VERSION 5.8 ;
BUSBITCHARS "[]" ;
DIVIDERCHAR "/" ;
UNITS
    DATABASE MICRONS 1000 ;
END UNITS

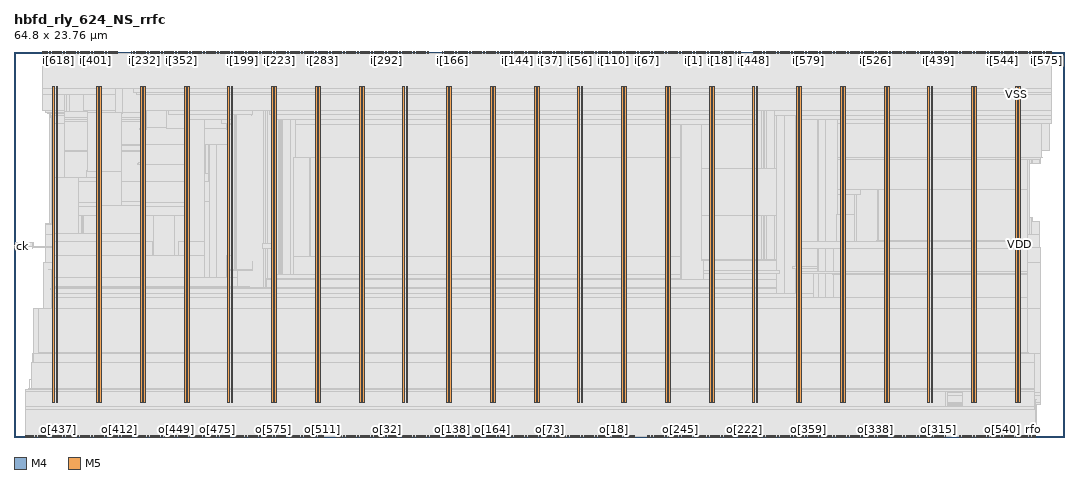
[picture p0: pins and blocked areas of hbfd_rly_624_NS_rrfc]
MACRO hbfd_rly_624_NS_rrfc
  FOREIGN hbfd_rly_624_NS_rrfc 0 0 ;
  CLASS BLOCK ;
  SIZE 64.8 BY 23.76 ;
  PIN ck
    DIRECTION INPUT ;
    USE SIGNAL ;
    PORT
      LAYER M4 ;
        RECT  0 11.76 0.084 11.784 ;
    END
  END ck
  PIN i[0]
    DIRECTION INPUT ;
    USE SIGNAL ;
    PORT
      LAYER M5 ;
        RECT  41.808 23.676 41.832 23.76 ;
    END
  END i[0]
  PIN i[100]
    DIRECTION INPUT ;
    USE SIGNAL ;
    PORT
      LAYER M5 ;
        RECT  36.048 23.676 36.072 23.76 ;
    END
  END i[100]
  PIN i[101]
    DIRECTION INPUT ;
    USE SIGNAL ;
    PORT
      LAYER M5 ;
        RECT  36.144 23.676 36.168 23.76 ;
    END
  END i[101]
  PIN i[102]
    DIRECTION INPUT ;
    USE SIGNAL ;
    PORT
      LAYER M5 ;
        RECT  36.24 23.676 36.264 23.76 ;
    END
  END i[102]
  PIN i[103]
    DIRECTION INPUT ;
    USE SIGNAL ;
    PORT
      LAYER M5 ;
        RECT  36.336 23.676 36.36 23.76 ;
    END
  END i[103]
  PIN i[104]
    DIRECTION INPUT ;
    USE SIGNAL ;
    PORT
      LAYER M5 ;
        RECT  36.432 23.676 36.456 23.76 ;
    END
  END i[104]
  PIN i[105]
    DIRECTION INPUT ;
    USE SIGNAL ;
    PORT
      LAYER M5 ;
        RECT  36.528 23.676 36.552 23.76 ;
    END
  END i[105]
  PIN i[106]
    DIRECTION INPUT ;
    USE SIGNAL ;
    PORT
      LAYER M5 ;
        RECT  36.624 23.676 36.648 23.76 ;
    END
  END i[106]
  PIN i[107]
    DIRECTION INPUT ;
    USE SIGNAL ;
    PORT
      LAYER M5 ;
        RECT  36.72 23.676 36.744 23.76 ;
    END
  END i[107]
  PIN i[108]
    DIRECTION INPUT ;
    USE SIGNAL ;
    PORT
      LAYER M5 ;
        RECT  36.816 23.676 36.84 23.76 ;
    END
  END i[108]
  PIN i[109]
    DIRECTION INPUT ;
    USE SIGNAL ;
    PORT
      LAYER M5 ;
        RECT  36.912 23.676 36.936 23.76 ;
    END
  END i[109]
  PIN i[10]
    DIRECTION INPUT ;
    USE SIGNAL ;
    PORT
      LAYER M5 ;
        RECT  42.768 23.676 42.792 23.76 ;
    END
  END i[10]
  PIN i[110]
    DIRECTION INPUT ;
    USE SIGNAL ;
    PORT
      LAYER M5 ;
        RECT  37.008 23.676 37.032 23.76 ;
    END
  END i[110]
  PIN i[111]
    DIRECTION INPUT ;
    USE SIGNAL ;
    PORT
      LAYER M5 ;
        RECT  37.104 23.676 37.128 23.76 ;
    END
  END i[111]
  PIN i[112]
    DIRECTION INPUT ;
    USE SIGNAL ;
    PORT
      LAYER M5 ;
        RECT  37.2 23.676 37.224 23.76 ;
    END
  END i[112]
  PIN i[113]
    DIRECTION INPUT ;
    USE SIGNAL ;
    PORT
      LAYER M5 ;
        RECT  37.296 23.676 37.32 23.76 ;
    END
  END i[113]
  PIN i[114]
    DIRECTION INPUT ;
    USE SIGNAL ;
    PORT
      LAYER M5 ;
        RECT  37.392 23.676 37.416 23.76 ;
    END
  END i[114]
  PIN i[115]
    DIRECTION INPUT ;
    USE SIGNAL ;
    PORT
      LAYER M5 ;
        RECT  37.488 23.676 37.512 23.76 ;
    END
  END i[115]
  PIN i[116]
    DIRECTION INPUT ;
    USE SIGNAL ;
    PORT
      LAYER M5 ;
        RECT  37.584 23.676 37.608 23.76 ;
    END
  END i[116]
  PIN i[117]
    DIRECTION INPUT ;
    USE SIGNAL ;
    PORT
      LAYER M5 ;
        RECT  37.68 23.676 37.704 23.76 ;
    END
  END i[117]
  PIN i[118]
    DIRECTION INPUT ;
    USE SIGNAL ;
    PORT
      LAYER M5 ;
        RECT  37.776 23.676 37.8 23.76 ;
    END
  END i[118]
  PIN i[119]
    DIRECTION INPUT ;
    USE SIGNAL ;
    PORT
      LAYER M5 ;
        RECT  37.872 23.676 37.896 23.76 ;
    END
  END i[119]
  PIN i[11]
    DIRECTION INPUT ;
    USE SIGNAL ;
    PORT
      LAYER M5 ;
        RECT  42.864 23.676 42.888 23.76 ;
    END
  END i[11]
  PIN i[120]
    DIRECTION INPUT ;
    USE SIGNAL ;
    PORT
      LAYER M5 ;
        RECT  37.968 23.676 37.992 23.76 ;
    END
  END i[120]
  PIN i[121]
    DIRECTION INPUT ;
    USE SIGNAL ;
    PORT
      LAYER M5 ;
        RECT  38.064 23.676 38.088 23.76 ;
    END
  END i[121]
  PIN i[122]
    DIRECTION INPUT ;
    USE SIGNAL ;
    PORT
      LAYER M5 ;
        RECT  38.16 23.676 38.184 23.76 ;
    END
  END i[122]
  PIN i[123]
    DIRECTION INPUT ;
    USE SIGNAL ;
    PORT
      LAYER M5 ;
        RECT  38.256 23.676 38.28 23.76 ;
    END
  END i[123]
  PIN i[124]
    DIRECTION INPUT ;
    USE SIGNAL ;
    PORT
      LAYER M5 ;
        RECT  38.352 23.676 38.376 23.76 ;
    END
  END i[124]
  PIN i[125]
    DIRECTION INPUT ;
    USE SIGNAL ;
    PORT
      LAYER M5 ;
        RECT  38.448 23.676 38.472 23.76 ;
    END
  END i[125]
  PIN i[126]
    DIRECTION INPUT ;
    USE SIGNAL ;
    PORT
      LAYER M5 ;
        RECT  38.544 23.676 38.568 23.76 ;
    END
  END i[126]
  PIN i[127]
    DIRECTION INPUT ;
    USE SIGNAL ;
    PORT
      LAYER M5 ;
        RECT  38.64 23.676 38.664 23.76 ;
    END
  END i[127]
  PIN i[128]
    DIRECTION INPUT ;
    USE SIGNAL ;
    PORT
      LAYER M5 ;
        RECT  29.52 23.676 29.544 23.76 ;
    END
  END i[128]
  PIN i[129]
    DIRECTION INPUT ;
    USE SIGNAL ;
    PORT
      LAYER M5 ;
        RECT  29.616 23.676 29.64 23.76 ;
    END
  END i[129]
  PIN i[12]
    DIRECTION INPUT ;
    USE SIGNAL ;
    PORT
      LAYER M5 ;
        RECT  42.96 23.676 42.984 23.76 ;
    END
  END i[12]
  PIN i[130]
    DIRECTION INPUT ;
    USE SIGNAL ;
    PORT
      LAYER M5 ;
        RECT  29.712 23.676 29.736 23.76 ;
    END
  END i[130]
  PIN i[131]
    DIRECTION INPUT ;
    USE SIGNAL ;
    PORT
      LAYER M5 ;
        RECT  29.808 23.676 29.832 23.76 ;
    END
  END i[131]
  PIN i[132]
    DIRECTION INPUT ;
    USE SIGNAL ;
    PORT
      LAYER M5 ;
        RECT  29.904 23.676 29.928 23.76 ;
    END
  END i[132]
  PIN i[133]
    DIRECTION INPUT ;
    USE SIGNAL ;
    PORT
      LAYER M5 ;
        RECT  30 23.676 30.024 23.76 ;
    END
  END i[133]
  PIN i[134]
    DIRECTION INPUT ;
    USE SIGNAL ;
    PORT
      LAYER M5 ;
        RECT  30.096 23.676 30.12 23.76 ;
    END
  END i[134]
  PIN i[135]
    DIRECTION INPUT ;
    USE SIGNAL ;
    PORT
      LAYER M5 ;
        RECT  30.192 23.676 30.216 23.76 ;
    END
  END i[135]
  PIN i[136]
    DIRECTION INPUT ;
    USE SIGNAL ;
    PORT
      LAYER M5 ;
        RECT  30.288 23.676 30.312 23.76 ;
    END
  END i[136]
  PIN i[137]
    DIRECTION INPUT ;
    USE SIGNAL ;
    PORT
      LAYER M5 ;
        RECT  30.384 23.676 30.408 23.76 ;
    END
  END i[137]
  PIN i[138]
    DIRECTION INPUT ;
    USE SIGNAL ;
    PORT
      LAYER M5 ;
        RECT  30.48 23.676 30.504 23.76 ;
    END
  END i[138]
  PIN i[139]
    DIRECTION INPUT ;
    USE SIGNAL ;
    PORT
      LAYER M5 ;
        RECT  30.576 23.676 30.6 23.76 ;
    END
  END i[139]
  PIN i[13]
    DIRECTION INPUT ;
    USE SIGNAL ;
    PORT
      LAYER M5 ;
        RECT  43.056 23.676 43.08 23.76 ;
    END
  END i[13]
  PIN i[140]
    DIRECTION INPUT ;
    USE SIGNAL ;
    PORT
      LAYER M5 ;
        RECT  30.672 23.676 30.696 23.76 ;
    END
  END i[140]
  PIN i[141]
    DIRECTION INPUT ;
    USE SIGNAL ;
    PORT
      LAYER M5 ;
        RECT  30.768 23.676 30.792 23.76 ;
    END
  END i[141]
  PIN i[142]
    DIRECTION INPUT ;
    USE SIGNAL ;
    PORT
      LAYER M5 ;
        RECT  30.864 23.676 30.888 23.76 ;
    END
  END i[142]
  PIN i[143]
    DIRECTION INPUT ;
    USE SIGNAL ;
    PORT
      LAYER M5 ;
        RECT  30.96 23.676 30.984 23.76 ;
    END
  END i[143]
  PIN i[144]
    DIRECTION INPUT ;
    USE SIGNAL ;
    PORT
      LAYER M5 ;
        RECT  31.056 23.676 31.08 23.76 ;
    END
  END i[144]
  PIN i[145]
    DIRECTION INPUT ;
    USE SIGNAL ;
    PORT
      LAYER M5 ;
        RECT  31.152 23.676 31.176 23.76 ;
    END
  END i[145]
  PIN i[146]
    DIRECTION INPUT ;
    USE SIGNAL ;
    PORT
      LAYER M5 ;
        RECT  31.248 23.676 31.272 23.76 ;
    END
  END i[146]
  PIN i[147]
    DIRECTION INPUT ;
    USE SIGNAL ;
    PORT
      LAYER M5 ;
        RECT  31.344 23.676 31.368 23.76 ;
    END
  END i[147]
  PIN i[148]
    DIRECTION INPUT ;
    USE SIGNAL ;
    PORT
      LAYER M5 ;
        RECT  31.44 23.676 31.464 23.76 ;
    END
  END i[148]
  PIN i[149]
    DIRECTION INPUT ;
    USE SIGNAL ;
    PORT
      LAYER M5 ;
        RECT  31.536 23.676 31.56 23.76 ;
    END
  END i[149]
  PIN i[14]
    DIRECTION INPUT ;
    USE SIGNAL ;
    PORT
      LAYER M5 ;
        RECT  43.152 23.676 43.176 23.76 ;
    END
  END i[14]
  PIN i[150]
    DIRECTION INPUT ;
    USE SIGNAL ;
    PORT
      LAYER M5 ;
        RECT  31.632 23.676 31.656 23.76 ;
    END
  END i[150]
  PIN i[151]
    DIRECTION INPUT ;
    USE SIGNAL ;
    PORT
      LAYER M5 ;
        RECT  31.728 23.676 31.752 23.76 ;
    END
  END i[151]
  PIN i[152]
    DIRECTION INPUT ;
    USE SIGNAL ;
    PORT
      LAYER M5 ;
        RECT  31.824 23.676 31.848 23.76 ;
    END
  END i[152]
  PIN i[153]
    DIRECTION INPUT ;
    USE SIGNAL ;
    PORT
      LAYER M5 ;
        RECT  31.92 23.676 31.944 23.76 ;
    END
  END i[153]
  PIN i[154]
    DIRECTION INPUT ;
    USE SIGNAL ;
    PORT
      LAYER M5 ;
        RECT  32.016 23.676 32.04 23.76 ;
    END
  END i[154]
  PIN i[155]
    DIRECTION INPUT ;
    USE SIGNAL ;
    PORT
      LAYER M5 ;
        RECT  32.112 23.676 32.136 23.76 ;
    END
  END i[155]
  PIN i[156]
    DIRECTION INPUT ;
    USE SIGNAL ;
    PORT
      LAYER M5 ;
        RECT  32.208 23.676 32.232 23.76 ;
    END
  END i[156]
  PIN i[157]
    DIRECTION INPUT ;
    USE SIGNAL ;
    PORT
      LAYER M5 ;
        RECT  32.304 23.676 32.328 23.76 ;
    END
  END i[157]
  PIN i[158]
    DIRECTION INPUT ;
    USE SIGNAL ;
    PORT
      LAYER M5 ;
        RECT  32.4 23.676 32.424 23.76 ;
    END
  END i[158]
  PIN i[159]
    DIRECTION INPUT ;
    USE SIGNAL ;
    PORT
      LAYER M5 ;
        RECT  32.496 23.676 32.52 23.76 ;
    END
  END i[159]
  PIN i[15]
    DIRECTION INPUT ;
    USE SIGNAL ;
    PORT
      LAYER M5 ;
        RECT  43.248 23.676 43.272 23.76 ;
    END
  END i[15]
  PIN i[160]
    DIRECTION INPUT ;
    USE SIGNAL ;
    PORT
      LAYER M5 ;
        RECT  26.448 23.676 26.472 23.76 ;
    END
  END i[160]
  PIN i[161]
    DIRECTION INPUT ;
    USE SIGNAL ;
    PORT
      LAYER M5 ;
        RECT  26.544 23.676 26.568 23.76 ;
    END
  END i[161]
  PIN i[162]
    DIRECTION INPUT ;
    USE SIGNAL ;
    PORT
      LAYER M5 ;
        RECT  26.64 23.676 26.664 23.76 ;
    END
  END i[162]
  PIN i[163]
    DIRECTION INPUT ;
    USE SIGNAL ;
    PORT
      LAYER M5 ;
        RECT  26.736 23.676 26.76 23.76 ;
    END
  END i[163]
  PIN i[164]
    DIRECTION INPUT ;
    USE SIGNAL ;
    PORT
      LAYER M5 ;
        RECT  26.832 23.676 26.856 23.76 ;
    END
  END i[164]
  PIN i[165]
    DIRECTION INPUT ;
    USE SIGNAL ;
    PORT
      LAYER M5 ;
        RECT  26.928 23.676 26.952 23.76 ;
    END
  END i[165]
  PIN i[166]
    DIRECTION INPUT ;
    USE SIGNAL ;
    PORT
      LAYER M5 ;
        RECT  27.024 23.676 27.048 23.76 ;
    END
  END i[166]
  PIN i[167]
    DIRECTION INPUT ;
    USE SIGNAL ;
    PORT
      LAYER M5 ;
        RECT  27.12 23.676 27.144 23.76 ;
    END
  END i[167]
  PIN i[168]
    DIRECTION INPUT ;
    USE SIGNAL ;
    PORT
      LAYER M5 ;
        RECT  27.216 23.676 27.24 23.76 ;
    END
  END i[168]
  PIN i[169]
    DIRECTION INPUT ;
    USE SIGNAL ;
    PORT
      LAYER M5 ;
        RECT  27.312 23.676 27.336 23.76 ;
    END
  END i[169]
  PIN i[16]
    DIRECTION INPUT ;
    USE SIGNAL ;
    PORT
      LAYER M5 ;
        RECT  43.344 23.676 43.368 23.76 ;
    END
  END i[16]
  PIN i[170]
    DIRECTION INPUT ;
    USE SIGNAL ;
    PORT
      LAYER M5 ;
        RECT  27.408 23.676 27.432 23.76 ;
    END
  END i[170]
  PIN i[171]
    DIRECTION INPUT ;
    USE SIGNAL ;
    PORT
      LAYER M5 ;
        RECT  27.504 23.676 27.528 23.76 ;
    END
  END i[171]
  PIN i[172]
    DIRECTION INPUT ;
    USE SIGNAL ;
    PORT
      LAYER M5 ;
        RECT  27.6 23.676 27.624 23.76 ;
    END
  END i[172]
  PIN i[173]
    DIRECTION INPUT ;
    USE SIGNAL ;
    PORT
      LAYER M5 ;
        RECT  27.696 23.676 27.72 23.76 ;
    END
  END i[173]
  PIN i[174]
    DIRECTION INPUT ;
    USE SIGNAL ;
    PORT
      LAYER M5 ;
        RECT  27.792 23.676 27.816 23.76 ;
    END
  END i[174]
  PIN i[175]
    DIRECTION INPUT ;
    USE SIGNAL ;
    PORT
      LAYER M5 ;
        RECT  27.888 23.676 27.912 23.76 ;
    END
  END i[175]
  PIN i[176]
    DIRECTION INPUT ;
    USE SIGNAL ;
    PORT
      LAYER M5 ;
        RECT  27.984 23.676 28.008 23.76 ;
    END
  END i[176]
  PIN i[177]
    DIRECTION INPUT ;
    USE SIGNAL ;
    PORT
      LAYER M5 ;
        RECT  28.08 23.676 28.104 23.76 ;
    END
  END i[177]
  PIN i[178]
    DIRECTION INPUT ;
    USE SIGNAL ;
    PORT
      LAYER M5 ;
        RECT  28.176 23.676 28.2 23.76 ;
    END
  END i[178]
  PIN i[179]
    DIRECTION INPUT ;
    USE SIGNAL ;
    PORT
      LAYER M5 ;
        RECT  28.272 23.676 28.296 23.76 ;
    END
  END i[179]
  PIN i[17]
    DIRECTION INPUT ;
    USE SIGNAL ;
    PORT
      LAYER M5 ;
        RECT  43.44 23.676 43.464 23.76 ;
    END
  END i[17]
  PIN i[180]
    DIRECTION INPUT ;
    USE SIGNAL ;
    PORT
      LAYER M5 ;
        RECT  28.368 23.676 28.392 23.76 ;
    END
  END i[180]
  PIN i[181]
    DIRECTION INPUT ;
    USE SIGNAL ;
    PORT
      LAYER M5 ;
        RECT  28.464 23.676 28.488 23.76 ;
    END
  END i[181]
  PIN i[182]
    DIRECTION INPUT ;
    USE SIGNAL ;
    PORT
      LAYER M5 ;
        RECT  28.56 23.676 28.584 23.76 ;
    END
  END i[182]
  PIN i[183]
    DIRECTION INPUT ;
    USE SIGNAL ;
    PORT
      LAYER M5 ;
        RECT  28.656 23.676 28.68 23.76 ;
    END
  END i[183]
  PIN i[184]
    DIRECTION INPUT ;
    USE SIGNAL ;
    PORT
      LAYER M5 ;
        RECT  28.752 23.676 28.776 23.76 ;
    END
  END i[184]
  PIN i[185]
    DIRECTION INPUT ;
    USE SIGNAL ;
    PORT
      LAYER M5 ;
        RECT  28.848 23.676 28.872 23.76 ;
    END
  END i[185]
  PIN i[186]
    DIRECTION INPUT ;
    USE SIGNAL ;
    PORT
      LAYER M5 ;
        RECT  28.944 23.676 28.968 23.76 ;
    END
  END i[186]
  PIN i[187]
    DIRECTION INPUT ;
    USE SIGNAL ;
    PORT
      LAYER M5 ;
        RECT  29.04 23.676 29.064 23.76 ;
    END
  END i[187]
  PIN i[188]
    DIRECTION INPUT ;
    USE SIGNAL ;
    PORT
      LAYER M5 ;
        RECT  29.136 23.676 29.16 23.76 ;
    END
  END i[188]
  PIN i[189]
    DIRECTION INPUT ;
    USE SIGNAL ;
    PORT
      LAYER M5 ;
        RECT  29.232 23.676 29.256 23.76 ;
    END
  END i[189]
  PIN i[18]
    DIRECTION INPUT ;
    USE SIGNAL ;
    PORT
      LAYER M5 ;
        RECT  43.536 23.676 43.56 23.76 ;
    END
  END i[18]
  PIN i[190]
    DIRECTION INPUT ;
    USE SIGNAL ;
    PORT
      LAYER M5 ;
        RECT  29.328 23.676 29.352 23.76 ;
    END
  END i[190]
  PIN i[191]
    DIRECTION INPUT ;
    USE SIGNAL ;
    PORT
      LAYER M5 ;
        RECT  29.424 23.676 29.448 23.76 ;
    END
  END i[191]
  PIN i[192]
    DIRECTION INPUT ;
    USE SIGNAL ;
    PORT
      LAYER M5 ;
        RECT  13.392 23.676 13.416 23.76 ;
    END
  END i[192]
  PIN i[193]
    DIRECTION INPUT ;
    USE SIGNAL ;
    PORT
      LAYER M5 ;
        RECT  13.488 23.676 13.512 23.76 ;
    END
  END i[193]
  PIN i[194]
    DIRECTION INPUT ;
    USE SIGNAL ;
    PORT
      LAYER M5 ;
        RECT  13.584 23.676 13.608 23.76 ;
    END
  END i[194]
  PIN i[195]
    DIRECTION INPUT ;
    USE SIGNAL ;
    PORT
      LAYER M5 ;
        RECT  13.68 23.676 13.704 23.76 ;
    END
  END i[195]
  PIN i[196]
    DIRECTION INPUT ;
    USE SIGNAL ;
    PORT
      LAYER M5 ;
        RECT  13.776 23.676 13.8 23.76 ;
    END
  END i[196]
  PIN i[197]
    DIRECTION INPUT ;
    USE SIGNAL ;
    PORT
      LAYER M5 ;
        RECT  13.872 23.676 13.896 23.76 ;
    END
  END i[197]
  PIN i[198]
    DIRECTION INPUT ;
    USE SIGNAL ;
    PORT
      LAYER M5 ;
        RECT  13.968 23.676 13.992 23.76 ;
    END
  END i[198]
  PIN i[199]
    DIRECTION INPUT ;
    USE SIGNAL ;
    PORT
      LAYER M5 ;
        RECT  14.064 23.676 14.088 23.76 ;
    END
  END i[199]
  PIN i[19]
    DIRECTION INPUT ;
    USE SIGNAL ;
    PORT
      LAYER M5 ;
        RECT  43.632 23.676 43.656 23.76 ;
    END
  END i[19]
  PIN i[1]
    DIRECTION INPUT ;
    USE SIGNAL ;
    PORT
      LAYER M5 ;
        RECT  41.904 23.676 41.928 23.76 ;
    END
  END i[1]
  PIN i[200]
    DIRECTION INPUT ;
    USE SIGNAL ;
    PORT
      LAYER M5 ;
        RECT  14.16 23.676 14.184 23.76 ;
    END
  END i[200]
  PIN i[201]
    DIRECTION INPUT ;
    USE SIGNAL ;
    PORT
      LAYER M5 ;
        RECT  14.256 23.676 14.28 23.76 ;
    END
  END i[201]
  PIN i[202]
    DIRECTION INPUT ;
    USE SIGNAL ;
    PORT
      LAYER M5 ;
        RECT  14.352 23.676 14.376 23.76 ;
    END
  END i[202]
  PIN i[203]
    DIRECTION INPUT ;
    USE SIGNAL ;
    PORT
      LAYER M5 ;
        RECT  14.448 23.676 14.472 23.76 ;
    END
  END i[203]
  PIN i[204]
    DIRECTION INPUT ;
    USE SIGNAL ;
    PORT
      LAYER M5 ;
        RECT  14.544 23.676 14.568 23.76 ;
    END
  END i[204]
  PIN i[205]
    DIRECTION INPUT ;
    USE SIGNAL ;
    PORT
      LAYER M5 ;
        RECT  14.64 23.676 14.664 23.76 ;
    END
  END i[205]
  PIN i[206]
    DIRECTION INPUT ;
    USE SIGNAL ;
    PORT
      LAYER M5 ;
        RECT  14.736 23.676 14.76 23.76 ;
    END
  END i[206]
  PIN i[207]
    DIRECTION INPUT ;
    USE SIGNAL ;
    PORT
      LAYER M5 ;
        RECT  14.832 23.676 14.856 23.76 ;
    END
  END i[207]
  PIN i[208]
    DIRECTION INPUT ;
    USE SIGNAL ;
    PORT
      LAYER M5 ;
        RECT  14.928 23.676 14.952 23.76 ;
    END
  END i[208]
  PIN i[209]
    DIRECTION INPUT ;
    USE SIGNAL ;
    PORT
      LAYER M5 ;
        RECT  15.024 23.676 15.048 23.76 ;
    END
  END i[209]
  PIN i[20]
    DIRECTION INPUT ;
    USE SIGNAL ;
    PORT
      LAYER M5 ;
        RECT  43.728 23.676 43.752 23.76 ;
    END
  END i[20]
  PIN i[210]
    DIRECTION INPUT ;
    USE SIGNAL ;
    PORT
      LAYER M5 ;
        RECT  15.12 23.676 15.144 23.76 ;
    END
  END i[210]
  PIN i[211]
    DIRECTION INPUT ;
    USE SIGNAL ;
    PORT
      LAYER M5 ;
        RECT  15.216 23.676 15.24 23.76 ;
    END
  END i[211]
  PIN i[212]
    DIRECTION INPUT ;
    USE SIGNAL ;
    PORT
      LAYER M5 ;
        RECT  15.312 23.676 15.336 23.76 ;
    END
  END i[212]
  PIN i[213]
    DIRECTION INPUT ;
    USE SIGNAL ;
    PORT
      LAYER M5 ;
        RECT  15.408 23.676 15.432 23.76 ;
    END
  END i[213]
  PIN i[214]
    DIRECTION INPUT ;
    USE SIGNAL ;
    PORT
      LAYER M5 ;
        RECT  15.504 23.676 15.528 23.76 ;
    END
  END i[214]
  PIN i[215]
    DIRECTION INPUT ;
    USE SIGNAL ;
    PORT
      LAYER M5 ;
        RECT  15.6 23.676 15.624 23.76 ;
    END
  END i[215]
  PIN i[216]
    DIRECTION INPUT ;
    USE SIGNAL ;
    PORT
      LAYER M5 ;
        RECT  15.696 23.676 15.72 23.76 ;
    END
  END i[216]
  PIN i[217]
    DIRECTION INPUT ;
    USE SIGNAL ;
    PORT
      LAYER M5 ;
        RECT  15.792 23.676 15.816 23.76 ;
    END
  END i[217]
  PIN i[218]
    DIRECTION INPUT ;
    USE SIGNAL ;
    PORT
      LAYER M5 ;
        RECT  15.888 23.676 15.912 23.76 ;
    END
  END i[218]
  PIN i[219]
    DIRECTION INPUT ;
    USE SIGNAL ;
    PORT
      LAYER M5 ;
        RECT  15.984 23.676 16.008 23.76 ;
    END
  END i[219]
  PIN i[21]
    DIRECTION INPUT ;
    USE SIGNAL ;
    PORT
      LAYER M5 ;
        RECT  43.824 23.676 43.848 23.76 ;
    END
  END i[21]
  PIN i[220]
    DIRECTION INPUT ;
    USE SIGNAL ;
    PORT
      LAYER M5 ;
        RECT  16.08 23.676 16.104 23.76 ;
    END
  END i[220]
  PIN i[221]
    DIRECTION INPUT ;
    USE SIGNAL ;
    PORT
      LAYER M5 ;
        RECT  16.176 23.676 16.2 23.76 ;
    END
  END i[221]
  PIN i[222]
    DIRECTION INPUT ;
    USE SIGNAL ;
    PORT
      LAYER M5 ;
        RECT  16.272 23.676 16.296 23.76 ;
    END
  END i[222]
  PIN i[223]
    DIRECTION INPUT ;
    USE SIGNAL ;
    PORT
      LAYER M5 ;
        RECT  16.368 23.676 16.392 23.76 ;
    END
  END i[223]
  PIN i[224]
    DIRECTION INPUT ;
    USE SIGNAL ;
    PORT
      LAYER M5 ;
        RECT  7.248 23.676 7.272 23.76 ;
    END
  END i[224]
  PIN i[225]
    DIRECTION INPUT ;
    USE SIGNAL ;
    PORT
      LAYER M5 ;
        RECT  7.344 23.676 7.368 23.76 ;
    END
  END i[225]
  PIN i[226]
    DIRECTION INPUT ;
    USE SIGNAL ;
    PORT
      LAYER M5 ;
        RECT  7.44 23.676 7.464 23.76 ;
    END
  END i[226]
  PIN i[227]
    DIRECTION INPUT ;
    USE SIGNAL ;
    PORT
      LAYER M5 ;
        RECT  7.536 23.676 7.56 23.76 ;
    END
  END i[227]
  PIN i[228]
    DIRECTION INPUT ;
    USE SIGNAL ;
    PORT
      LAYER M5 ;
        RECT  7.632 23.676 7.656 23.76 ;
    END
  END i[228]
  PIN i[229]
    DIRECTION INPUT ;
    USE SIGNAL ;
    PORT
      LAYER M5 ;
        RECT  7.728 23.676 7.752 23.76 ;
    END
  END i[229]
  PIN i[22]
    DIRECTION INPUT ;
    USE SIGNAL ;
    PORT
      LAYER M5 ;
        RECT  43.92 23.676 43.944 23.76 ;
    END
  END i[22]
  PIN i[230]
    DIRECTION INPUT ;
    USE SIGNAL ;
    PORT
      LAYER M5 ;
        RECT  7.824 23.676 7.848 23.76 ;
    END
  END i[230]
  PIN i[231]
    DIRECTION INPUT ;
    USE SIGNAL ;
    PORT
      LAYER M5 ;
        RECT  7.92 23.676 7.944 23.76 ;
    END
  END i[231]
  PIN i[232]
    DIRECTION INPUT ;
    USE SIGNAL ;
    PORT
      LAYER M5 ;
        RECT  8.016 23.676 8.04 23.76 ;
    END
  END i[232]
  PIN i[233]
    DIRECTION INPUT ;
    USE SIGNAL ;
    PORT
      LAYER M5 ;
        RECT  8.112 23.676 8.136 23.76 ;
    END
  END i[233]
  PIN i[234]
    DIRECTION INPUT ;
    USE SIGNAL ;
    PORT
      LAYER M5 ;
        RECT  8.208 23.676 8.232 23.76 ;
    END
  END i[234]
  PIN i[235]
    DIRECTION INPUT ;
    USE SIGNAL ;
    PORT
      LAYER M5 ;
        RECT  8.304 23.676 8.328 23.76 ;
    END
  END i[235]
  PIN i[236]
    DIRECTION INPUT ;
    USE SIGNAL ;
    PORT
      LAYER M5 ;
        RECT  8.4 23.676 8.424 23.76 ;
    END
  END i[236]
  PIN i[237]
    DIRECTION INPUT ;
    USE SIGNAL ;
    PORT
      LAYER M5 ;
        RECT  8.496 23.676 8.52 23.76 ;
    END
  END i[237]
  PIN i[238]
    DIRECTION INPUT ;
    USE SIGNAL ;
    PORT
      LAYER M5 ;
        RECT  8.592 23.676 8.616 23.76 ;
    END
  END i[238]
  PIN i[239]
    DIRECTION INPUT ;
    USE SIGNAL ;
    PORT
      LAYER M5 ;
        RECT  8.688 23.676 8.712 23.76 ;
    END
  END i[239]
  PIN i[23]
    DIRECTION INPUT ;
    USE SIGNAL ;
    PORT
      LAYER M5 ;
        RECT  44.016 23.676 44.04 23.76 ;
    END
  END i[23]
  PIN i[240]
    DIRECTION INPUT ;
    USE SIGNAL ;
    PORT
      LAYER M5 ;
        RECT  8.784 23.676 8.808 23.76 ;
    END
  END i[240]
  PIN i[241]
    DIRECTION INPUT ;
    USE SIGNAL ;
    PORT
      LAYER M5 ;
        RECT  8.88 23.676 8.904 23.76 ;
    END
  END i[241]
  PIN i[242]
    DIRECTION INPUT ;
    USE SIGNAL ;
    PORT
      LAYER M5 ;
        RECT  8.976 23.676 9 23.76 ;
    END
  END i[242]
  PIN i[243]
    DIRECTION INPUT ;
    USE SIGNAL ;
    PORT
      LAYER M5 ;
        RECT  9.072 23.676 9.096 23.76 ;
    END
  END i[243]
  PIN i[244]
    DIRECTION INPUT ;
    USE SIGNAL ;
    PORT
      LAYER M5 ;
        RECT  9.168 23.676 9.192 23.76 ;
    END
  END i[244]
  PIN i[245]
    DIRECTION INPUT ;
    USE SIGNAL ;
    PORT
      LAYER M5 ;
        RECT  9.264 23.676 9.288 23.76 ;
    END
  END i[245]
  PIN i[246]
    DIRECTION INPUT ;
    USE SIGNAL ;
    PORT
      LAYER M5 ;
        RECT  9.36 23.676 9.384 23.76 ;
    END
  END i[246]
  PIN i[247]
    DIRECTION INPUT ;
    USE SIGNAL ;
    PORT
      LAYER M5 ;
        RECT  9.456 23.676 9.48 23.76 ;
    END
  END i[247]
  PIN i[248]
    DIRECTION INPUT ;
    USE SIGNAL ;
    PORT
      LAYER M5 ;
        RECT  9.552 23.676 9.576 23.76 ;
    END
  END i[248]
  PIN i[249]
    DIRECTION INPUT ;
    USE SIGNAL ;
    PORT
      LAYER M5 ;
        RECT  9.648 23.676 9.672 23.76 ;
    END
  END i[249]
  PIN i[24]
    DIRECTION INPUT ;
    USE SIGNAL ;
    PORT
      LAYER M5 ;
        RECT  44.112 23.676 44.136 23.76 ;
    END
  END i[24]
  PIN i[250]
    DIRECTION INPUT ;
    USE SIGNAL ;
    PORT
      LAYER M5 ;
        RECT  9.744 23.676 9.768 23.76 ;
    END
  END i[250]
  PIN i[251]
    DIRECTION INPUT ;
    USE SIGNAL ;
    PORT
      LAYER M5 ;
        RECT  9.84 23.676 9.864 23.76 ;
    END
  END i[251]
  PIN i[252]
    DIRECTION INPUT ;
    USE SIGNAL ;
    PORT
      LAYER M5 ;
        RECT  9.936 23.676 9.96 23.76 ;
    END
  END i[252]
  PIN i[253]
    DIRECTION INPUT ;
    USE SIGNAL ;
    PORT
      LAYER M5 ;
        RECT  10.032 23.676 10.056 23.76 ;
    END
  END i[253]
  PIN i[254]
    DIRECTION INPUT ;
    USE SIGNAL ;
    PORT
      LAYER M5 ;
        RECT  10.128 23.676 10.152 23.76 ;
    END
  END i[254]
  PIN i[255]
    DIRECTION INPUT ;
    USE SIGNAL ;
    PORT
      LAYER M5 ;
        RECT  10.224 23.676 10.248 23.76 ;
    END
  END i[255]
  PIN i[256]
    DIRECTION INPUT ;
    USE SIGNAL ;
    PORT
      LAYER M5 ;
        RECT  16.464 23.676 16.488 23.76 ;
    END
  END i[256]
  PIN i[257]
    DIRECTION INPUT ;
    USE SIGNAL ;
    PORT
      LAYER M5 ;
        RECT  16.56 23.676 16.584 23.76 ;
    END
  END i[257]
  PIN i[258]
    DIRECTION INPUT ;
    USE SIGNAL ;
    PORT
      LAYER M5 ;
        RECT  16.656 23.676 16.68 23.76 ;
    END
  END i[258]
  PIN i[259]
    DIRECTION INPUT ;
    USE SIGNAL ;
    PORT
      LAYER M5 ;
        RECT  16.752 23.676 16.776 23.76 ;
    END
  END i[259]
  PIN i[25]
    DIRECTION INPUT ;
    USE SIGNAL ;
    PORT
      LAYER M5 ;
        RECT  44.208 23.676 44.232 23.76 ;
    END
  END i[25]
  PIN i[260]
    DIRECTION INPUT ;
    USE SIGNAL ;
    PORT
      LAYER M5 ;
        RECT  16.848 23.676 16.872 23.76 ;
    END
  END i[260]
  PIN i[261]
    DIRECTION INPUT ;
    USE SIGNAL ;
    PORT
      LAYER M5 ;
        RECT  16.944 23.676 16.968 23.76 ;
    END
  END i[261]
  PIN i[262]
    DIRECTION INPUT ;
    USE SIGNAL ;
    PORT
      LAYER M5 ;
        RECT  17.04 23.676 17.064 23.76 ;
    END
  END i[262]
  PIN i[263]
    DIRECTION INPUT ;
    USE SIGNAL ;
    PORT
      LAYER M5 ;
        RECT  17.136 23.676 17.16 23.76 ;
    END
  END i[263]
  PIN i[264]
    DIRECTION INPUT ;
    USE SIGNAL ;
    PORT
      LAYER M5 ;
        RECT  17.232 23.676 17.256 23.76 ;
    END
  END i[264]
  PIN i[265]
    DIRECTION INPUT ;
    USE SIGNAL ;
    PORT
      LAYER M5 ;
        RECT  17.328 23.676 17.352 23.76 ;
    END
  END i[265]
  PIN i[266]
    DIRECTION INPUT ;
    USE SIGNAL ;
    PORT
      LAYER M5 ;
        RECT  17.424 23.676 17.448 23.76 ;
    END
  END i[266]
  PIN i[267]
    DIRECTION INPUT ;
    USE SIGNAL ;
    PORT
      LAYER M5 ;
        RECT  17.52 23.676 17.544 23.76 ;
    END
  END i[267]
  PIN i[268]
    DIRECTION INPUT ;
    USE SIGNAL ;
    PORT
      LAYER M5 ;
        RECT  17.616 23.676 17.64 23.76 ;
    END
  END i[268]
  PIN i[269]
    DIRECTION INPUT ;
    USE SIGNAL ;
    PORT
      LAYER M5 ;
        RECT  17.712 23.676 17.736 23.76 ;
    END
  END i[269]
  PIN i[26]
    DIRECTION INPUT ;
    USE SIGNAL ;
    PORT
      LAYER M5 ;
        RECT  44.304 23.676 44.328 23.76 ;
    END
  END i[26]
  PIN i[270]
    DIRECTION INPUT ;
    USE SIGNAL ;
    PORT
      LAYER M5 ;
        RECT  17.808 23.676 17.832 23.76 ;
    END
  END i[270]
  PIN i[271]
    DIRECTION INPUT ;
    USE SIGNAL ;
    PORT
      LAYER M5 ;
        RECT  17.904 23.676 17.928 23.76 ;
    END
  END i[271]
  PIN i[272]
    DIRECTION INPUT ;
    USE SIGNAL ;
    PORT
      LAYER M5 ;
        RECT  18 23.676 18.024 23.76 ;
    END
  END i[272]
  PIN i[273]
    DIRECTION INPUT ;
    USE SIGNAL ;
    PORT
      LAYER M5 ;
        RECT  18.096 23.676 18.12 23.76 ;
    END
  END i[273]
  PIN i[274]
    DIRECTION INPUT ;
    USE SIGNAL ;
    PORT
      LAYER M5 ;
        RECT  18.192 23.676 18.216 23.76 ;
    END
  END i[274]
  PIN i[275]
    DIRECTION INPUT ;
    USE SIGNAL ;
    PORT
      LAYER M5 ;
        RECT  18.288 23.676 18.312 23.76 ;
    END
  END i[275]
  PIN i[276]
    DIRECTION INPUT ;
    USE SIGNAL ;
    PORT
      LAYER M5 ;
        RECT  18.384 23.676 18.408 23.76 ;
    END
  END i[276]
  PIN i[277]
    DIRECTION INPUT ;
    USE SIGNAL ;
    PORT
      LAYER M5 ;
        RECT  18.48 23.676 18.504 23.76 ;
    END
  END i[277]
  PIN i[278]
    DIRECTION INPUT ;
    USE SIGNAL ;
    PORT
      LAYER M5 ;
        RECT  18.576 23.676 18.6 23.76 ;
    END
  END i[278]
  PIN i[279]
    DIRECTION INPUT ;
    USE SIGNAL ;
    PORT
      LAYER M5 ;
        RECT  18.672 23.676 18.696 23.76 ;
    END
  END i[279]
  PIN i[27]
    DIRECTION INPUT ;
    USE SIGNAL ;
    PORT
      LAYER M5 ;
        RECT  44.4 23.676 44.424 23.76 ;
    END
  END i[27]
  PIN i[280]
    DIRECTION INPUT ;
    USE SIGNAL ;
    PORT
      LAYER M5 ;
        RECT  18.768 23.676 18.792 23.76 ;
    END
  END i[280]
  PIN i[281]
    DIRECTION INPUT ;
    USE SIGNAL ;
    PORT
      LAYER M5 ;
        RECT  18.864 23.676 18.888 23.76 ;
    END
  END i[281]
  PIN i[282]
    DIRECTION INPUT ;
    USE SIGNAL ;
    PORT
      LAYER M5 ;
        RECT  18.96 23.676 18.984 23.76 ;
    END
  END i[282]
  PIN i[283]
    DIRECTION INPUT ;
    USE SIGNAL ;
    PORT
      LAYER M5 ;
        RECT  19.056 23.676 19.08 23.76 ;
    END
  END i[283]
  PIN i[284]
    DIRECTION INPUT ;
    USE SIGNAL ;
    PORT
      LAYER M5 ;
        RECT  19.152 23.676 19.176 23.76 ;
    END
  END i[284]
  PIN i[285]
    DIRECTION INPUT ;
    USE SIGNAL ;
    PORT
      LAYER M5 ;
        RECT  19.248 23.676 19.272 23.76 ;
    END
  END i[285]
  PIN i[286]
    DIRECTION INPUT ;
    USE SIGNAL ;
    PORT
      LAYER M5 ;
        RECT  19.344 23.676 19.368 23.76 ;
    END
  END i[286]
  PIN i[287]
    DIRECTION INPUT ;
    USE SIGNAL ;
    PORT
      LAYER M5 ;
        RECT  19.44 23.676 19.464 23.76 ;
    END
  END i[287]
  PIN i[288]
    DIRECTION INPUT ;
    USE SIGNAL ;
    PORT
      LAYER M5 ;
        RECT  22.608 23.676 22.632 23.76 ;
    END
  END i[288]
  PIN i[289]
    DIRECTION INPUT ;
    USE SIGNAL ;
    PORT
      LAYER M5 ;
        RECT  22.704 23.676 22.728 23.76 ;
    END
  END i[289]
  PIN i[28]
    DIRECTION INPUT ;
    USE SIGNAL ;
    PORT
      LAYER M5 ;
        RECT  44.496 23.676 44.52 23.76 ;
    END
  END i[28]
  PIN i[290]
    DIRECTION INPUT ;
    USE SIGNAL ;
    PORT
      LAYER M5 ;
        RECT  22.8 23.676 22.824 23.76 ;
    END
  END i[290]
  PIN i[291]
    DIRECTION INPUT ;
    USE SIGNAL ;
    PORT
      LAYER M5 ;
        RECT  22.896 23.676 22.92 23.76 ;
    END
  END i[291]
  PIN i[292]
    DIRECTION INPUT ;
    USE SIGNAL ;
    PORT
      LAYER M5 ;
        RECT  22.992 23.676 23.016 23.76 ;
    END
  END i[292]
  PIN i[293]
    DIRECTION INPUT ;
    USE SIGNAL ;
    PORT
      LAYER M5 ;
        RECT  23.088 23.676 23.112 23.76 ;
    END
  END i[293]
  PIN i[294]
    DIRECTION INPUT ;
    USE SIGNAL ;
    PORT
      LAYER M5 ;
        RECT  23.184 23.676 23.208 23.76 ;
    END
  END i[294]
  PIN i[295]
    DIRECTION INPUT ;
    USE SIGNAL ;
    PORT
      LAYER M5 ;
        RECT  23.28 23.676 23.304 23.76 ;
    END
  END i[295]
  PIN i[296]
    DIRECTION INPUT ;
    USE SIGNAL ;
    PORT
      LAYER M5 ;
        RECT  23.376 23.676 23.4 23.76 ;
    END
  END i[296]
  PIN i[297]
    DIRECTION INPUT ;
    USE SIGNAL ;
    PORT
      LAYER M5 ;
        RECT  23.472 23.676 23.496 23.76 ;
    END
  END i[297]
  PIN i[298]
    DIRECTION INPUT ;
    USE SIGNAL ;
    PORT
      LAYER M5 ;
        RECT  23.568 23.676 23.592 23.76 ;
    END
  END i[298]
  PIN i[299]
    DIRECTION INPUT ;
    USE SIGNAL ;
    PORT
      LAYER M5 ;
        RECT  23.664 23.676 23.688 23.76 ;
    END
  END i[299]
  PIN i[29]
    DIRECTION INPUT ;
    USE SIGNAL ;
    PORT
      LAYER M5 ;
        RECT  44.592 23.676 44.616 23.76 ;
    END
  END i[29]
  PIN i[2]
    DIRECTION INPUT ;
    USE SIGNAL ;
    PORT
      LAYER M5 ;
        RECT  42 23.676 42.024 23.76 ;
    END
  END i[2]
  PIN i[300]
    DIRECTION INPUT ;
    USE SIGNAL ;
    PORT
      LAYER M5 ;
        RECT  23.76 23.676 23.784 23.76 ;
    END
  END i[300]
  PIN i[301]
    DIRECTION INPUT ;
    USE SIGNAL ;
    PORT
      LAYER M5 ;
        RECT  23.856 23.676 23.88 23.76 ;
    END
  END i[301]
  PIN i[302]
    DIRECTION INPUT ;
    USE SIGNAL ;
    PORT
      LAYER M5 ;
        RECT  23.952 23.676 23.976 23.76 ;
    END
  END i[302]
  PIN i[303]
    DIRECTION INPUT ;
    USE SIGNAL ;
    PORT
      LAYER M5 ;
        RECT  24.048 23.676 24.072 23.76 ;
    END
  END i[303]
  PIN i[304]
    DIRECTION INPUT ;
    USE SIGNAL ;
    PORT
      LAYER M5 ;
        RECT  24.144 23.676 24.168 23.76 ;
    END
  END i[304]
  PIN i[305]
    DIRECTION INPUT ;
    USE SIGNAL ;
    PORT
      LAYER M5 ;
        RECT  24.24 23.676 24.264 23.76 ;
    END
  END i[305]
  PIN i[306]
    DIRECTION INPUT ;
    USE SIGNAL ;
    PORT
      LAYER M5 ;
        RECT  24.336 23.676 24.36 23.76 ;
    END
  END i[306]
  PIN i[307]
    DIRECTION INPUT ;
    USE SIGNAL ;
    PORT
      LAYER M5 ;
        RECT  24.432 23.676 24.456 23.76 ;
    END
  END i[307]
  PIN i[308]
    DIRECTION INPUT ;
    USE SIGNAL ;
    PORT
      LAYER M5 ;
        RECT  24.528 23.676 24.552 23.76 ;
    END
  END i[308]
  PIN i[309]
    DIRECTION INPUT ;
    USE SIGNAL ;
    PORT
      LAYER M5 ;
        RECT  24.624 23.676 24.648 23.76 ;
    END
  END i[309]
  PIN i[30]
    DIRECTION INPUT ;
    USE SIGNAL ;
    PORT
      LAYER M5 ;
        RECT  44.688 23.676 44.712 23.76 ;
    END
  END i[30]
  PIN i[310]
    DIRECTION INPUT ;
    USE SIGNAL ;
    PORT
      LAYER M5 ;
        RECT  24.72 23.676 24.744 23.76 ;
    END
  END i[310]
  PIN i[311]
    DIRECTION INPUT ;
    USE SIGNAL ;
    PORT
      LAYER M5 ;
        RECT  24.816 23.676 24.84 23.76 ;
    END
  END i[311]
  PIN i[312]
    DIRECTION INPUT ;
    USE SIGNAL ;
    PORT
      LAYER M5 ;
        RECT  24.912 23.676 24.936 23.76 ;
    END
  END i[312]
  PIN i[313]
    DIRECTION INPUT ;
    USE SIGNAL ;
    PORT
      LAYER M5 ;
        RECT  25.008 23.676 25.032 23.76 ;
    END
  END i[313]
  PIN i[314]
    DIRECTION INPUT ;
    USE SIGNAL ;
    PORT
      LAYER M5 ;
        RECT  25.104 23.676 25.128 23.76 ;
    END
  END i[314]
  PIN i[315]
    DIRECTION INPUT ;
    USE SIGNAL ;
    PORT
      LAYER M5 ;
        RECT  25.2 23.676 25.224 23.76 ;
    END
  END i[315]
  PIN i[316]
    DIRECTION INPUT ;
    USE SIGNAL ;
    PORT
      LAYER M5 ;
        RECT  25.296 23.676 25.32 23.76 ;
    END
  END i[316]
  PIN i[317]
    DIRECTION INPUT ;
    USE SIGNAL ;
    PORT
      LAYER M5 ;
        RECT  25.392 23.676 25.416 23.76 ;
    END
  END i[317]
  PIN i[318]
    DIRECTION INPUT ;
    USE SIGNAL ;
    PORT
      LAYER M5 ;
        RECT  25.488 23.676 25.512 23.76 ;
    END
  END i[318]
  PIN i[319]
    DIRECTION INPUT ;
    USE SIGNAL ;
    PORT
      LAYER M5 ;
        RECT  25.584 23.676 25.608 23.76 ;
    END
  END i[319]
  PIN i[31]
    DIRECTION INPUT ;
    USE SIGNAL ;
    PORT
      LAYER M5 ;
        RECT  44.784 23.676 44.808 23.76 ;
    END
  END i[31]
  PIN i[320]
    DIRECTION INPUT ;
    USE SIGNAL ;
    PORT
      LAYER M5 ;
        RECT  19.536 23.676 19.56 23.76 ;
    END
  END i[320]
  PIN i[321]
    DIRECTION INPUT ;
    USE SIGNAL ;
    PORT
      LAYER M5 ;
        RECT  19.632 23.676 19.656 23.76 ;
    END
  END i[321]
  PIN i[322]
    DIRECTION INPUT ;
    USE SIGNAL ;
    PORT
      LAYER M5 ;
        RECT  19.728 23.676 19.752 23.76 ;
    END
  END i[322]
  PIN i[323]
    DIRECTION INPUT ;
    USE SIGNAL ;
    PORT
      LAYER M5 ;
        RECT  19.824 23.676 19.848 23.76 ;
    END
  END i[323]
  PIN i[324]
    DIRECTION INPUT ;
    USE SIGNAL ;
    PORT
      LAYER M5 ;
        RECT  19.92 23.676 19.944 23.76 ;
    END
  END i[324]
  PIN i[325]
    DIRECTION INPUT ;
    USE SIGNAL ;
    PORT
      LAYER M5 ;
        RECT  20.016 23.676 20.04 23.76 ;
    END
  END i[325]
  PIN i[326]
    DIRECTION INPUT ;
    USE SIGNAL ;
    PORT
      LAYER M5 ;
        RECT  20.112 23.676 20.136 23.76 ;
    END
  END i[326]
  PIN i[327]
    DIRECTION INPUT ;
    USE SIGNAL ;
    PORT
      LAYER M5 ;
        RECT  20.208 23.676 20.232 23.76 ;
    END
  END i[327]
  PIN i[328]
    DIRECTION INPUT ;
    USE SIGNAL ;
    PORT
      LAYER M5 ;
        RECT  20.304 23.676 20.328 23.76 ;
    END
  END i[328]
  PIN i[329]
    DIRECTION INPUT ;
    USE SIGNAL ;
    PORT
      LAYER M5 ;
        RECT  20.4 23.676 20.424 23.76 ;
    END
  END i[329]
  PIN i[32]
    DIRECTION INPUT ;
    USE SIGNAL ;
    PORT
      LAYER M5 ;
        RECT  32.592 23.676 32.616 23.76 ;
    END
  END i[32]
  PIN i[330]
    DIRECTION INPUT ;
    USE SIGNAL ;
    PORT
      LAYER M5 ;
        RECT  20.496 23.676 20.52 23.76 ;
    END
  END i[330]
  PIN i[331]
    DIRECTION INPUT ;
    USE SIGNAL ;
    PORT
      LAYER M5 ;
        RECT  20.592 23.676 20.616 23.76 ;
    END
  END i[331]
  PIN i[332]
    DIRECTION INPUT ;
    USE SIGNAL ;
    PORT
      LAYER M5 ;
        RECT  20.688 23.676 20.712 23.76 ;
    END
  END i[332]
  PIN i[333]
    DIRECTION INPUT ;
    USE SIGNAL ;
    PORT
      LAYER M5 ;
        RECT  20.784 23.676 20.808 23.76 ;
    END
  END i[333]
  PIN i[334]
    DIRECTION INPUT ;
    USE SIGNAL ;
    PORT
      LAYER M5 ;
        RECT  20.88 23.676 20.904 23.76 ;
    END
  END i[334]
  PIN i[335]
    DIRECTION INPUT ;
    USE SIGNAL ;
    PORT
      LAYER M5 ;
        RECT  20.976 23.676 21 23.76 ;
    END
  END i[335]
  PIN i[336]
    DIRECTION INPUT ;
    USE SIGNAL ;
    PORT
      LAYER M5 ;
        RECT  21.072 23.676 21.096 23.76 ;
    END
  END i[336]
  PIN i[337]
    DIRECTION INPUT ;
    USE SIGNAL ;
    PORT
      LAYER M5 ;
        RECT  21.168 23.676 21.192 23.76 ;
    END
  END i[337]
  PIN i[338]
    DIRECTION INPUT ;
    USE SIGNAL ;
    PORT
      LAYER M5 ;
        RECT  21.264 23.676 21.288 23.76 ;
    END
  END i[338]
  PIN i[339]
    DIRECTION INPUT ;
    USE SIGNAL ;
    PORT
      LAYER M5 ;
        RECT  21.36 23.676 21.384 23.76 ;
    END
  END i[339]
  PIN i[33]
    DIRECTION INPUT ;
    USE SIGNAL ;
    PORT
      LAYER M5 ;
        RECT  32.688 23.676 32.712 23.76 ;
    END
  END i[33]
  PIN i[340]
    DIRECTION INPUT ;
    USE SIGNAL ;
    PORT
      LAYER M5 ;
        RECT  21.456 23.676 21.48 23.76 ;
    END
  END i[340]
  PIN i[341]
    DIRECTION INPUT ;
    USE SIGNAL ;
    PORT
      LAYER M5 ;
        RECT  21.552 23.676 21.576 23.76 ;
    END
  END i[341]
  PIN i[342]
    DIRECTION INPUT ;
    USE SIGNAL ;
    PORT
      LAYER M5 ;
        RECT  21.648 23.676 21.672 23.76 ;
    END
  END i[342]
  PIN i[343]
    DIRECTION INPUT ;
    USE SIGNAL ;
    PORT
      LAYER M5 ;
        RECT  21.744 23.676 21.768 23.76 ;
    END
  END i[343]
  PIN i[344]
    DIRECTION INPUT ;
    USE SIGNAL ;
    PORT
      LAYER M5 ;
        RECT  21.84 23.676 21.864 23.76 ;
    END
  END i[344]
  PIN i[345]
    DIRECTION INPUT ;
    USE SIGNAL ;
    PORT
      LAYER M5 ;
        RECT  21.936 23.676 21.96 23.76 ;
    END
  END i[345]
  PIN i[346]
    DIRECTION INPUT ;
    USE SIGNAL ;
    PORT
      LAYER M5 ;
        RECT  22.032 23.676 22.056 23.76 ;
    END
  END i[346]
  PIN i[347]
    DIRECTION INPUT ;
    USE SIGNAL ;
    PORT
      LAYER M5 ;
        RECT  22.128 23.676 22.152 23.76 ;
    END
  END i[347]
  PIN i[348]
    DIRECTION INPUT ;
    USE SIGNAL ;
    PORT
      LAYER M5 ;
        RECT  22.224 23.676 22.248 23.76 ;
    END
  END i[348]
  PIN i[349]
    DIRECTION INPUT ;
    USE SIGNAL ;
    PORT
      LAYER M5 ;
        RECT  22.32 23.676 22.344 23.76 ;
    END
  END i[349]
  PIN i[34]
    DIRECTION INPUT ;
    USE SIGNAL ;
    PORT
      LAYER M5 ;
        RECT  32.784 23.676 32.808 23.76 ;
    END
  END i[34]
  PIN i[350]
    DIRECTION INPUT ;
    USE SIGNAL ;
    PORT
      LAYER M5 ;
        RECT  22.416 23.676 22.44 23.76 ;
    END
  END i[350]
  PIN i[351]
    DIRECTION INPUT ;
    USE SIGNAL ;
    PORT
      LAYER M5 ;
        RECT  22.512 23.676 22.536 23.76 ;
    END
  END i[351]
  PIN i[352]
    DIRECTION INPUT ;
    USE SIGNAL ;
    PORT
      LAYER M5 ;
        RECT  10.32 23.676 10.344 23.76 ;
    END
  END i[352]
  PIN i[353]
    DIRECTION INPUT ;
    USE SIGNAL ;
    PORT
      LAYER M5 ;
        RECT  10.416 23.676 10.44 23.76 ;
    END
  END i[353]
  PIN i[354]
    DIRECTION INPUT ;
    USE SIGNAL ;
    PORT
      LAYER M5 ;
        RECT  10.512 23.676 10.536 23.76 ;
    END
  END i[354]
  PIN i[355]
    DIRECTION INPUT ;
    USE SIGNAL ;
    PORT
      LAYER M5 ;
        RECT  10.608 23.676 10.632 23.76 ;
    END
  END i[355]
  PIN i[356]
    DIRECTION INPUT ;
    USE SIGNAL ;
    PORT
      LAYER M5 ;
        RECT  10.704 23.676 10.728 23.76 ;
    END
  END i[356]
  PIN i[357]
    DIRECTION INPUT ;
    USE SIGNAL ;
    PORT
      LAYER M5 ;
        RECT  10.8 23.676 10.824 23.76 ;
    END
  END i[357]
  PIN i[358]
    DIRECTION INPUT ;
    USE SIGNAL ;
    PORT
      LAYER M5 ;
        RECT  10.896 23.676 10.92 23.76 ;
    END
  END i[358]
  PIN i[359]
    DIRECTION INPUT ;
    USE SIGNAL ;
    PORT
      LAYER M5 ;
        RECT  10.992 23.676 11.016 23.76 ;
    END
  END i[359]
  PIN i[35]
    DIRECTION INPUT ;
    USE SIGNAL ;
    PORT
      LAYER M5 ;
        RECT  32.88 23.676 32.904 23.76 ;
    END
  END i[35]
  PIN i[360]
    DIRECTION INPUT ;
    USE SIGNAL ;
    PORT
      LAYER M5 ;
        RECT  11.088 23.676 11.112 23.76 ;
    END
  END i[360]
  PIN i[361]
    DIRECTION INPUT ;
    USE SIGNAL ;
    PORT
      LAYER M5 ;
        RECT  11.184 23.676 11.208 23.76 ;
    END
  END i[361]
  PIN i[362]
    DIRECTION INPUT ;
    USE SIGNAL ;
    PORT
      LAYER M5 ;
        RECT  11.28 23.676 11.304 23.76 ;
    END
  END i[362]
  PIN i[363]
    DIRECTION INPUT ;
    USE SIGNAL ;
    PORT
      LAYER M5 ;
        RECT  11.376 23.676 11.4 23.76 ;
    END
  END i[363]
  PIN i[364]
    DIRECTION INPUT ;
    USE SIGNAL ;
    PORT
      LAYER M5 ;
        RECT  11.472 23.676 11.496 23.76 ;
    END
  END i[364]
  PIN i[365]
    DIRECTION INPUT ;
    USE SIGNAL ;
    PORT
      LAYER M5 ;
        RECT  11.568 23.676 11.592 23.76 ;
    END
  END i[365]
  PIN i[366]
    DIRECTION INPUT ;
    USE SIGNAL ;
    PORT
      LAYER M5 ;
        RECT  11.664 23.676 11.688 23.76 ;
    END
  END i[366]
  PIN i[367]
    DIRECTION INPUT ;
    USE SIGNAL ;
    PORT
      LAYER M5 ;
        RECT  11.76 23.676 11.784 23.76 ;
    END
  END i[367]
  PIN i[368]
    DIRECTION INPUT ;
    USE SIGNAL ;
    PORT
      LAYER M5 ;
        RECT  11.856 23.676 11.88 23.76 ;
    END
  END i[368]
  PIN i[369]
    DIRECTION INPUT ;
    USE SIGNAL ;
    PORT
      LAYER M5 ;
        RECT  11.952 23.676 11.976 23.76 ;
    END
  END i[369]
  PIN i[36]
    DIRECTION INPUT ;
    USE SIGNAL ;
    PORT
      LAYER M5 ;
        RECT  32.976 23.676 33 23.76 ;
    END
  END i[36]
  PIN i[370]
    DIRECTION INPUT ;
    USE SIGNAL ;
    PORT
      LAYER M5 ;
        RECT  12.048 23.676 12.072 23.76 ;
    END
  END i[370]
  PIN i[371]
    DIRECTION INPUT ;
    USE SIGNAL ;
    PORT
      LAYER M5 ;
        RECT  12.144 23.676 12.168 23.76 ;
    END
  END i[371]
  PIN i[372]
    DIRECTION INPUT ;
    USE SIGNAL ;
    PORT
      LAYER M5 ;
        RECT  12.24 23.676 12.264 23.76 ;
    END
  END i[372]
  PIN i[373]
    DIRECTION INPUT ;
    USE SIGNAL ;
    PORT
      LAYER M5 ;
        RECT  12.336 23.676 12.36 23.76 ;
    END
  END i[373]
  PIN i[374]
    DIRECTION INPUT ;
    USE SIGNAL ;
    PORT
      LAYER M5 ;
        RECT  12.432 23.676 12.456 23.76 ;
    END
  END i[374]
  PIN i[375]
    DIRECTION INPUT ;
    USE SIGNAL ;
    PORT
      LAYER M5 ;
        RECT  12.528 23.676 12.552 23.76 ;
    END
  END i[375]
  PIN i[376]
    DIRECTION INPUT ;
    USE SIGNAL ;
    PORT
      LAYER M5 ;
        RECT  12.624 23.676 12.648 23.76 ;
    END
  END i[376]
  PIN i[377]
    DIRECTION INPUT ;
    USE SIGNAL ;
    PORT
      LAYER M5 ;
        RECT  12.72 23.676 12.744 23.76 ;
    END
  END i[377]
  PIN i[378]
    DIRECTION INPUT ;
    USE SIGNAL ;
    PORT
      LAYER M5 ;
        RECT  12.816 23.676 12.84 23.76 ;
    END
  END i[378]
  PIN i[379]
    DIRECTION INPUT ;
    USE SIGNAL ;
    PORT
      LAYER M5 ;
        RECT  12.912 23.676 12.936 23.76 ;
    END
  END i[379]
  PIN i[37]
    DIRECTION INPUT ;
    USE SIGNAL ;
    PORT
      LAYER M5 ;
        RECT  33.072 23.676 33.096 23.76 ;
    END
  END i[37]
  PIN i[380]
    DIRECTION INPUT ;
    USE SIGNAL ;
    PORT
      LAYER M5 ;
        RECT  13.008 23.676 13.032 23.76 ;
    END
  END i[380]
  PIN i[381]
    DIRECTION INPUT ;
    USE SIGNAL ;
    PORT
      LAYER M5 ;
        RECT  13.104 23.676 13.128 23.76 ;
    END
  END i[381]
  PIN i[382]
    DIRECTION INPUT ;
    USE SIGNAL ;
    PORT
      LAYER M5 ;
        RECT  13.2 23.676 13.224 23.76 ;
    END
  END i[382]
  PIN i[383]
    DIRECTION INPUT ;
    USE SIGNAL ;
    PORT
      LAYER M5 ;
        RECT  13.296 23.676 13.32 23.76 ;
    END
  END i[383]
  PIN i[384]
    DIRECTION INPUT ;
    USE SIGNAL ;
    PORT
      LAYER M5 ;
        RECT  3.408 23.676 3.432 23.76 ;
    END
  END i[384]
  PIN i[385]
    DIRECTION INPUT ;
    USE SIGNAL ;
    PORT
      LAYER M5 ;
        RECT  3.504 23.676 3.528 23.76 ;
    END
  END i[385]
  PIN i[386]
    DIRECTION INPUT ;
    USE SIGNAL ;
    PORT
      LAYER M5 ;
        RECT  3.6 23.676 3.624 23.76 ;
    END
  END i[386]
  PIN i[387]
    DIRECTION INPUT ;
    USE SIGNAL ;
    PORT
      LAYER M5 ;
        RECT  3.696 23.676 3.72 23.76 ;
    END
  END i[387]
  PIN i[388]
    DIRECTION INPUT ;
    USE SIGNAL ;
    PORT
      LAYER M5 ;
        RECT  3.792 23.676 3.816 23.76 ;
    END
  END i[388]
  PIN i[389]
    DIRECTION INPUT ;
    USE SIGNAL ;
    PORT
      LAYER M5 ;
        RECT  3.888 23.676 3.912 23.76 ;
    END
  END i[389]
  PIN i[38]
    DIRECTION INPUT ;
    USE SIGNAL ;
    PORT
      LAYER M5 ;
        RECT  33.168 23.676 33.192 23.76 ;
    END
  END i[38]
  PIN i[390]
    DIRECTION INPUT ;
    USE SIGNAL ;
    PORT
      LAYER M5 ;
        RECT  3.984 23.676 4.008 23.76 ;
    END
  END i[390]
  PIN i[391]
    DIRECTION INPUT ;
    USE SIGNAL ;
    PORT
      LAYER M5 ;
        RECT  4.08 23.676 4.104 23.76 ;
    END
  END i[391]
  PIN i[392]
    DIRECTION INPUT ;
    USE SIGNAL ;
    PORT
      LAYER M5 ;
        RECT  4.176 23.676 4.2 23.76 ;
    END
  END i[392]
  PIN i[393]
    DIRECTION INPUT ;
    USE SIGNAL ;
    PORT
      LAYER M5 ;
        RECT  4.272 23.676 4.296 23.76 ;
    END
  END i[393]
  PIN i[394]
    DIRECTION INPUT ;
    USE SIGNAL ;
    PORT
      LAYER M5 ;
        RECT  4.368 23.676 4.392 23.76 ;
    END
  END i[394]
  PIN i[395]
    DIRECTION INPUT ;
    USE SIGNAL ;
    PORT
      LAYER M5 ;
        RECT  4.464 23.676 4.488 23.76 ;
    END
  END i[395]
  PIN i[396]
    DIRECTION INPUT ;
    USE SIGNAL ;
    PORT
      LAYER M5 ;
        RECT  4.56 23.676 4.584 23.76 ;
    END
  END i[396]
  PIN i[397]
    DIRECTION INPUT ;
    USE SIGNAL ;
    PORT
      LAYER M5 ;
        RECT  4.656 23.676 4.68 23.76 ;
    END
  END i[397]
  PIN i[398]
    DIRECTION INPUT ;
    USE SIGNAL ;
    PORT
      LAYER M5 ;
        RECT  4.752 23.676 4.776 23.76 ;
    END
  END i[398]
  PIN i[399]
    DIRECTION INPUT ;
    USE SIGNAL ;
    PORT
      LAYER M5 ;
        RECT  4.848 23.676 4.872 23.76 ;
    END
  END i[399]
  PIN i[39]
    DIRECTION INPUT ;
    USE SIGNAL ;
    PORT
      LAYER M5 ;
        RECT  33.264 23.676 33.288 23.76 ;
    END
  END i[39]
  PIN i[3]
    DIRECTION INPUT ;
    USE SIGNAL ;
    PORT
      LAYER M5 ;
        RECT  42.096 23.676 42.12 23.76 ;
    END
  END i[3]
  PIN i[400]
    DIRECTION INPUT ;
    USE SIGNAL ;
    PORT
      LAYER M5 ;
        RECT  4.944 23.676 4.968 23.76 ;
    END
  END i[400]
  PIN i[401]
    DIRECTION INPUT ;
    USE SIGNAL ;
    PORT
      LAYER M5 ;
        RECT  5.04 23.676 5.064 23.76 ;
    END
  END i[401]
  PIN i[402]
    DIRECTION INPUT ;
    USE SIGNAL ;
    PORT
      LAYER M5 ;
        RECT  5.136 23.676 5.16 23.76 ;
    END
  END i[402]
  PIN i[403]
    DIRECTION INPUT ;
    USE SIGNAL ;
    PORT
      LAYER M5 ;
        RECT  5.232 23.676 5.256 23.76 ;
    END
  END i[403]
  PIN i[404]
    DIRECTION INPUT ;
    USE SIGNAL ;
    PORT
      LAYER M5 ;
        RECT  5.328 23.676 5.352 23.76 ;
    END
  END i[404]
  PIN i[405]
    DIRECTION INPUT ;
    USE SIGNAL ;
    PORT
      LAYER M5 ;
        RECT  5.424 23.676 5.448 23.76 ;
    END
  END i[405]
  PIN i[406]
    DIRECTION INPUT ;
    USE SIGNAL ;
    PORT
      LAYER M5 ;
        RECT  5.52 23.676 5.544 23.76 ;
    END
  END i[406]
  PIN i[407]
    DIRECTION INPUT ;
    USE SIGNAL ;
    PORT
      LAYER M5 ;
        RECT  5.616 23.676 5.64 23.76 ;
    END
  END i[407]
  PIN i[408]
    DIRECTION INPUT ;
    USE SIGNAL ;
    PORT
      LAYER M5 ;
        RECT  5.712 23.676 5.736 23.76 ;
    END
  END i[408]
  PIN i[409]
    DIRECTION INPUT ;
    USE SIGNAL ;
    PORT
      LAYER M5 ;
        RECT  5.808 23.676 5.832 23.76 ;
    END
  END i[409]
  PIN i[40]
    DIRECTION INPUT ;
    USE SIGNAL ;
    PORT
      LAYER M5 ;
        RECT  33.36 23.676 33.384 23.76 ;
    END
  END i[40]
  PIN i[410]
    DIRECTION INPUT ;
    USE SIGNAL ;
    PORT
      LAYER M5 ;
        RECT  5.904 23.676 5.928 23.76 ;
    END
  END i[410]
  PIN i[411]
    DIRECTION INPUT ;
    USE SIGNAL ;
    PORT
      LAYER M5 ;
        RECT  6 23.676 6.024 23.76 ;
    END
  END i[411]
  PIN i[412]
    DIRECTION INPUT ;
    USE SIGNAL ;
    PORT
      LAYER M5 ;
        RECT  6.096 23.676 6.12 23.76 ;
    END
  END i[412]
  PIN i[413]
    DIRECTION INPUT ;
    USE SIGNAL ;
    PORT
      LAYER M5 ;
        RECT  6.192 23.676 6.216 23.76 ;
    END
  END i[413]
  PIN i[414]
    DIRECTION INPUT ;
    USE SIGNAL ;
    PORT
      LAYER M5 ;
        RECT  6.288 23.676 6.312 23.76 ;
    END
  END i[414]
  PIN i[415]
    DIRECTION INPUT ;
    USE SIGNAL ;
    PORT
      LAYER M5 ;
        RECT  6.384 23.676 6.408 23.76 ;
    END
  END i[415]
  PIN i[416]
    DIRECTION INPUT ;
    USE SIGNAL ;
    PORT
      LAYER M5 ;
        RECT  54.864 23.676 54.888 23.76 ;
    END
  END i[416]
  PIN i[417]
    DIRECTION INPUT ;
    USE SIGNAL ;
    PORT
      LAYER M5 ;
        RECT  54.96 23.676 54.984 23.76 ;
    END
  END i[417]
  PIN i[418]
    DIRECTION INPUT ;
    USE SIGNAL ;
    PORT
      LAYER M5 ;
        RECT  55.056 23.676 55.08 23.76 ;
    END
  END i[418]
  PIN i[419]
    DIRECTION INPUT ;
    USE SIGNAL ;
    PORT
      LAYER M5 ;
        RECT  55.152 23.676 55.176 23.76 ;
    END
  END i[419]
  PIN i[41]
    DIRECTION INPUT ;
    USE SIGNAL ;
    PORT
      LAYER M5 ;
        RECT  33.456 23.676 33.48 23.76 ;
    END
  END i[41]
  PIN i[420]
    DIRECTION INPUT ;
    USE SIGNAL ;
    PORT
      LAYER M5 ;
        RECT  55.248 23.676 55.272 23.76 ;
    END
  END i[420]
  PIN i[421]
    DIRECTION INPUT ;
    USE SIGNAL ;
    PORT
      LAYER M5 ;
        RECT  55.344 23.676 55.368 23.76 ;
    END
  END i[421]
  PIN i[422]
    DIRECTION INPUT ;
    USE SIGNAL ;
    PORT
      LAYER M5 ;
        RECT  55.44 23.676 55.464 23.76 ;
    END
  END i[422]
  PIN i[423]
    DIRECTION INPUT ;
    USE SIGNAL ;
    PORT
      LAYER M5 ;
        RECT  55.536 23.676 55.56 23.76 ;
    END
  END i[423]
  PIN i[424]
    DIRECTION INPUT ;
    USE SIGNAL ;
    PORT
      LAYER M5 ;
        RECT  55.632 23.676 55.656 23.76 ;
    END
  END i[424]
  PIN i[425]
    DIRECTION INPUT ;
    USE SIGNAL ;
    PORT
      LAYER M5 ;
        RECT  55.728 23.676 55.752 23.76 ;
    END
  END i[425]
  PIN i[426]
    DIRECTION INPUT ;
    USE SIGNAL ;
    PORT
      LAYER M5 ;
        RECT  55.824 23.676 55.848 23.76 ;
    END
  END i[426]
  PIN i[427]
    DIRECTION INPUT ;
    USE SIGNAL ;
    PORT
      LAYER M5 ;
        RECT  55.92 23.676 55.944 23.76 ;
    END
  END i[427]
  PIN i[428]
    DIRECTION INPUT ;
    USE SIGNAL ;
    PORT
      LAYER M5 ;
        RECT  56.016 23.676 56.04 23.76 ;
    END
  END i[428]
  PIN i[429]
    DIRECTION INPUT ;
    USE SIGNAL ;
    PORT
      LAYER M5 ;
        RECT  56.112 23.676 56.136 23.76 ;
    END
  END i[429]
  PIN i[42]
    DIRECTION INPUT ;
    USE SIGNAL ;
    PORT
      LAYER M5 ;
        RECT  33.552 23.676 33.576 23.76 ;
    END
  END i[42]
  PIN i[430]
    DIRECTION INPUT ;
    USE SIGNAL ;
    PORT
      LAYER M5 ;
        RECT  56.208 23.676 56.232 23.76 ;
    END
  END i[430]
  PIN i[431]
    DIRECTION INPUT ;
    USE SIGNAL ;
    PORT
      LAYER M5 ;
        RECT  56.304 23.676 56.328 23.76 ;
    END
  END i[431]
  PIN i[432]
    DIRECTION INPUT ;
    USE SIGNAL ;
    PORT
      LAYER M5 ;
        RECT  56.4 23.676 56.424 23.76 ;
    END
  END i[432]
  PIN i[433]
    DIRECTION INPUT ;
    USE SIGNAL ;
    PORT
      LAYER M5 ;
        RECT  56.496 23.676 56.52 23.76 ;
    END
  END i[433]
  PIN i[434]
    DIRECTION INPUT ;
    USE SIGNAL ;
    PORT
      LAYER M5 ;
        RECT  56.592 23.676 56.616 23.76 ;
    END
  END i[434]
  PIN i[435]
    DIRECTION INPUT ;
    USE SIGNAL ;
    PORT
      LAYER M5 ;
        RECT  56.688 23.676 56.712 23.76 ;
    END
  END i[435]
  PIN i[436]
    DIRECTION INPUT ;
    USE SIGNAL ;
    PORT
      LAYER M5 ;
        RECT  56.784 23.676 56.808 23.76 ;
    END
  END i[436]
  PIN i[437]
    DIRECTION INPUT ;
    USE SIGNAL ;
    PORT
      LAYER M5 ;
        RECT  56.88 23.676 56.904 23.76 ;
    END
  END i[437]
  PIN i[438]
    DIRECTION INPUT ;
    USE SIGNAL ;
    PORT
      LAYER M5 ;
        RECT  56.976 23.676 57 23.76 ;
    END
  END i[438]
  PIN i[439]
    DIRECTION INPUT ;
    USE SIGNAL ;
    PORT
      LAYER M5 ;
        RECT  57.072 23.676 57.096 23.76 ;
    END
  END i[439]
  PIN i[43]
    DIRECTION INPUT ;
    USE SIGNAL ;
    PORT
      LAYER M5 ;
        RECT  33.648 23.676 33.672 23.76 ;
    END
  END i[43]
  PIN i[440]
    DIRECTION INPUT ;
    USE SIGNAL ;
    PORT
      LAYER M5 ;
        RECT  57.168 23.676 57.192 23.76 ;
    END
  END i[440]
  PIN i[441]
    DIRECTION INPUT ;
    USE SIGNAL ;
    PORT
      LAYER M5 ;
        RECT  57.264 23.676 57.288 23.76 ;
    END
  END i[441]
  PIN i[442]
    DIRECTION INPUT ;
    USE SIGNAL ;
    PORT
      LAYER M5 ;
        RECT  57.36 23.676 57.384 23.76 ;
    END
  END i[442]
  PIN i[443]
    DIRECTION INPUT ;
    USE SIGNAL ;
    PORT
      LAYER M5 ;
        RECT  57.456 23.676 57.48 23.76 ;
    END
  END i[443]
  PIN i[444]
    DIRECTION INPUT ;
    USE SIGNAL ;
    PORT
      LAYER M5 ;
        RECT  57.552 23.676 57.576 23.76 ;
    END
  END i[444]
  PIN i[445]
    DIRECTION INPUT ;
    USE SIGNAL ;
    PORT
      LAYER M5 ;
        RECT  57.648 23.676 57.672 23.76 ;
    END
  END i[445]
  PIN i[446]
    DIRECTION INPUT ;
    USE SIGNAL ;
    PORT
      LAYER M5 ;
        RECT  57.744 23.676 57.768 23.76 ;
    END
  END i[446]
  PIN i[447]
    DIRECTION INPUT ;
    USE SIGNAL ;
    PORT
      LAYER M5 ;
        RECT  57.84 23.676 57.864 23.76 ;
    END
  END i[447]
  PIN i[448]
    DIRECTION INPUT ;
    USE SIGNAL ;
    PORT
      LAYER M5 ;
        RECT  45.648 23.676 45.672 23.76 ;
    END
  END i[448]
  PIN i[449]
    DIRECTION INPUT ;
    USE SIGNAL ;
    PORT
      LAYER M5 ;
        RECT  45.744 23.676 45.768 23.76 ;
    END
  END i[449]
  PIN i[44]
    DIRECTION INPUT ;
    USE SIGNAL ;
    PORT
      LAYER M5 ;
        RECT  33.744 23.676 33.768 23.76 ;
    END
  END i[44]
  PIN i[450]
    DIRECTION INPUT ;
    USE SIGNAL ;
    PORT
      LAYER M5 ;
        RECT  45.84 23.676 45.864 23.76 ;
    END
  END i[450]
  PIN i[451]
    DIRECTION INPUT ;
    USE SIGNAL ;
    PORT
      LAYER M5 ;
        RECT  45.936 23.676 45.96 23.76 ;
    END
  END i[451]
  PIN i[452]
    DIRECTION INPUT ;
    USE SIGNAL ;
    PORT
      LAYER M5 ;
        RECT  46.032 23.676 46.056 23.76 ;
    END
  END i[452]
  PIN i[453]
    DIRECTION INPUT ;
    USE SIGNAL ;
    PORT
      LAYER M5 ;
        RECT  46.128 23.676 46.152 23.76 ;
    END
  END i[453]
  PIN i[454]
    DIRECTION INPUT ;
    USE SIGNAL ;
    PORT
      LAYER M5 ;
        RECT  46.224 23.676 46.248 23.76 ;
    END
  END i[454]
  PIN i[455]
    DIRECTION INPUT ;
    USE SIGNAL ;
    PORT
      LAYER M5 ;
        RECT  46.32 23.676 46.344 23.76 ;
    END
  END i[455]
  PIN i[456]
    DIRECTION INPUT ;
    USE SIGNAL ;
    PORT
      LAYER M5 ;
        RECT  46.416 23.676 46.44 23.76 ;
    END
  END i[456]
  PIN i[457]
    DIRECTION INPUT ;
    USE SIGNAL ;
    PORT
      LAYER M5 ;
        RECT  46.512 23.676 46.536 23.76 ;
    END
  END i[457]
  PIN i[458]
    DIRECTION INPUT ;
    USE SIGNAL ;
    PORT
      LAYER M5 ;
        RECT  46.608 23.676 46.632 23.76 ;
    END
  END i[458]
  PIN i[459]
    DIRECTION INPUT ;
    USE SIGNAL ;
    PORT
      LAYER M5 ;
        RECT  46.704 23.676 46.728 23.76 ;
    END
  END i[459]
  PIN i[45]
    DIRECTION INPUT ;
    USE SIGNAL ;
    PORT
      LAYER M5 ;
        RECT  33.84 23.676 33.864 23.76 ;
    END
  END i[45]
  PIN i[460]
    DIRECTION INPUT ;
    USE SIGNAL ;
    PORT
      LAYER M5 ;
        RECT  46.8 23.676 46.824 23.76 ;
    END
  END i[460]
  PIN i[461]
    DIRECTION INPUT ;
    USE SIGNAL ;
    PORT
      LAYER M5 ;
        RECT  46.896 23.676 46.92 23.76 ;
    END
  END i[461]
  PIN i[462]
    DIRECTION INPUT ;
    USE SIGNAL ;
    PORT
      LAYER M5 ;
        RECT  46.992 23.676 47.016 23.76 ;
    END
  END i[462]
  PIN i[463]
    DIRECTION INPUT ;
    USE SIGNAL ;
    PORT
      LAYER M5 ;
        RECT  47.088 23.676 47.112 23.76 ;
    END
  END i[463]
  PIN i[464]
    DIRECTION INPUT ;
    USE SIGNAL ;
    PORT
      LAYER M5 ;
        RECT  47.184 23.676 47.208 23.76 ;
    END
  END i[464]
  PIN i[465]
    DIRECTION INPUT ;
    USE SIGNAL ;
    PORT
      LAYER M5 ;
        RECT  47.28 23.676 47.304 23.76 ;
    END
  END i[465]
  PIN i[466]
    DIRECTION INPUT ;
    USE SIGNAL ;
    PORT
      LAYER M5 ;
        RECT  47.376 23.676 47.4 23.76 ;
    END
  END i[466]
  PIN i[467]
    DIRECTION INPUT ;
    USE SIGNAL ;
    PORT
      LAYER M5 ;
        RECT  47.472 23.676 47.496 23.76 ;
    END
  END i[467]
  PIN i[468]
    DIRECTION INPUT ;
    USE SIGNAL ;
    PORT
      LAYER M5 ;
        RECT  47.568 23.676 47.592 23.76 ;
    END
  END i[468]
  PIN i[469]
    DIRECTION INPUT ;
    USE SIGNAL ;
    PORT
      LAYER M5 ;
        RECT  47.664 23.676 47.688 23.76 ;
    END
  END i[469]
  PIN i[46]
    DIRECTION INPUT ;
    USE SIGNAL ;
    PORT
      LAYER M5 ;
        RECT  33.936 23.676 33.96 23.76 ;
    END
  END i[46]
  PIN i[470]
    DIRECTION INPUT ;
    USE SIGNAL ;
    PORT
      LAYER M5 ;
        RECT  47.76 23.676 47.784 23.76 ;
    END
  END i[470]
  PIN i[471]
    DIRECTION INPUT ;
    USE SIGNAL ;
    PORT
      LAYER M5 ;
        RECT  47.856 23.676 47.88 23.76 ;
    END
  END i[471]
  PIN i[472]
    DIRECTION INPUT ;
    USE SIGNAL ;
    PORT
      LAYER M5 ;
        RECT  47.952 23.676 47.976 23.76 ;
    END
  END i[472]
  PIN i[473]
    DIRECTION INPUT ;
    USE SIGNAL ;
    PORT
      LAYER M5 ;
        RECT  48.048 23.676 48.072 23.76 ;
    END
  END i[473]
  PIN i[474]
    DIRECTION INPUT ;
    USE SIGNAL ;
    PORT
      LAYER M5 ;
        RECT  48.144 23.676 48.168 23.76 ;
    END
  END i[474]
  PIN i[475]
    DIRECTION INPUT ;
    USE SIGNAL ;
    PORT
      LAYER M5 ;
        RECT  48.24 23.676 48.264 23.76 ;
    END
  END i[475]
  PIN i[476]
    DIRECTION INPUT ;
    USE SIGNAL ;
    PORT
      LAYER M5 ;
        RECT  48.336 23.676 48.36 23.76 ;
    END
  END i[476]
  PIN i[477]
    DIRECTION INPUT ;
    USE SIGNAL ;
    PORT
      LAYER M5 ;
        RECT  48.432 23.676 48.456 23.76 ;
    END
  END i[477]
  PIN i[478]
    DIRECTION INPUT ;
    USE SIGNAL ;
    PORT
      LAYER M5 ;
        RECT  48.528 23.676 48.552 23.76 ;
    END
  END i[478]
  PIN i[479]
    DIRECTION INPUT ;
    USE SIGNAL ;
    PORT
      LAYER M5 ;
        RECT  48.624 23.676 48.648 23.76 ;
    END
  END i[479]
  PIN i[47]
    DIRECTION INPUT ;
    USE SIGNAL ;
    PORT
      LAYER M5 ;
        RECT  34.032 23.676 34.056 23.76 ;
    END
  END i[47]
  PIN i[480]
    DIRECTION INPUT ;
    USE SIGNAL ;
    PORT
      LAYER M5 ;
        RECT  57.936 23.676 57.96 23.76 ;
    END
  END i[480]
  PIN i[481]
    DIRECTION INPUT ;
    USE SIGNAL ;
    PORT
      LAYER M5 ;
        RECT  58.032 23.676 58.056 23.76 ;
    END
  END i[481]
  PIN i[482]
    DIRECTION INPUT ;
    USE SIGNAL ;
    PORT
      LAYER M5 ;
        RECT  58.128 23.676 58.152 23.76 ;
    END
  END i[482]
  PIN i[483]
    DIRECTION INPUT ;
    USE SIGNAL ;
    PORT
      LAYER M5 ;
        RECT  58.224 23.676 58.248 23.76 ;
    END
  END i[483]
  PIN i[484]
    DIRECTION INPUT ;
    USE SIGNAL ;
    PORT
      LAYER M5 ;
        RECT  58.32 23.676 58.344 23.76 ;
    END
  END i[484]
  PIN i[485]
    DIRECTION INPUT ;
    USE SIGNAL ;
    PORT
      LAYER M5 ;
        RECT  58.416 23.676 58.44 23.76 ;
    END
  END i[485]
  PIN i[486]
    DIRECTION INPUT ;
    USE SIGNAL ;
    PORT
      LAYER M5 ;
        RECT  58.512 23.676 58.536 23.76 ;
    END
  END i[486]
  PIN i[487]
    DIRECTION INPUT ;
    USE SIGNAL ;
    PORT
      LAYER M5 ;
        RECT  58.608 23.676 58.632 23.76 ;
    END
  END i[487]
  PIN i[488]
    DIRECTION INPUT ;
    USE SIGNAL ;
    PORT
      LAYER M5 ;
        RECT  58.704 23.676 58.728 23.76 ;
    END
  END i[488]
  PIN i[489]
    DIRECTION INPUT ;
    USE SIGNAL ;
    PORT
      LAYER M5 ;
        RECT  58.8 23.676 58.824 23.76 ;
    END
  END i[489]
  PIN i[48]
    DIRECTION INPUT ;
    USE SIGNAL ;
    PORT
      LAYER M5 ;
        RECT  34.128 23.676 34.152 23.76 ;
    END
  END i[48]
  PIN i[490]
    DIRECTION INPUT ;
    USE SIGNAL ;
    PORT
      LAYER M5 ;
        RECT  58.896 23.676 58.92 23.76 ;
    END
  END i[490]
  PIN i[491]
    DIRECTION INPUT ;
    USE SIGNAL ;
    PORT
      LAYER M5 ;
        RECT  58.992 23.676 59.016 23.76 ;
    END
  END i[491]
  PIN i[492]
    DIRECTION INPUT ;
    USE SIGNAL ;
    PORT
      LAYER M5 ;
        RECT  59.088 23.676 59.112 23.76 ;
    END
  END i[492]
  PIN i[493]
    DIRECTION INPUT ;
    USE SIGNAL ;
    PORT
      LAYER M5 ;
        RECT  59.184 23.676 59.208 23.76 ;
    END
  END i[493]
  PIN i[494]
    DIRECTION INPUT ;
    USE SIGNAL ;
    PORT
      LAYER M5 ;
        RECT  59.28 23.676 59.304 23.76 ;
    END
  END i[494]
  PIN i[495]
    DIRECTION INPUT ;
    USE SIGNAL ;
    PORT
      LAYER M5 ;
        RECT  59.376 23.676 59.4 23.76 ;
    END
  END i[495]
  PIN i[496]
    DIRECTION INPUT ;
    USE SIGNAL ;
    PORT
      LAYER M5 ;
        RECT  59.472 23.676 59.496 23.76 ;
    END
  END i[496]
  PIN i[497]
    DIRECTION INPUT ;
    USE SIGNAL ;
    PORT
      LAYER M5 ;
        RECT  59.568 23.676 59.592 23.76 ;
    END
  END i[497]
  PIN i[498]
    DIRECTION INPUT ;
    USE SIGNAL ;
    PORT
      LAYER M5 ;
        RECT  59.664 23.676 59.688 23.76 ;
    END
  END i[498]
  PIN i[499]
    DIRECTION INPUT ;
    USE SIGNAL ;
    PORT
      LAYER M5 ;
        RECT  59.76 23.676 59.784 23.76 ;
    END
  END i[499]
  PIN i[49]
    DIRECTION INPUT ;
    USE SIGNAL ;
    PORT
      LAYER M5 ;
        RECT  34.224 23.676 34.248 23.76 ;
    END
  END i[49]
  PIN i[4]
    DIRECTION INPUT ;
    USE SIGNAL ;
    PORT
      LAYER M5 ;
        RECT  42.192 23.676 42.216 23.76 ;
    END
  END i[4]
  PIN i[500]
    DIRECTION INPUT ;
    USE SIGNAL ;
    PORT
      LAYER M5 ;
        RECT  59.856 23.676 59.88 23.76 ;
    END
  END i[500]
  PIN i[501]
    DIRECTION INPUT ;
    USE SIGNAL ;
    PORT
      LAYER M5 ;
        RECT  59.952 23.676 59.976 23.76 ;
    END
  END i[501]
  PIN i[502]
    DIRECTION INPUT ;
    USE SIGNAL ;
    PORT
      LAYER M5 ;
        RECT  60.048 23.676 60.072 23.76 ;
    END
  END i[502]
  PIN i[503]
    DIRECTION INPUT ;
    USE SIGNAL ;
    PORT
      LAYER M5 ;
        RECT  60.144 23.676 60.168 23.76 ;
    END
  END i[503]
  PIN i[504]
    DIRECTION INPUT ;
    USE SIGNAL ;
    PORT
      LAYER M5 ;
        RECT  60.24 23.676 60.264 23.76 ;
    END
  END i[504]
  PIN i[505]
    DIRECTION INPUT ;
    USE SIGNAL ;
    PORT
      LAYER M5 ;
        RECT  60.336 23.676 60.36 23.76 ;
    END
  END i[505]
  PIN i[506]
    DIRECTION INPUT ;
    USE SIGNAL ;
    PORT
      LAYER M5 ;
        RECT  60.432 23.676 60.456 23.76 ;
    END
  END i[506]
  PIN i[507]
    DIRECTION INPUT ;
    USE SIGNAL ;
    PORT
      LAYER M5 ;
        RECT  60.528 23.676 60.552 23.76 ;
    END
  END i[507]
  PIN i[508]
    DIRECTION INPUT ;
    USE SIGNAL ;
    PORT
      LAYER M5 ;
        RECT  60.624 23.676 60.648 23.76 ;
    END
  END i[508]
  PIN i[509]
    DIRECTION INPUT ;
    USE SIGNAL ;
    PORT
      LAYER M5 ;
        RECT  60.72 23.676 60.744 23.76 ;
    END
  END i[509]
  PIN i[50]
    DIRECTION INPUT ;
    USE SIGNAL ;
    PORT
      LAYER M5 ;
        RECT  34.32 23.676 34.344 23.76 ;
    END
  END i[50]
  PIN i[510]
    DIRECTION INPUT ;
    USE SIGNAL ;
    PORT
      LAYER M5 ;
        RECT  60.816 23.676 60.84 23.76 ;
    END
  END i[510]
  PIN i[511]
    DIRECTION INPUT ;
    USE SIGNAL ;
    PORT
      LAYER M5 ;
        RECT  60.912 23.676 60.936 23.76 ;
    END
  END i[511]
  PIN i[512]
    DIRECTION INPUT ;
    USE SIGNAL ;
    PORT
      LAYER M5 ;
        RECT  51.792 23.676 51.816 23.76 ;
    END
  END i[512]
  PIN i[513]
    DIRECTION INPUT ;
    USE SIGNAL ;
    PORT
      LAYER M5 ;
        RECT  51.888 23.676 51.912 23.76 ;
    END
  END i[513]
  PIN i[514]
    DIRECTION INPUT ;
    USE SIGNAL ;
    PORT
      LAYER M5 ;
        RECT  51.984 23.676 52.008 23.76 ;
    END
  END i[514]
  PIN i[515]
    DIRECTION INPUT ;
    USE SIGNAL ;
    PORT
      LAYER M5 ;
        RECT  52.08 23.676 52.104 23.76 ;
    END
  END i[515]
  PIN i[516]
    DIRECTION INPUT ;
    USE SIGNAL ;
    PORT
      LAYER M5 ;
        RECT  52.176 23.676 52.2 23.76 ;
    END
  END i[516]
  PIN i[517]
    DIRECTION INPUT ;
    USE SIGNAL ;
    PORT
      LAYER M5 ;
        RECT  52.272 23.676 52.296 23.76 ;
    END
  END i[517]
  PIN i[518]
    DIRECTION INPUT ;
    USE SIGNAL ;
    PORT
      LAYER M5 ;
        RECT  52.368 23.676 52.392 23.76 ;
    END
  END i[518]
  PIN i[519]
    DIRECTION INPUT ;
    USE SIGNAL ;
    PORT
      LAYER M5 ;
        RECT  52.464 23.676 52.488 23.76 ;
    END
  END i[519]
  PIN i[51]
    DIRECTION INPUT ;
    USE SIGNAL ;
    PORT
      LAYER M5 ;
        RECT  34.416 23.676 34.44 23.76 ;
    END
  END i[51]
  PIN i[520]
    DIRECTION INPUT ;
    USE SIGNAL ;
    PORT
      LAYER M5 ;
        RECT  52.56 23.676 52.584 23.76 ;
    END
  END i[520]
  PIN i[521]
    DIRECTION INPUT ;
    USE SIGNAL ;
    PORT
      LAYER M5 ;
        RECT  52.656 23.676 52.68 23.76 ;
    END
  END i[521]
  PIN i[522]
    DIRECTION INPUT ;
    USE SIGNAL ;
    PORT
      LAYER M5 ;
        RECT  52.752 23.676 52.776 23.76 ;
    END
  END i[522]
  PIN i[523]
    DIRECTION INPUT ;
    USE SIGNAL ;
    PORT
      LAYER M5 ;
        RECT  52.848 23.676 52.872 23.76 ;
    END
  END i[523]
  PIN i[524]
    DIRECTION INPUT ;
    USE SIGNAL ;
    PORT
      LAYER M5 ;
        RECT  52.944 23.676 52.968 23.76 ;
    END
  END i[524]
  PIN i[525]
    DIRECTION INPUT ;
    USE SIGNAL ;
    PORT
      LAYER M5 ;
        RECT  53.04 23.676 53.064 23.76 ;
    END
  END i[525]
  PIN i[526]
    DIRECTION INPUT ;
    USE SIGNAL ;
    PORT
      LAYER M5 ;
        RECT  53.136 23.676 53.16 23.76 ;
    END
  END i[526]
  PIN i[527]
    DIRECTION INPUT ;
    USE SIGNAL ;
    PORT
      LAYER M5 ;
        RECT  53.232 23.676 53.256 23.76 ;
    END
  END i[527]
  PIN i[528]
    DIRECTION INPUT ;
    USE SIGNAL ;
    PORT
      LAYER M5 ;
        RECT  53.328 23.676 53.352 23.76 ;
    END
  END i[528]
  PIN i[529]
    DIRECTION INPUT ;
    USE SIGNAL ;
    PORT
      LAYER M5 ;
        RECT  53.424 23.676 53.448 23.76 ;
    END
  END i[529]
  PIN i[52]
    DIRECTION INPUT ;
    USE SIGNAL ;
    PORT
      LAYER M5 ;
        RECT  34.512 23.676 34.536 23.76 ;
    END
  END i[52]
  PIN i[530]
    DIRECTION INPUT ;
    USE SIGNAL ;
    PORT
      LAYER M5 ;
        RECT  53.52 23.676 53.544 23.76 ;
    END
  END i[530]
  PIN i[531]
    DIRECTION INPUT ;
    USE SIGNAL ;
    PORT
      LAYER M5 ;
        RECT  53.616 23.676 53.64 23.76 ;
    END
  END i[531]
  PIN i[532]
    DIRECTION INPUT ;
    USE SIGNAL ;
    PORT
      LAYER M5 ;
        RECT  53.712 23.676 53.736 23.76 ;
    END
  END i[532]
  PIN i[533]
    DIRECTION INPUT ;
    USE SIGNAL ;
    PORT
      LAYER M5 ;
        RECT  53.808 23.676 53.832 23.76 ;
    END
  END i[533]
  PIN i[534]
    DIRECTION INPUT ;
    USE SIGNAL ;
    PORT
      LAYER M5 ;
        RECT  53.904 23.676 53.928 23.76 ;
    END
  END i[534]
  PIN i[535]
    DIRECTION INPUT ;
    USE SIGNAL ;
    PORT
      LAYER M5 ;
        RECT  54 23.676 54.024 23.76 ;
    END
  END i[535]
  PIN i[536]
    DIRECTION INPUT ;
    USE SIGNAL ;
    PORT
      LAYER M5 ;
        RECT  54.096 23.676 54.12 23.76 ;
    END
  END i[536]
  PIN i[537]
    DIRECTION INPUT ;
    USE SIGNAL ;
    PORT
      LAYER M5 ;
        RECT  54.192 23.676 54.216 23.76 ;
    END
  END i[537]
  PIN i[538]
    DIRECTION INPUT ;
    USE SIGNAL ;
    PORT
      LAYER M5 ;
        RECT  54.288 23.676 54.312 23.76 ;
    END
  END i[538]
  PIN i[539]
    DIRECTION INPUT ;
    USE SIGNAL ;
    PORT
      LAYER M5 ;
        RECT  54.384 23.676 54.408 23.76 ;
    END
  END i[539]
  PIN i[53]
    DIRECTION INPUT ;
    USE SIGNAL ;
    PORT
      LAYER M5 ;
        RECT  34.608 23.676 34.632 23.76 ;
    END
  END i[53]
  PIN i[540]
    DIRECTION INPUT ;
    USE SIGNAL ;
    PORT
      LAYER M5 ;
        RECT  54.48 23.676 54.504 23.76 ;
    END
  END i[540]
  PIN i[541]
    DIRECTION INPUT ;
    USE SIGNAL ;
    PORT
      LAYER M5 ;
        RECT  54.576 23.676 54.6 23.76 ;
    END
  END i[541]
  PIN i[542]
    DIRECTION INPUT ;
    USE SIGNAL ;
    PORT
      LAYER M5 ;
        RECT  54.672 23.676 54.696 23.76 ;
    END
  END i[542]
  PIN i[543]
    DIRECTION INPUT ;
    USE SIGNAL ;
    PORT
      LAYER M5 ;
        RECT  54.768 23.676 54.792 23.76 ;
    END
  END i[543]
  PIN i[544]
    DIRECTION INPUT ;
    USE SIGNAL ;
    PORT
      LAYER M5 ;
        RECT  61.008 23.676 61.032 23.76 ;
    END
  END i[544]
  PIN i[545]
    DIRECTION INPUT ;
    USE SIGNAL ;
    PORT
      LAYER M5 ;
        RECT  61.104 23.676 61.128 23.76 ;
    END
  END i[545]
  PIN i[546]
    DIRECTION INPUT ;
    USE SIGNAL ;
    PORT
      LAYER M5 ;
        RECT  61.2 23.676 61.224 23.76 ;
    END
  END i[546]
  PIN i[547]
    DIRECTION INPUT ;
    USE SIGNAL ;
    PORT
      LAYER M5 ;
        RECT  61.296 23.676 61.32 23.76 ;
    END
  END i[547]
  PIN i[548]
    DIRECTION INPUT ;
    USE SIGNAL ;
    PORT
      LAYER M5 ;
        RECT  61.392 23.676 61.416 23.76 ;
    END
  END i[548]
  PIN i[549]
    DIRECTION INPUT ;
    USE SIGNAL ;
    PORT
      LAYER M5 ;
        RECT  61.488 23.676 61.512 23.76 ;
    END
  END i[549]
  PIN i[54]
    DIRECTION INPUT ;
    USE SIGNAL ;
    PORT
      LAYER M5 ;
        RECT  34.704 23.676 34.728 23.76 ;
    END
  END i[54]
  PIN i[550]
    DIRECTION INPUT ;
    USE SIGNAL ;
    PORT
      LAYER M5 ;
        RECT  61.584 23.676 61.608 23.76 ;
    END
  END i[550]
  PIN i[551]
    DIRECTION INPUT ;
    USE SIGNAL ;
    PORT
      LAYER M5 ;
        RECT  61.68 23.676 61.704 23.76 ;
    END
  END i[551]
  PIN i[552]
    DIRECTION INPUT ;
    USE SIGNAL ;
    PORT
      LAYER M5 ;
        RECT  61.776 23.676 61.8 23.76 ;
    END
  END i[552]
  PIN i[553]
    DIRECTION INPUT ;
    USE SIGNAL ;
    PORT
      LAYER M5 ;
        RECT  61.872 23.676 61.896 23.76 ;
    END
  END i[553]
  PIN i[554]
    DIRECTION INPUT ;
    USE SIGNAL ;
    PORT
      LAYER M5 ;
        RECT  61.968 23.676 61.992 23.76 ;
    END
  END i[554]
  PIN i[555]
    DIRECTION INPUT ;
    USE SIGNAL ;
    PORT
      LAYER M5 ;
        RECT  62.064 23.676 62.088 23.76 ;
    END
  END i[555]
  PIN i[556]
    DIRECTION INPUT ;
    USE SIGNAL ;
    PORT
      LAYER M5 ;
        RECT  62.16 23.676 62.184 23.76 ;
    END
  END i[556]
  PIN i[557]
    DIRECTION INPUT ;
    USE SIGNAL ;
    PORT
      LAYER M5 ;
        RECT  62.256 23.676 62.28 23.76 ;
    END
  END i[557]
  PIN i[558]
    DIRECTION INPUT ;
    USE SIGNAL ;
    PORT
      LAYER M5 ;
        RECT  62.352 23.676 62.376 23.76 ;
    END
  END i[558]
  PIN i[559]
    DIRECTION INPUT ;
    USE SIGNAL ;
    PORT
      LAYER M5 ;
        RECT  62.448 23.676 62.472 23.76 ;
    END
  END i[559]
  PIN i[55]
    DIRECTION INPUT ;
    USE SIGNAL ;
    PORT
      LAYER M5 ;
        RECT  34.8 23.676 34.824 23.76 ;
    END
  END i[55]
  PIN i[560]
    DIRECTION INPUT ;
    USE SIGNAL ;
    PORT
      LAYER M5 ;
        RECT  62.544 23.676 62.568 23.76 ;
    END
  END i[560]
  PIN i[561]
    DIRECTION INPUT ;
    USE SIGNAL ;
    PORT
      LAYER M5 ;
        RECT  62.64 23.676 62.664 23.76 ;
    END
  END i[561]
  PIN i[562]
    DIRECTION INPUT ;
    USE SIGNAL ;
    PORT
      LAYER M5 ;
        RECT  62.736 23.676 62.76 23.76 ;
    END
  END i[562]
  PIN i[563]
    DIRECTION INPUT ;
    USE SIGNAL ;
    PORT
      LAYER M5 ;
        RECT  62.832 23.676 62.856 23.76 ;
    END
  END i[563]
  PIN i[564]
    DIRECTION INPUT ;
    USE SIGNAL ;
    PORT
      LAYER M5 ;
        RECT  62.928 23.676 62.952 23.76 ;
    END
  END i[564]
  PIN i[565]
    DIRECTION INPUT ;
    USE SIGNAL ;
    PORT
      LAYER M5 ;
        RECT  63.024 23.676 63.048 23.76 ;
    END
  END i[565]
  PIN i[566]
    DIRECTION INPUT ;
    USE SIGNAL ;
    PORT
      LAYER M5 ;
        RECT  63.12 23.676 63.144 23.76 ;
    END
  END i[566]
  PIN i[567]
    DIRECTION INPUT ;
    USE SIGNAL ;
    PORT
      LAYER M5 ;
        RECT  63.216 23.676 63.24 23.76 ;
    END
  END i[567]
  PIN i[568]
    DIRECTION INPUT ;
    USE SIGNAL ;
    PORT
      LAYER M5 ;
        RECT  63.312 23.676 63.336 23.76 ;
    END
  END i[568]
  PIN i[569]
    DIRECTION INPUT ;
    USE SIGNAL ;
    PORT
      LAYER M5 ;
        RECT  63.408 23.676 63.432 23.76 ;
    END
  END i[569]
  PIN i[56]
    DIRECTION INPUT ;
    USE SIGNAL ;
    PORT
      LAYER M5 ;
        RECT  34.896 23.676 34.92 23.76 ;
    END
  END i[56]
  PIN i[570]
    DIRECTION INPUT ;
    USE SIGNAL ;
    PORT
      LAYER M5 ;
        RECT  63.504 23.676 63.528 23.76 ;
    END
  END i[570]
  PIN i[571]
    DIRECTION INPUT ;
    USE SIGNAL ;
    PORT
      LAYER M5 ;
        RECT  63.6 23.676 63.624 23.76 ;
    END
  END i[571]
  PIN i[572]
    DIRECTION INPUT ;
    USE SIGNAL ;
    PORT
      LAYER M5 ;
        RECT  63.696 23.676 63.72 23.76 ;
    END
  END i[572]
  PIN i[573]
    DIRECTION INPUT ;
    USE SIGNAL ;
    PORT
      LAYER M5 ;
        RECT  63.792 23.676 63.816 23.76 ;
    END
  END i[573]
  PIN i[574]
    DIRECTION INPUT ;
    USE SIGNAL ;
    PORT
      LAYER M5 ;
        RECT  63.888 23.676 63.912 23.76 ;
    END
  END i[574]
  PIN i[575]
    DIRECTION INPUT ;
    USE SIGNAL ;
    PORT
      LAYER M5 ;
        RECT  63.984 23.676 64.008 23.76 ;
    END
  END i[575]
  PIN i[576]
    DIRECTION INPUT ;
    USE SIGNAL ;
    PORT
      LAYER M5 ;
        RECT  48.72 23.676 48.744 23.76 ;
    END
  END i[576]
  PIN i[577]
    DIRECTION INPUT ;
    USE SIGNAL ;
    PORT
      LAYER M5 ;
        RECT  48.816 23.676 48.84 23.76 ;
    END
  END i[577]
  PIN i[578]
    DIRECTION INPUT ;
    USE SIGNAL ;
    PORT
      LAYER M5 ;
        RECT  48.912 23.676 48.936 23.76 ;
    END
  END i[578]
  PIN i[579]
    DIRECTION INPUT ;
    USE SIGNAL ;
    PORT
      LAYER M5 ;
        RECT  49.008 23.676 49.032 23.76 ;
    END
  END i[579]
  PIN i[57]
    DIRECTION INPUT ;
    USE SIGNAL ;
    PORT
      LAYER M5 ;
        RECT  34.992 23.676 35.016 23.76 ;
    END
  END i[57]
  PIN i[580]
    DIRECTION INPUT ;
    USE SIGNAL ;
    PORT
      LAYER M5 ;
        RECT  49.104 23.676 49.128 23.76 ;
    END
  END i[580]
  PIN i[581]
    DIRECTION INPUT ;
    USE SIGNAL ;
    PORT
      LAYER M5 ;
        RECT  49.2 23.676 49.224 23.76 ;
    END
  END i[581]
  PIN i[582]
    DIRECTION INPUT ;
    USE SIGNAL ;
    PORT
      LAYER M5 ;
        RECT  49.296 23.676 49.32 23.76 ;
    END
  END i[582]
  PIN i[583]
    DIRECTION INPUT ;
    USE SIGNAL ;
    PORT
      LAYER M5 ;
        RECT  49.392 23.676 49.416 23.76 ;
    END
  END i[583]
  PIN i[584]
    DIRECTION INPUT ;
    USE SIGNAL ;
    PORT
      LAYER M5 ;
        RECT  49.488 23.676 49.512 23.76 ;
    END
  END i[584]
  PIN i[585]
    DIRECTION INPUT ;
    USE SIGNAL ;
    PORT
      LAYER M5 ;
        RECT  49.584 23.676 49.608 23.76 ;
    END
  END i[585]
  PIN i[586]
    DIRECTION INPUT ;
    USE SIGNAL ;
    PORT
      LAYER M5 ;
        RECT  49.68 23.676 49.704 23.76 ;
    END
  END i[586]
  PIN i[587]
    DIRECTION INPUT ;
    USE SIGNAL ;
    PORT
      LAYER M5 ;
        RECT  49.776 23.676 49.8 23.76 ;
    END
  END i[587]
  PIN i[588]
    DIRECTION INPUT ;
    USE SIGNAL ;
    PORT
      LAYER M5 ;
        RECT  49.872 23.676 49.896 23.76 ;
    END
  END i[588]
  PIN i[589]
    DIRECTION INPUT ;
    USE SIGNAL ;
    PORT
      LAYER M5 ;
        RECT  49.968 23.676 49.992 23.76 ;
    END
  END i[589]
  PIN i[58]
    DIRECTION INPUT ;
    USE SIGNAL ;
    PORT
      LAYER M5 ;
        RECT  35.088 23.676 35.112 23.76 ;
    END
  END i[58]
  PIN i[590]
    DIRECTION INPUT ;
    USE SIGNAL ;
    PORT
      LAYER M5 ;
        RECT  50.064 23.676 50.088 23.76 ;
    END
  END i[590]
  PIN i[591]
    DIRECTION INPUT ;
    USE SIGNAL ;
    PORT
      LAYER M5 ;
        RECT  50.16 23.676 50.184 23.76 ;
    END
  END i[591]
  PIN i[592]
    DIRECTION INPUT ;
    USE SIGNAL ;
    PORT
      LAYER M5 ;
        RECT  50.256 23.676 50.28 23.76 ;
    END
  END i[592]
  PIN i[593]
    DIRECTION INPUT ;
    USE SIGNAL ;
    PORT
      LAYER M5 ;
        RECT  50.352 23.676 50.376 23.76 ;
    END
  END i[593]
  PIN i[594]
    DIRECTION INPUT ;
    USE SIGNAL ;
    PORT
      LAYER M5 ;
        RECT  50.448 23.676 50.472 23.76 ;
    END
  END i[594]
  PIN i[595]
    DIRECTION INPUT ;
    USE SIGNAL ;
    PORT
      LAYER M5 ;
        RECT  50.544 23.676 50.568 23.76 ;
    END
  END i[595]
  PIN i[596]
    DIRECTION INPUT ;
    USE SIGNAL ;
    PORT
      LAYER M5 ;
        RECT  50.64 23.676 50.664 23.76 ;
    END
  END i[596]
  PIN i[597]
    DIRECTION INPUT ;
    USE SIGNAL ;
    PORT
      LAYER M5 ;
        RECT  50.736 23.676 50.76 23.76 ;
    END
  END i[597]
  PIN i[598]
    DIRECTION INPUT ;
    USE SIGNAL ;
    PORT
      LAYER M5 ;
        RECT  50.832 23.676 50.856 23.76 ;
    END
  END i[598]
  PIN i[599]
    DIRECTION INPUT ;
    USE SIGNAL ;
    PORT
      LAYER M5 ;
        RECT  50.928 23.676 50.952 23.76 ;
    END
  END i[599]
  PIN i[59]
    DIRECTION INPUT ;
    USE SIGNAL ;
    PORT
      LAYER M5 ;
        RECT  35.184 23.676 35.208 23.76 ;
    END
  END i[59]
  PIN i[5]
    DIRECTION INPUT ;
    USE SIGNAL ;
    PORT
      LAYER M5 ;
        RECT  42.288 23.676 42.312 23.76 ;
    END
  END i[5]
  PIN i[600]
    DIRECTION INPUT ;
    USE SIGNAL ;
    PORT
      LAYER M5 ;
        RECT  51.024 23.676 51.048 23.76 ;
    END
  END i[600]
  PIN i[601]
    DIRECTION INPUT ;
    USE SIGNAL ;
    PORT
      LAYER M5 ;
        RECT  51.12 23.676 51.144 23.76 ;
    END
  END i[601]
  PIN i[602]
    DIRECTION INPUT ;
    USE SIGNAL ;
    PORT
      LAYER M5 ;
        RECT  51.216 23.676 51.24 23.76 ;
    END
  END i[602]
  PIN i[603]
    DIRECTION INPUT ;
    USE SIGNAL ;
    PORT
      LAYER M5 ;
        RECT  51.312 23.676 51.336 23.76 ;
    END
  END i[603]
  PIN i[604]
    DIRECTION INPUT ;
    USE SIGNAL ;
    PORT
      LAYER M5 ;
        RECT  51.408 23.676 51.432 23.76 ;
    END
  END i[604]
  PIN i[605]
    DIRECTION INPUT ;
    USE SIGNAL ;
    PORT
      LAYER M5 ;
        RECT  51.504 23.676 51.528 23.76 ;
    END
  END i[605]
  PIN i[606]
    DIRECTION INPUT ;
    USE SIGNAL ;
    PORT
      LAYER M5 ;
        RECT  51.6 23.676 51.624 23.76 ;
    END
  END i[606]
  PIN i[607]
    DIRECTION INPUT ;
    USE SIGNAL ;
    PORT
      LAYER M5 ;
        RECT  51.696 23.676 51.72 23.76 ;
    END
  END i[607]
  PIN i[608]
    DIRECTION INPUT ;
    USE SIGNAL ;
    PORT
      LAYER M5 ;
        RECT  1.776 23.676 1.8 23.76 ;
    END
  END i[608]
  PIN i[609]
    DIRECTION INPUT ;
    USE SIGNAL ;
    PORT
      LAYER M5 ;
        RECT  1.872 23.676 1.896 23.76 ;
    END
  END i[609]
  PIN i[60]
    DIRECTION INPUT ;
    USE SIGNAL ;
    PORT
      LAYER M5 ;
        RECT  35.28 23.676 35.304 23.76 ;
    END
  END i[60]
  PIN i[610]
    DIRECTION INPUT ;
    USE SIGNAL ;
    PORT
      LAYER M5 ;
        RECT  1.968 23.676 1.992 23.76 ;
    END
  END i[610]
  PIN i[611]
    DIRECTION INPUT ;
    USE SIGNAL ;
    PORT
      LAYER M5 ;
        RECT  2.064 23.676 2.088 23.76 ;
    END
  END i[611]
  PIN i[612]
    DIRECTION INPUT ;
    USE SIGNAL ;
    PORT
      LAYER M5 ;
        RECT  2.16 23.676 2.184 23.76 ;
    END
  END i[612]
  PIN i[613]
    DIRECTION INPUT ;
    USE SIGNAL ;
    PORT
      LAYER M5 ;
        RECT  2.256 23.676 2.28 23.76 ;
    END
  END i[613]
  PIN i[614]
    DIRECTION INPUT ;
    USE SIGNAL ;
    PORT
      LAYER M5 ;
        RECT  2.352 23.676 2.376 23.76 ;
    END
  END i[614]
  PIN i[615]
    DIRECTION INPUT ;
    USE SIGNAL ;
    PORT
      LAYER M5 ;
        RECT  2.448 23.676 2.472 23.76 ;
    END
  END i[615]
  PIN i[616]
    DIRECTION INPUT ;
    USE SIGNAL ;
    PORT
      LAYER M5 ;
        RECT  2.544 23.676 2.568 23.76 ;
    END
  END i[616]
  PIN i[617]
    DIRECTION INPUT ;
    USE SIGNAL ;
    PORT
      LAYER M5 ;
        RECT  2.64 23.676 2.664 23.76 ;
    END
  END i[617]
  PIN i[618]
    DIRECTION INPUT ;
    USE SIGNAL ;
    PORT
      LAYER M5 ;
        RECT  2.736 23.676 2.76 23.76 ;
    END
  END i[618]
  PIN i[619]
    DIRECTION INPUT ;
    USE SIGNAL ;
    PORT
      LAYER M5 ;
        RECT  2.832 23.676 2.856 23.76 ;
    END
  END i[619]
  PIN i[61]
    DIRECTION INPUT ;
    USE SIGNAL ;
    PORT
      LAYER M5 ;
        RECT  35.376 23.676 35.4 23.76 ;
    END
  END i[61]
  PIN i[620]
    DIRECTION INPUT ;
    USE SIGNAL ;
    PORT
      LAYER M5 ;
        RECT  2.928 23.676 2.952 23.76 ;
    END
  END i[620]
  PIN i[621]
    DIRECTION INPUT ;
    USE SIGNAL ;
    PORT
      LAYER M5 ;
        RECT  3.024 23.676 3.048 23.76 ;
    END
  END i[621]
  PIN i[622]
    DIRECTION INPUT ;
    USE SIGNAL ;
    PORT
      LAYER M5 ;
        RECT  3.12 23.676 3.144 23.76 ;
    END
  END i[622]
  PIN i[623]
    DIRECTION INPUT ;
    USE SIGNAL ;
    PORT
      LAYER M5 ;
        RECT  3.216 23.676 3.24 23.76 ;
    END
  END i[623]
  PIN i[62]
    DIRECTION INPUT ;
    USE SIGNAL ;
    PORT
      LAYER M5 ;
        RECT  35.472 23.676 35.496 23.76 ;
    END
  END i[62]
  PIN i[63]
    DIRECTION INPUT ;
    USE SIGNAL ;
    PORT
      LAYER M5 ;
        RECT  35.568 23.676 35.592 23.76 ;
    END
  END i[63]
  PIN i[64]
    DIRECTION INPUT ;
    USE SIGNAL ;
    PORT
      LAYER M5 ;
        RECT  38.736 23.676 38.76 23.76 ;
    END
  END i[64]
  PIN i[65]
    DIRECTION INPUT ;
    USE SIGNAL ;
    PORT
      LAYER M5 ;
        RECT  38.832 23.676 38.856 23.76 ;
    END
  END i[65]
  PIN i[66]
    DIRECTION INPUT ;
    USE SIGNAL ;
    PORT
      LAYER M5 ;
        RECT  38.928 23.676 38.952 23.76 ;
    END
  END i[66]
  PIN i[67]
    DIRECTION INPUT ;
    USE SIGNAL ;
    PORT
      LAYER M5 ;
        RECT  39.024 23.676 39.048 23.76 ;
    END
  END i[67]
  PIN i[68]
    DIRECTION INPUT ;
    USE SIGNAL ;
    PORT
      LAYER M5 ;
        RECT  39.12 23.676 39.144 23.76 ;
    END
  END i[68]
  PIN i[69]
    DIRECTION INPUT ;
    USE SIGNAL ;
    PORT
      LAYER M5 ;
        RECT  39.216 23.676 39.24 23.76 ;
    END
  END i[69]
  PIN i[6]
    DIRECTION INPUT ;
    USE SIGNAL ;
    PORT
      LAYER M5 ;
        RECT  42.384 23.676 42.408 23.76 ;
    END
  END i[6]
  PIN i[70]
    DIRECTION INPUT ;
    USE SIGNAL ;
    PORT
      LAYER M5 ;
        RECT  39.312 23.676 39.336 23.76 ;
    END
  END i[70]
  PIN i[71]
    DIRECTION INPUT ;
    USE SIGNAL ;
    PORT
      LAYER M5 ;
        RECT  39.408 23.676 39.432 23.76 ;
    END
  END i[71]
  PIN i[72]
    DIRECTION INPUT ;
    USE SIGNAL ;
    PORT
      LAYER M5 ;
        RECT  39.504 23.676 39.528 23.76 ;
    END
  END i[72]
  PIN i[73]
    DIRECTION INPUT ;
    USE SIGNAL ;
    PORT
      LAYER M5 ;
        RECT  39.6 23.676 39.624 23.76 ;
    END
  END i[73]
  PIN i[74]
    DIRECTION INPUT ;
    USE SIGNAL ;
    PORT
      LAYER M5 ;
        RECT  39.696 23.676 39.72 23.76 ;
    END
  END i[74]
  PIN i[75]
    DIRECTION INPUT ;
    USE SIGNAL ;
    PORT
      LAYER M5 ;
        RECT  39.792 23.676 39.816 23.76 ;
    END
  END i[75]
  PIN i[76]
    DIRECTION INPUT ;
    USE SIGNAL ;
    PORT
      LAYER M5 ;
        RECT  39.888 23.676 39.912 23.76 ;
    END
  END i[76]
  PIN i[77]
    DIRECTION INPUT ;
    USE SIGNAL ;
    PORT
      LAYER M5 ;
        RECT  39.984 23.676 40.008 23.76 ;
    END
  END i[77]
  PIN i[78]
    DIRECTION INPUT ;
    USE SIGNAL ;
    PORT
      LAYER M5 ;
        RECT  40.08 23.676 40.104 23.76 ;
    END
  END i[78]
  PIN i[79]
    DIRECTION INPUT ;
    USE SIGNAL ;
    PORT
      LAYER M5 ;
        RECT  40.176 23.676 40.2 23.76 ;
    END
  END i[79]
  PIN i[7]
    DIRECTION INPUT ;
    USE SIGNAL ;
    PORT
      LAYER M5 ;
        RECT  42.48 23.676 42.504 23.76 ;
    END
  END i[7]
  PIN i[80]
    DIRECTION INPUT ;
    USE SIGNAL ;
    PORT
      LAYER M5 ;
        RECT  40.272 23.676 40.296 23.76 ;
    END
  END i[80]
  PIN i[81]
    DIRECTION INPUT ;
    USE SIGNAL ;
    PORT
      LAYER M5 ;
        RECT  40.368 23.676 40.392 23.76 ;
    END
  END i[81]
  PIN i[82]
    DIRECTION INPUT ;
    USE SIGNAL ;
    PORT
      LAYER M5 ;
        RECT  40.464 23.676 40.488 23.76 ;
    END
  END i[82]
  PIN i[83]
    DIRECTION INPUT ;
    USE SIGNAL ;
    PORT
      LAYER M5 ;
        RECT  40.56 23.676 40.584 23.76 ;
    END
  END i[83]
  PIN i[84]
    DIRECTION INPUT ;
    USE SIGNAL ;
    PORT
      LAYER M5 ;
        RECT  40.656 23.676 40.68 23.76 ;
    END
  END i[84]
  PIN i[85]
    DIRECTION INPUT ;
    USE SIGNAL ;
    PORT
      LAYER M5 ;
        RECT  40.752 23.676 40.776 23.76 ;
    END
  END i[85]
  PIN i[86]
    DIRECTION INPUT ;
    USE SIGNAL ;
    PORT
      LAYER M5 ;
        RECT  40.848 23.676 40.872 23.76 ;
    END
  END i[86]
  PIN i[87]
    DIRECTION INPUT ;
    USE SIGNAL ;
    PORT
      LAYER M5 ;
        RECT  40.944 23.676 40.968 23.76 ;
    END
  END i[87]
  PIN i[88]
    DIRECTION INPUT ;
    USE SIGNAL ;
    PORT
      LAYER M5 ;
        RECT  41.04 23.676 41.064 23.76 ;
    END
  END i[88]
  PIN i[89]
    DIRECTION INPUT ;
    USE SIGNAL ;
    PORT
      LAYER M5 ;
        RECT  41.136 23.676 41.16 23.76 ;
    END
  END i[89]
  PIN i[8]
    DIRECTION INPUT ;
    USE SIGNAL ;
    PORT
      LAYER M5 ;
        RECT  42.576 23.676 42.6 23.76 ;
    END
  END i[8]
  PIN i[90]
    DIRECTION INPUT ;
    USE SIGNAL ;
    PORT
      LAYER M5 ;
        RECT  41.232 23.676 41.256 23.76 ;
    END
  END i[90]
  PIN i[91]
    DIRECTION INPUT ;
    USE SIGNAL ;
    PORT
      LAYER M5 ;
        RECT  41.328 23.676 41.352 23.76 ;
    END
  END i[91]
  PIN i[92]
    DIRECTION INPUT ;
    USE SIGNAL ;
    PORT
      LAYER M5 ;
        RECT  41.424 23.676 41.448 23.76 ;
    END
  END i[92]
  PIN i[93]
    DIRECTION INPUT ;
    USE SIGNAL ;
    PORT
      LAYER M5 ;
        RECT  41.52 23.676 41.544 23.76 ;
    END
  END i[93]
  PIN i[94]
    DIRECTION INPUT ;
    USE SIGNAL ;
    PORT
      LAYER M5 ;
        RECT  41.616 23.676 41.64 23.76 ;
    END
  END i[94]
  PIN i[95]
    DIRECTION INPUT ;
    USE SIGNAL ;
    PORT
      LAYER M5 ;
        RECT  41.712 23.676 41.736 23.76 ;
    END
  END i[95]
  PIN i[96]
    DIRECTION INPUT ;
    USE SIGNAL ;
    PORT
      LAYER M5 ;
        RECT  35.664 23.676 35.688 23.76 ;
    END
  END i[96]
  PIN i[97]
    DIRECTION INPUT ;
    USE SIGNAL ;
    PORT
      LAYER M5 ;
        RECT  35.76 23.676 35.784 23.76 ;
    END
  END i[97]
  PIN i[98]
    DIRECTION INPUT ;
    USE SIGNAL ;
    PORT
      LAYER M5 ;
        RECT  35.856 23.676 35.88 23.76 ;
    END
  END i[98]
  PIN i[99]
    DIRECTION INPUT ;
    USE SIGNAL ;
    PORT
      LAYER M5 ;
        RECT  35.952 23.676 35.976 23.76 ;
    END
  END i[99]
  PIN i[9]
    DIRECTION INPUT ;
    USE SIGNAL ;
    PORT
      LAYER M5 ;
        RECT  42.672 23.676 42.696 23.76 ;
    END
  END i[9]
  PIN o[0]
    DIRECTION OUTPUT ;
    USE SIGNAL ;
    PORT
      LAYER M5 ;
        RECT  35.28 0 35.304 0.084 ;
    END
  END o[0]
  PIN o[100]
    DIRECTION OUTPUT ;
    USE SIGNAL ;
    PORT
      LAYER M5 ;
        RECT  20.304 0 20.328 0.084 ;
    END
  END o[100]
  PIN o[101]
    DIRECTION OUTPUT ;
    USE SIGNAL ;
    PORT
      LAYER M5 ;
        RECT  20.4 0 20.424 0.084 ;
    END
  END o[101]
  PIN o[102]
    DIRECTION OUTPUT ;
    USE SIGNAL ;
    PORT
      LAYER M5 ;
        RECT  20.496 0 20.52 0.084 ;
    END
  END o[102]
  PIN o[103]
    DIRECTION OUTPUT ;
    USE SIGNAL ;
    PORT
      LAYER M5 ;
        RECT  20.592 0 20.616 0.084 ;
    END
  END o[103]
  PIN o[104]
    DIRECTION OUTPUT ;
    USE SIGNAL ;
    PORT
      LAYER M5 ;
        RECT  20.688 0 20.712 0.084 ;
    END
  END o[104]
  PIN o[105]
    DIRECTION OUTPUT ;
    USE SIGNAL ;
    PORT
      LAYER M5 ;
        RECT  20.784 0 20.808 0.084 ;
    END
  END o[105]
  PIN o[106]
    DIRECTION OUTPUT ;
    USE SIGNAL ;
    PORT
      LAYER M5 ;
        RECT  20.88 0 20.904 0.084 ;
    END
  END o[106]
  PIN o[107]
    DIRECTION OUTPUT ;
    USE SIGNAL ;
    PORT
      LAYER M5 ;
        RECT  20.976 0 21 0.084 ;
    END
  END o[107]
  PIN o[108]
    DIRECTION OUTPUT ;
    USE SIGNAL ;
    PORT
      LAYER M5 ;
        RECT  21.072 0 21.096 0.084 ;
    END
  END o[108]
  PIN o[109]
    DIRECTION OUTPUT ;
    USE SIGNAL ;
    PORT
      LAYER M5 ;
        RECT  21.168 0 21.192 0.084 ;
    END
  END o[109]
  PIN o[10]
    DIRECTION OUTPUT ;
    USE SIGNAL ;
    PORT
      LAYER M5 ;
        RECT  36.24 0 36.264 0.084 ;
    END
  END o[10]
  PIN o[110]
    DIRECTION OUTPUT ;
    USE SIGNAL ;
    PORT
      LAYER M5 ;
        RECT  21.264 0 21.288 0.084 ;
    END
  END o[110]
  PIN o[111]
    DIRECTION OUTPUT ;
    USE SIGNAL ;
    PORT
      LAYER M5 ;
        RECT  21.36 0 21.384 0.084 ;
    END
  END o[111]
  PIN o[112]
    DIRECTION OUTPUT ;
    USE SIGNAL ;
    PORT
      LAYER M5 ;
        RECT  21.456 0 21.48 0.084 ;
    END
  END o[112]
  PIN o[113]
    DIRECTION OUTPUT ;
    USE SIGNAL ;
    PORT
      LAYER M5 ;
        RECT  21.552 0 21.576 0.084 ;
    END
  END o[113]
  PIN o[114]
    DIRECTION OUTPUT ;
    USE SIGNAL ;
    PORT
      LAYER M5 ;
        RECT  21.648 0 21.672 0.084 ;
    END
  END o[114]
  PIN o[115]
    DIRECTION OUTPUT ;
    USE SIGNAL ;
    PORT
      LAYER M5 ;
        RECT  21.744 0 21.768 0.084 ;
    END
  END o[115]
  PIN o[116]
    DIRECTION OUTPUT ;
    USE SIGNAL ;
    PORT
      LAYER M5 ;
        RECT  21.84 0 21.864 0.084 ;
    END
  END o[116]
  PIN o[117]
    DIRECTION OUTPUT ;
    USE SIGNAL ;
    PORT
      LAYER M5 ;
        RECT  21.936 0 21.96 0.084 ;
    END
  END o[117]
  PIN o[118]
    DIRECTION OUTPUT ;
    USE SIGNAL ;
    PORT
      LAYER M5 ;
        RECT  22.032 0 22.056 0.084 ;
    END
  END o[118]
  PIN o[119]
    DIRECTION OUTPUT ;
    USE SIGNAL ;
    PORT
      LAYER M5 ;
        RECT  22.128 0 22.152 0.084 ;
    END
  END o[119]
  PIN o[11]
    DIRECTION OUTPUT ;
    USE SIGNAL ;
    PORT
      LAYER M5 ;
        RECT  36.336 0 36.36 0.084 ;
    END
  END o[11]
  PIN o[120]
    DIRECTION OUTPUT ;
    USE SIGNAL ;
    PORT
      LAYER M5 ;
        RECT  22.224 0 22.248 0.084 ;
    END
  END o[120]
  PIN o[121]
    DIRECTION OUTPUT ;
    USE SIGNAL ;
    PORT
      LAYER M5 ;
        RECT  22.32 0 22.344 0.084 ;
    END
  END o[121]
  PIN o[122]
    DIRECTION OUTPUT ;
    USE SIGNAL ;
    PORT
      LAYER M5 ;
        RECT  22.416 0 22.44 0.084 ;
    END
  END o[122]
  PIN o[123]
    DIRECTION OUTPUT ;
    USE SIGNAL ;
    PORT
      LAYER M5 ;
        RECT  22.512 0 22.536 0.084 ;
    END
  END o[123]
  PIN o[124]
    DIRECTION OUTPUT ;
    USE SIGNAL ;
    PORT
      LAYER M5 ;
        RECT  22.608 0 22.632 0.084 ;
    END
  END o[124]
  PIN o[125]
    DIRECTION OUTPUT ;
    USE SIGNAL ;
    PORT
      LAYER M5 ;
        RECT  22.704 0 22.728 0.084 ;
    END
  END o[125]
  PIN o[126]
    DIRECTION OUTPUT ;
    USE SIGNAL ;
    PORT
      LAYER M5 ;
        RECT  22.8 0 22.824 0.084 ;
    END
  END o[126]
  PIN o[127]
    DIRECTION OUTPUT ;
    USE SIGNAL ;
    PORT
      LAYER M5 ;
        RECT  22.896 0 22.92 0.084 ;
    END
  END o[127]
  PIN o[128]
    DIRECTION OUTPUT ;
    USE SIGNAL ;
    PORT
      LAYER M5 ;
        RECT  26.064 0 26.088 0.084 ;
    END
  END o[128]
  PIN o[129]
    DIRECTION OUTPUT ;
    USE SIGNAL ;
    PORT
      LAYER M5 ;
        RECT  26.16 0 26.184 0.084 ;
    END
  END o[129]
  PIN o[12]
    DIRECTION OUTPUT ;
    USE SIGNAL ;
    PORT
      LAYER M5 ;
        RECT  36.432 0 36.456 0.084 ;
    END
  END o[12]
  PIN o[130]
    DIRECTION OUTPUT ;
    USE SIGNAL ;
    PORT
      LAYER M5 ;
        RECT  26.256 0 26.28 0.084 ;
    END
  END o[130]
  PIN o[131]
    DIRECTION OUTPUT ;
    USE SIGNAL ;
    PORT
      LAYER M5 ;
        RECT  26.352 0 26.376 0.084 ;
    END
  END o[131]
  PIN o[132]
    DIRECTION OUTPUT ;
    USE SIGNAL ;
    PORT
      LAYER M5 ;
        RECT  26.448 0 26.472 0.084 ;
    END
  END o[132]
  PIN o[133]
    DIRECTION OUTPUT ;
    USE SIGNAL ;
    PORT
      LAYER M5 ;
        RECT  26.544 0 26.568 0.084 ;
    END
  END o[133]
  PIN o[134]
    DIRECTION OUTPUT ;
    USE SIGNAL ;
    PORT
      LAYER M5 ;
        RECT  26.64 0 26.664 0.084 ;
    END
  END o[134]
  PIN o[135]
    DIRECTION OUTPUT ;
    USE SIGNAL ;
    PORT
      LAYER M5 ;
        RECT  26.736 0 26.76 0.084 ;
    END
  END o[135]
  PIN o[136]
    DIRECTION OUTPUT ;
    USE SIGNAL ;
    PORT
      LAYER M5 ;
        RECT  26.832 0 26.856 0.084 ;
    END
  END o[136]
  PIN o[137]
    DIRECTION OUTPUT ;
    USE SIGNAL ;
    PORT
      LAYER M5 ;
        RECT  26.928 0 26.952 0.084 ;
    END
  END o[137]
  PIN o[138]
    DIRECTION OUTPUT ;
    USE SIGNAL ;
    PORT
      LAYER M5 ;
        RECT  27.024 0 27.048 0.084 ;
    END
  END o[138]
  PIN o[139]
    DIRECTION OUTPUT ;
    USE SIGNAL ;
    PORT
      LAYER M5 ;
        RECT  27.12 0 27.144 0.084 ;
    END
  END o[139]
  PIN o[13]
    DIRECTION OUTPUT ;
    USE SIGNAL ;
    PORT
      LAYER M5 ;
        RECT  36.528 0 36.552 0.084 ;
    END
  END o[13]
  PIN o[140]
    DIRECTION OUTPUT ;
    USE SIGNAL ;
    PORT
      LAYER M5 ;
        RECT  27.216 0 27.24 0.084 ;
    END
  END o[140]
  PIN o[141]
    DIRECTION OUTPUT ;
    USE SIGNAL ;
    PORT
      LAYER M5 ;
        RECT  27.312 0 27.336 0.084 ;
    END
  END o[141]
  PIN o[142]
    DIRECTION OUTPUT ;
    USE SIGNAL ;
    PORT
      LAYER M5 ;
        RECT  27.408 0 27.432 0.084 ;
    END
  END o[142]
  PIN o[143]
    DIRECTION OUTPUT ;
    USE SIGNAL ;
    PORT
      LAYER M5 ;
        RECT  27.504 0 27.528 0.084 ;
    END
  END o[143]
  PIN o[144]
    DIRECTION OUTPUT ;
    USE SIGNAL ;
    PORT
      LAYER M5 ;
        RECT  27.6 0 27.624 0.084 ;
    END
  END o[144]
  PIN o[145]
    DIRECTION OUTPUT ;
    USE SIGNAL ;
    PORT
      LAYER M5 ;
        RECT  27.696 0 27.72 0.084 ;
    END
  END o[145]
  PIN o[146]
    DIRECTION OUTPUT ;
    USE SIGNAL ;
    PORT
      LAYER M5 ;
        RECT  27.792 0 27.816 0.084 ;
    END
  END o[146]
  PIN o[147]
    DIRECTION OUTPUT ;
    USE SIGNAL ;
    PORT
      LAYER M5 ;
        RECT  27.888 0 27.912 0.084 ;
    END
  END o[147]
  PIN o[148]
    DIRECTION OUTPUT ;
    USE SIGNAL ;
    PORT
      LAYER M5 ;
        RECT  27.984 0 28.008 0.084 ;
    END
  END o[148]
  PIN o[149]
    DIRECTION OUTPUT ;
    USE SIGNAL ;
    PORT
      LAYER M5 ;
        RECT  28.08 0 28.104 0.084 ;
    END
  END o[149]
  PIN o[14]
    DIRECTION OUTPUT ;
    USE SIGNAL ;
    PORT
      LAYER M5 ;
        RECT  36.624 0 36.648 0.084 ;
    END
  END o[14]
  PIN o[150]
    DIRECTION OUTPUT ;
    USE SIGNAL ;
    PORT
      LAYER M5 ;
        RECT  28.176 0 28.2 0.084 ;
    END
  END o[150]
  PIN o[151]
    DIRECTION OUTPUT ;
    USE SIGNAL ;
    PORT
      LAYER M5 ;
        RECT  28.272 0 28.296 0.084 ;
    END
  END o[151]
  PIN o[152]
    DIRECTION OUTPUT ;
    USE SIGNAL ;
    PORT
      LAYER M5 ;
        RECT  28.368 0 28.392 0.084 ;
    END
  END o[152]
  PIN o[153]
    DIRECTION OUTPUT ;
    USE SIGNAL ;
    PORT
      LAYER M5 ;
        RECT  28.464 0 28.488 0.084 ;
    END
  END o[153]
  PIN o[154]
    DIRECTION OUTPUT ;
    USE SIGNAL ;
    PORT
      LAYER M5 ;
        RECT  28.56 0 28.584 0.084 ;
    END
  END o[154]
  PIN o[155]
    DIRECTION OUTPUT ;
    USE SIGNAL ;
    PORT
      LAYER M5 ;
        RECT  28.656 0 28.68 0.084 ;
    END
  END o[155]
  PIN o[156]
    DIRECTION OUTPUT ;
    USE SIGNAL ;
    PORT
      LAYER M5 ;
        RECT  28.752 0 28.776 0.084 ;
    END
  END o[156]
  PIN o[157]
    DIRECTION OUTPUT ;
    USE SIGNAL ;
    PORT
      LAYER M5 ;
        RECT  28.848 0 28.872 0.084 ;
    END
  END o[157]
  PIN o[158]
    DIRECTION OUTPUT ;
    USE SIGNAL ;
    PORT
      LAYER M5 ;
        RECT  28.944 0 28.968 0.084 ;
    END
  END o[158]
  PIN o[159]
    DIRECTION OUTPUT ;
    USE SIGNAL ;
    PORT
      LAYER M5 ;
        RECT  29.04 0 29.064 0.084 ;
    END
  END o[159]
  PIN o[15]
    DIRECTION OUTPUT ;
    USE SIGNAL ;
    PORT
      LAYER M5 ;
        RECT  36.72 0 36.744 0.084 ;
    END
  END o[15]
  PIN o[160]
    DIRECTION OUTPUT ;
    USE SIGNAL ;
    PORT
      LAYER M5 ;
        RECT  29.136 0 29.16 0.084 ;
    END
  END o[160]
  PIN o[161]
    DIRECTION OUTPUT ;
    USE SIGNAL ;
    PORT
      LAYER M5 ;
        RECT  29.232 0 29.256 0.084 ;
    END
  END o[161]
  PIN o[162]
    DIRECTION OUTPUT ;
    USE SIGNAL ;
    PORT
      LAYER M5 ;
        RECT  29.328 0 29.352 0.084 ;
    END
  END o[162]
  PIN o[163]
    DIRECTION OUTPUT ;
    USE SIGNAL ;
    PORT
      LAYER M5 ;
        RECT  29.424 0 29.448 0.084 ;
    END
  END o[163]
  PIN o[164]
    DIRECTION OUTPUT ;
    USE SIGNAL ;
    PORT
      LAYER M5 ;
        RECT  29.52 0 29.544 0.084 ;
    END
  END o[164]
  PIN o[165]
    DIRECTION OUTPUT ;
    USE SIGNAL ;
    PORT
      LAYER M5 ;
        RECT  29.616 0 29.64 0.084 ;
    END
  END o[165]
  PIN o[166]
    DIRECTION OUTPUT ;
    USE SIGNAL ;
    PORT
      LAYER M5 ;
        RECT  29.712 0 29.736 0.084 ;
    END
  END o[166]
  PIN o[167]
    DIRECTION OUTPUT ;
    USE SIGNAL ;
    PORT
      LAYER M5 ;
        RECT  29.808 0 29.832 0.084 ;
    END
  END o[167]
  PIN o[168]
    DIRECTION OUTPUT ;
    USE SIGNAL ;
    PORT
      LAYER M5 ;
        RECT  29.904 0 29.928 0.084 ;
    END
  END o[168]
  PIN o[169]
    DIRECTION OUTPUT ;
    USE SIGNAL ;
    PORT
      LAYER M5 ;
        RECT  30 0 30.024 0.084 ;
    END
  END o[169]
  PIN o[16]
    DIRECTION OUTPUT ;
    USE SIGNAL ;
    PORT
      LAYER M5 ;
        RECT  36.816 0 36.84 0.084 ;
    END
  END o[16]
  PIN o[170]
    DIRECTION OUTPUT ;
    USE SIGNAL ;
    PORT
      LAYER M5 ;
        RECT  30.096 0 30.12 0.084 ;
    END
  END o[170]
  PIN o[171]
    DIRECTION OUTPUT ;
    USE SIGNAL ;
    PORT
      LAYER M5 ;
        RECT  30.192 0 30.216 0.084 ;
    END
  END o[171]
  PIN o[172]
    DIRECTION OUTPUT ;
    USE SIGNAL ;
    PORT
      LAYER M5 ;
        RECT  30.288 0 30.312 0.084 ;
    END
  END o[172]
  PIN o[173]
    DIRECTION OUTPUT ;
    USE SIGNAL ;
    PORT
      LAYER M5 ;
        RECT  30.384 0 30.408 0.084 ;
    END
  END o[173]
  PIN o[174]
    DIRECTION OUTPUT ;
    USE SIGNAL ;
    PORT
      LAYER M5 ;
        RECT  30.48 0 30.504 0.084 ;
    END
  END o[174]
  PIN o[175]
    DIRECTION OUTPUT ;
    USE SIGNAL ;
    PORT
      LAYER M5 ;
        RECT  30.576 0 30.6 0.084 ;
    END
  END o[175]
  PIN o[176]
    DIRECTION OUTPUT ;
    USE SIGNAL ;
    PORT
      LAYER M5 ;
        RECT  30.672 0 30.696 0.084 ;
    END
  END o[176]
  PIN o[177]
    DIRECTION OUTPUT ;
    USE SIGNAL ;
    PORT
      LAYER M5 ;
        RECT  30.768 0 30.792 0.084 ;
    END
  END o[177]
  PIN o[178]
    DIRECTION OUTPUT ;
    USE SIGNAL ;
    PORT
      LAYER M5 ;
        RECT  30.864 0 30.888 0.084 ;
    END
  END o[178]
  PIN o[179]
    DIRECTION OUTPUT ;
    USE SIGNAL ;
    PORT
      LAYER M5 ;
        RECT  30.96 0 30.984 0.084 ;
    END
  END o[179]
  PIN o[17]
    DIRECTION OUTPUT ;
    USE SIGNAL ;
    PORT
      LAYER M5 ;
        RECT  36.912 0 36.936 0.084 ;
    END
  END o[17]
  PIN o[180]
    DIRECTION OUTPUT ;
    USE SIGNAL ;
    PORT
      LAYER M5 ;
        RECT  31.056 0 31.08 0.084 ;
    END
  END o[180]
  PIN o[181]
    DIRECTION OUTPUT ;
    USE SIGNAL ;
    PORT
      LAYER M5 ;
        RECT  31.152 0 31.176 0.084 ;
    END
  END o[181]
  PIN o[182]
    DIRECTION OUTPUT ;
    USE SIGNAL ;
    PORT
      LAYER M5 ;
        RECT  31.248 0 31.272 0.084 ;
    END
  END o[182]
  PIN o[183]
    DIRECTION OUTPUT ;
    USE SIGNAL ;
    PORT
      LAYER M5 ;
        RECT  31.344 0 31.368 0.084 ;
    END
  END o[183]
  PIN o[184]
    DIRECTION OUTPUT ;
    USE SIGNAL ;
    PORT
      LAYER M5 ;
        RECT  31.44 0 31.464 0.084 ;
    END
  END o[184]
  PIN o[185]
    DIRECTION OUTPUT ;
    USE SIGNAL ;
    PORT
      LAYER M5 ;
        RECT  31.536 0 31.56 0.084 ;
    END
  END o[185]
  PIN o[186]
    DIRECTION OUTPUT ;
    USE SIGNAL ;
    PORT
      LAYER M5 ;
        RECT  31.632 0 31.656 0.084 ;
    END
  END o[186]
  PIN o[187]
    DIRECTION OUTPUT ;
    USE SIGNAL ;
    PORT
      LAYER M5 ;
        RECT  31.728 0 31.752 0.084 ;
    END
  END o[187]
  PIN o[188]
    DIRECTION OUTPUT ;
    USE SIGNAL ;
    PORT
      LAYER M5 ;
        RECT  31.824 0 31.848 0.084 ;
    END
  END o[188]
  PIN o[189]
    DIRECTION OUTPUT ;
    USE SIGNAL ;
    PORT
      LAYER M5 ;
        RECT  31.92 0 31.944 0.084 ;
    END
  END o[189]
  PIN o[18]
    DIRECTION OUTPUT ;
    USE SIGNAL ;
    PORT
      LAYER M5 ;
        RECT  37.008 0 37.032 0.084 ;
    END
  END o[18]
  PIN o[190]
    DIRECTION OUTPUT ;
    USE SIGNAL ;
    PORT
      LAYER M5 ;
        RECT  32.016 0 32.04 0.084 ;
    END
  END o[190]
  PIN o[191]
    DIRECTION OUTPUT ;
    USE SIGNAL ;
    PORT
      LAYER M5 ;
        RECT  32.112 0 32.136 0.084 ;
    END
  END o[191]
  PIN o[192]
    DIRECTION OUTPUT ;
    USE SIGNAL ;
    PORT
      LAYER M5 ;
        RECT  42.192 0 42.216 0.084 ;
    END
  END o[192]
  PIN o[193]
    DIRECTION OUTPUT ;
    USE SIGNAL ;
    PORT
      LAYER M5 ;
        RECT  42.288 0 42.312 0.084 ;
    END
  END o[193]
  PIN o[194]
    DIRECTION OUTPUT ;
    USE SIGNAL ;
    PORT
      LAYER M5 ;
        RECT  42.384 0 42.408 0.084 ;
    END
  END o[194]
  PIN o[195]
    DIRECTION OUTPUT ;
    USE SIGNAL ;
    PORT
      LAYER M5 ;
        RECT  42.48 0 42.504 0.084 ;
    END
  END o[195]
  PIN o[196]
    DIRECTION OUTPUT ;
    USE SIGNAL ;
    PORT
      LAYER M5 ;
        RECT  42.576 0 42.6 0.084 ;
    END
  END o[196]
  PIN o[197]
    DIRECTION OUTPUT ;
    USE SIGNAL ;
    PORT
      LAYER M5 ;
        RECT  42.672 0 42.696 0.084 ;
    END
  END o[197]
  PIN o[198]
    DIRECTION OUTPUT ;
    USE SIGNAL ;
    PORT
      LAYER M5 ;
        RECT  42.768 0 42.792 0.084 ;
    END
  END o[198]
  PIN o[199]
    DIRECTION OUTPUT ;
    USE SIGNAL ;
    PORT
      LAYER M5 ;
        RECT  42.864 0 42.888 0.084 ;
    END
  END o[199]
  PIN o[19]
    DIRECTION OUTPUT ;
    USE SIGNAL ;
    PORT
      LAYER M5 ;
        RECT  37.104 0 37.128 0.084 ;
    END
  END o[19]
  PIN o[1]
    DIRECTION OUTPUT ;
    USE SIGNAL ;
    PORT
      LAYER M5 ;
        RECT  35.376 0 35.4 0.084 ;
    END
  END o[1]
  PIN o[200]
    DIRECTION OUTPUT ;
    USE SIGNAL ;
    PORT
      LAYER M5 ;
        RECT  42.96 0 42.984 0.084 ;
    END
  END o[200]
  PIN o[201]
    DIRECTION OUTPUT ;
    USE SIGNAL ;
    PORT
      LAYER M5 ;
        RECT  43.056 0 43.08 0.084 ;
    END
  END o[201]
  PIN o[202]
    DIRECTION OUTPUT ;
    USE SIGNAL ;
    PORT
      LAYER M5 ;
        RECT  43.152 0 43.176 0.084 ;
    END
  END o[202]
  PIN o[203]
    DIRECTION OUTPUT ;
    USE SIGNAL ;
    PORT
      LAYER M5 ;
        RECT  43.248 0 43.272 0.084 ;
    END
  END o[203]
  PIN o[204]
    DIRECTION OUTPUT ;
    USE SIGNAL ;
    PORT
      LAYER M5 ;
        RECT  43.344 0 43.368 0.084 ;
    END
  END o[204]
  PIN o[205]
    DIRECTION OUTPUT ;
    USE SIGNAL ;
    PORT
      LAYER M5 ;
        RECT  43.44 0 43.464 0.084 ;
    END
  END o[205]
  PIN o[206]
    DIRECTION OUTPUT ;
    USE SIGNAL ;
    PORT
      LAYER M5 ;
        RECT  43.536 0 43.56 0.084 ;
    END
  END o[206]
  PIN o[207]
    DIRECTION OUTPUT ;
    USE SIGNAL ;
    PORT
      LAYER M5 ;
        RECT  43.632 0 43.656 0.084 ;
    END
  END o[207]
  PIN o[208]
    DIRECTION OUTPUT ;
    USE SIGNAL ;
    PORT
      LAYER M5 ;
        RECT  43.728 0 43.752 0.084 ;
    END
  END o[208]
  PIN o[209]
    DIRECTION OUTPUT ;
    USE SIGNAL ;
    PORT
      LAYER M5 ;
        RECT  43.824 0 43.848 0.084 ;
    END
  END o[209]
  PIN o[20]
    DIRECTION OUTPUT ;
    USE SIGNAL ;
    PORT
      LAYER M5 ;
        RECT  37.2 0 37.224 0.084 ;
    END
  END o[20]
  PIN o[210]
    DIRECTION OUTPUT ;
    USE SIGNAL ;
    PORT
      LAYER M5 ;
        RECT  43.92 0 43.944 0.084 ;
    END
  END o[210]
  PIN o[211]
    DIRECTION OUTPUT ;
    USE SIGNAL ;
    PORT
      LAYER M5 ;
        RECT  44.016 0 44.04 0.084 ;
    END
  END o[211]
  PIN o[212]
    DIRECTION OUTPUT ;
    USE SIGNAL ;
    PORT
      LAYER M5 ;
        RECT  44.112 0 44.136 0.084 ;
    END
  END o[212]
  PIN o[213]
    DIRECTION OUTPUT ;
    USE SIGNAL ;
    PORT
      LAYER M5 ;
        RECT  44.208 0 44.232 0.084 ;
    END
  END o[213]
  PIN o[214]
    DIRECTION OUTPUT ;
    USE SIGNAL ;
    PORT
      LAYER M5 ;
        RECT  44.304 0 44.328 0.084 ;
    END
  END o[214]
  PIN o[215]
    DIRECTION OUTPUT ;
    USE SIGNAL ;
    PORT
      LAYER M5 ;
        RECT  44.4 0 44.424 0.084 ;
    END
  END o[215]
  PIN o[216]
    DIRECTION OUTPUT ;
    USE SIGNAL ;
    PORT
      LAYER M5 ;
        RECT  44.496 0 44.52 0.084 ;
    END
  END o[216]
  PIN o[217]
    DIRECTION OUTPUT ;
    USE SIGNAL ;
    PORT
      LAYER M5 ;
        RECT  44.592 0 44.616 0.084 ;
    END
  END o[217]
  PIN o[218]
    DIRECTION OUTPUT ;
    USE SIGNAL ;
    PORT
      LAYER M5 ;
        RECT  44.688 0 44.712 0.084 ;
    END
  END o[218]
  PIN o[219]
    DIRECTION OUTPUT ;
    USE SIGNAL ;
    PORT
      LAYER M5 ;
        RECT  44.784 0 44.808 0.084 ;
    END
  END o[219]
  PIN o[21]
    DIRECTION OUTPUT ;
    USE SIGNAL ;
    PORT
      LAYER M5 ;
        RECT  37.296 0 37.32 0.084 ;
    END
  END o[21]
  PIN o[220]
    DIRECTION OUTPUT ;
    USE SIGNAL ;
    PORT
      LAYER M5 ;
        RECT  44.88 0 44.904 0.084 ;
    END
  END o[220]
  PIN o[221]
    DIRECTION OUTPUT ;
    USE SIGNAL ;
    PORT
      LAYER M5 ;
        RECT  44.976 0 45 0.084 ;
    END
  END o[221]
  PIN o[222]
    DIRECTION OUTPUT ;
    USE SIGNAL ;
    PORT
      LAYER M5 ;
        RECT  45.072 0 45.096 0.084 ;
    END
  END o[222]
  PIN o[223]
    DIRECTION OUTPUT ;
    USE SIGNAL ;
    PORT
      LAYER M5 ;
        RECT  45.168 0 45.192 0.084 ;
    END
  END o[223]
  PIN o[224]
    DIRECTION OUTPUT ;
    USE SIGNAL ;
    PORT
      LAYER M5 ;
        RECT  39.12 0 39.144 0.084 ;
    END
  END o[224]
  PIN o[225]
    DIRECTION OUTPUT ;
    USE SIGNAL ;
    PORT
      LAYER M5 ;
        RECT  39.216 0 39.24 0.084 ;
    END
  END o[225]
  PIN o[226]
    DIRECTION OUTPUT ;
    USE SIGNAL ;
    PORT
      LAYER M5 ;
        RECT  39.312 0 39.336 0.084 ;
    END
  END o[226]
  PIN o[227]
    DIRECTION OUTPUT ;
    USE SIGNAL ;
    PORT
      LAYER M5 ;
        RECT  39.408 0 39.432 0.084 ;
    END
  END o[227]
  PIN o[228]
    DIRECTION OUTPUT ;
    USE SIGNAL ;
    PORT
      LAYER M5 ;
        RECT  39.504 0 39.528 0.084 ;
    END
  END o[228]
  PIN o[229]
    DIRECTION OUTPUT ;
    USE SIGNAL ;
    PORT
      LAYER M5 ;
        RECT  39.6 0 39.624 0.084 ;
    END
  END o[229]
  PIN o[22]
    DIRECTION OUTPUT ;
    USE SIGNAL ;
    PORT
      LAYER M5 ;
        RECT  37.392 0 37.416 0.084 ;
    END
  END o[22]
  PIN o[230]
    DIRECTION OUTPUT ;
    USE SIGNAL ;
    PORT
      LAYER M5 ;
        RECT  39.696 0 39.72 0.084 ;
    END
  END o[230]
  PIN o[231]
    DIRECTION OUTPUT ;
    USE SIGNAL ;
    PORT
      LAYER M5 ;
        RECT  39.792 0 39.816 0.084 ;
    END
  END o[231]
  PIN o[232]
    DIRECTION OUTPUT ;
    USE SIGNAL ;
    PORT
      LAYER M5 ;
        RECT  39.888 0 39.912 0.084 ;
    END
  END o[232]
  PIN o[233]
    DIRECTION OUTPUT ;
    USE SIGNAL ;
    PORT
      LAYER M5 ;
        RECT  39.984 0 40.008 0.084 ;
    END
  END o[233]
  PIN o[234]
    DIRECTION OUTPUT ;
    USE SIGNAL ;
    PORT
      LAYER M5 ;
        RECT  40.08 0 40.104 0.084 ;
    END
  END o[234]
  PIN o[235]
    DIRECTION OUTPUT ;
    USE SIGNAL ;
    PORT
      LAYER M5 ;
        RECT  40.176 0 40.2 0.084 ;
    END
  END o[235]
  PIN o[236]
    DIRECTION OUTPUT ;
    USE SIGNAL ;
    PORT
      LAYER M5 ;
        RECT  40.272 0 40.296 0.084 ;
    END
  END o[236]
  PIN o[237]
    DIRECTION OUTPUT ;
    USE SIGNAL ;
    PORT
      LAYER M5 ;
        RECT  40.368 0 40.392 0.084 ;
    END
  END o[237]
  PIN o[238]
    DIRECTION OUTPUT ;
    USE SIGNAL ;
    PORT
      LAYER M5 ;
        RECT  40.464 0 40.488 0.084 ;
    END
  END o[238]
  PIN o[239]
    DIRECTION OUTPUT ;
    USE SIGNAL ;
    PORT
      LAYER M5 ;
        RECT  40.56 0 40.584 0.084 ;
    END
  END o[239]
  PIN o[23]
    DIRECTION OUTPUT ;
    USE SIGNAL ;
    PORT
      LAYER M5 ;
        RECT  37.488 0 37.512 0.084 ;
    END
  END o[23]
  PIN o[240]
    DIRECTION OUTPUT ;
    USE SIGNAL ;
    PORT
      LAYER M5 ;
        RECT  40.656 0 40.68 0.084 ;
    END
  END o[240]
  PIN o[241]
    DIRECTION OUTPUT ;
    USE SIGNAL ;
    PORT
      LAYER M5 ;
        RECT  40.752 0 40.776 0.084 ;
    END
  END o[241]
  PIN o[242]
    DIRECTION OUTPUT ;
    USE SIGNAL ;
    PORT
      LAYER M5 ;
        RECT  40.848 0 40.872 0.084 ;
    END
  END o[242]
  PIN o[243]
    DIRECTION OUTPUT ;
    USE SIGNAL ;
    PORT
      LAYER M5 ;
        RECT  40.944 0 40.968 0.084 ;
    END
  END o[243]
  PIN o[244]
    DIRECTION OUTPUT ;
    USE SIGNAL ;
    PORT
      LAYER M5 ;
        RECT  41.04 0 41.064 0.084 ;
    END
  END o[244]
  PIN o[245]
    DIRECTION OUTPUT ;
    USE SIGNAL ;
    PORT
      LAYER M5 ;
        RECT  41.136 0 41.16 0.084 ;
    END
  END o[245]
  PIN o[246]
    DIRECTION OUTPUT ;
    USE SIGNAL ;
    PORT
      LAYER M5 ;
        RECT  41.232 0 41.256 0.084 ;
    END
  END o[246]
  PIN o[247]
    DIRECTION OUTPUT ;
    USE SIGNAL ;
    PORT
      LAYER M5 ;
        RECT  41.328 0 41.352 0.084 ;
    END
  END o[247]
  PIN o[248]
    DIRECTION OUTPUT ;
    USE SIGNAL ;
    PORT
      LAYER M5 ;
        RECT  41.424 0 41.448 0.084 ;
    END
  END o[248]
  PIN o[249]
    DIRECTION OUTPUT ;
    USE SIGNAL ;
    PORT
      LAYER M5 ;
        RECT  41.52 0 41.544 0.084 ;
    END
  END o[249]
  PIN o[24]
    DIRECTION OUTPUT ;
    USE SIGNAL ;
    PORT
      LAYER M5 ;
        RECT  37.584 0 37.608 0.084 ;
    END
  END o[24]
  PIN o[250]
    DIRECTION OUTPUT ;
    USE SIGNAL ;
    PORT
      LAYER M5 ;
        RECT  41.616 0 41.64 0.084 ;
    END
  END o[250]
  PIN o[251]
    DIRECTION OUTPUT ;
    USE SIGNAL ;
    PORT
      LAYER M5 ;
        RECT  41.712 0 41.736 0.084 ;
    END
  END o[251]
  PIN o[252]
    DIRECTION OUTPUT ;
    USE SIGNAL ;
    PORT
      LAYER M5 ;
        RECT  41.808 0 41.832 0.084 ;
    END
  END o[252]
  PIN o[253]
    DIRECTION OUTPUT ;
    USE SIGNAL ;
    PORT
      LAYER M5 ;
        RECT  41.904 0 41.928 0.084 ;
    END
  END o[253]
  PIN o[254]
    DIRECTION OUTPUT ;
    USE SIGNAL ;
    PORT
      LAYER M5 ;
        RECT  42 0 42.024 0.084 ;
    END
  END o[254]
  PIN o[255]
    DIRECTION OUTPUT ;
    USE SIGNAL ;
    PORT
      LAYER M5 ;
        RECT  42.096 0 42.12 0.084 ;
    END
  END o[255]
  PIN o[256]
    DIRECTION OUTPUT ;
    USE SIGNAL ;
    PORT
      LAYER M5 ;
        RECT  45.264 0 45.288 0.084 ;
    END
  END o[256]
  PIN o[257]
    DIRECTION OUTPUT ;
    USE SIGNAL ;
    PORT
      LAYER M5 ;
        RECT  45.36 0 45.384 0.084 ;
    END
  END o[257]
  PIN o[258]
    DIRECTION OUTPUT ;
    USE SIGNAL ;
    PORT
      LAYER M5 ;
        RECT  45.456 0 45.48 0.084 ;
    END
  END o[258]
  PIN o[259]
    DIRECTION OUTPUT ;
    USE SIGNAL ;
    PORT
      LAYER M5 ;
        RECT  45.552 0 45.576 0.084 ;
    END
  END o[259]
  PIN o[25]
    DIRECTION OUTPUT ;
    USE SIGNAL ;
    PORT
      LAYER M5 ;
        RECT  37.68 0 37.704 0.084 ;
    END
  END o[25]
  PIN o[260]
    DIRECTION OUTPUT ;
    USE SIGNAL ;
    PORT
      LAYER M5 ;
        RECT  45.648 0 45.672 0.084 ;
    END
  END o[260]
  PIN o[261]
    DIRECTION OUTPUT ;
    USE SIGNAL ;
    PORT
      LAYER M5 ;
        RECT  45.744 0 45.768 0.084 ;
    END
  END o[261]
  PIN o[262]
    DIRECTION OUTPUT ;
    USE SIGNAL ;
    PORT
      LAYER M5 ;
        RECT  45.84 0 45.864 0.084 ;
    END
  END o[262]
  PIN o[263]
    DIRECTION OUTPUT ;
    USE SIGNAL ;
    PORT
      LAYER M5 ;
        RECT  45.936 0 45.96 0.084 ;
    END
  END o[263]
  PIN o[264]
    DIRECTION OUTPUT ;
    USE SIGNAL ;
    PORT
      LAYER M5 ;
        RECT  46.032 0 46.056 0.084 ;
    END
  END o[264]
  PIN o[265]
    DIRECTION OUTPUT ;
    USE SIGNAL ;
    PORT
      LAYER M5 ;
        RECT  46.128 0 46.152 0.084 ;
    END
  END o[265]
  PIN o[266]
    DIRECTION OUTPUT ;
    USE SIGNAL ;
    PORT
      LAYER M5 ;
        RECT  46.224 0 46.248 0.084 ;
    END
  END o[266]
  PIN o[267]
    DIRECTION OUTPUT ;
    USE SIGNAL ;
    PORT
      LAYER M5 ;
        RECT  46.32 0 46.344 0.084 ;
    END
  END o[267]
  PIN o[268]
    DIRECTION OUTPUT ;
    USE SIGNAL ;
    PORT
      LAYER M5 ;
        RECT  46.416 0 46.44 0.084 ;
    END
  END o[268]
  PIN o[269]
    DIRECTION OUTPUT ;
    USE SIGNAL ;
    PORT
      LAYER M5 ;
        RECT  46.512 0 46.536 0.084 ;
    END
  END o[269]
  PIN o[26]
    DIRECTION OUTPUT ;
    USE SIGNAL ;
    PORT
      LAYER M5 ;
        RECT  37.776 0 37.8 0.084 ;
    END
  END o[26]
  PIN o[270]
    DIRECTION OUTPUT ;
    USE SIGNAL ;
    PORT
      LAYER M5 ;
        RECT  46.608 0 46.632 0.084 ;
    END
  END o[270]
  PIN o[271]
    DIRECTION OUTPUT ;
    USE SIGNAL ;
    PORT
      LAYER M5 ;
        RECT  46.704 0 46.728 0.084 ;
    END
  END o[271]
  PIN o[272]
    DIRECTION OUTPUT ;
    USE SIGNAL ;
    PORT
      LAYER M5 ;
        RECT  46.8 0 46.824 0.084 ;
    END
  END o[272]
  PIN o[273]
    DIRECTION OUTPUT ;
    USE SIGNAL ;
    PORT
      LAYER M5 ;
        RECT  46.896 0 46.92 0.084 ;
    END
  END o[273]
  PIN o[274]
    DIRECTION OUTPUT ;
    USE SIGNAL ;
    PORT
      LAYER M5 ;
        RECT  46.992 0 47.016 0.084 ;
    END
  END o[274]
  PIN o[275]
    DIRECTION OUTPUT ;
    USE SIGNAL ;
    PORT
      LAYER M5 ;
        RECT  47.088 0 47.112 0.084 ;
    END
  END o[275]
  PIN o[276]
    DIRECTION OUTPUT ;
    USE SIGNAL ;
    PORT
      LAYER M5 ;
        RECT  47.184 0 47.208 0.084 ;
    END
  END o[276]
  PIN o[277]
    DIRECTION OUTPUT ;
    USE SIGNAL ;
    PORT
      LAYER M5 ;
        RECT  47.28 0 47.304 0.084 ;
    END
  END o[277]
  PIN o[278]
    DIRECTION OUTPUT ;
    USE SIGNAL ;
    PORT
      LAYER M5 ;
        RECT  47.376 0 47.4 0.084 ;
    END
  END o[278]
  PIN o[279]
    DIRECTION OUTPUT ;
    USE SIGNAL ;
    PORT
      LAYER M5 ;
        RECT  47.472 0 47.496 0.084 ;
    END
  END o[279]
  PIN o[27]
    DIRECTION OUTPUT ;
    USE SIGNAL ;
    PORT
      LAYER M5 ;
        RECT  37.872 0 37.896 0.084 ;
    END
  END o[27]
  PIN o[280]
    DIRECTION OUTPUT ;
    USE SIGNAL ;
    PORT
      LAYER M5 ;
        RECT  47.568 0 47.592 0.084 ;
    END
  END o[280]
  PIN o[281]
    DIRECTION OUTPUT ;
    USE SIGNAL ;
    PORT
      LAYER M5 ;
        RECT  47.664 0 47.688 0.084 ;
    END
  END o[281]
  PIN o[282]
    DIRECTION OUTPUT ;
    USE SIGNAL ;
    PORT
      LAYER M5 ;
        RECT  47.76 0 47.784 0.084 ;
    END
  END o[282]
  PIN o[283]
    DIRECTION OUTPUT ;
    USE SIGNAL ;
    PORT
      LAYER M5 ;
        RECT  47.856 0 47.88 0.084 ;
    END
  END o[283]
  PIN o[284]
    DIRECTION OUTPUT ;
    USE SIGNAL ;
    PORT
      LAYER M5 ;
        RECT  47.952 0 47.976 0.084 ;
    END
  END o[284]
  PIN o[285]
    DIRECTION OUTPUT ;
    USE SIGNAL ;
    PORT
      LAYER M5 ;
        RECT  48.048 0 48.072 0.084 ;
    END
  END o[285]
  PIN o[286]
    DIRECTION OUTPUT ;
    USE SIGNAL ;
    PORT
      LAYER M5 ;
        RECT  48.144 0 48.168 0.084 ;
    END
  END o[286]
  PIN o[287]
    DIRECTION OUTPUT ;
    USE SIGNAL ;
    PORT
      LAYER M5 ;
        RECT  48.24 0 48.264 0.084 ;
    END
  END o[287]
  PIN o[288]
    DIRECTION OUTPUT ;
    USE SIGNAL ;
    PORT
      LAYER M5 ;
        RECT  54.48 0 54.504 0.084 ;
    END
  END o[288]
  PIN o[289]
    DIRECTION OUTPUT ;
    USE SIGNAL ;
    PORT
      LAYER M5 ;
        RECT  54.576 0 54.6 0.084 ;
    END
  END o[289]
  PIN o[28]
    DIRECTION OUTPUT ;
    USE SIGNAL ;
    PORT
      LAYER M5 ;
        RECT  37.968 0 37.992 0.084 ;
    END
  END o[28]
  PIN o[290]
    DIRECTION OUTPUT ;
    USE SIGNAL ;
    PORT
      LAYER M5 ;
        RECT  54.672 0 54.696 0.084 ;
    END
  END o[290]
  PIN o[291]
    DIRECTION OUTPUT ;
    USE SIGNAL ;
    PORT
      LAYER M5 ;
        RECT  54.768 0 54.792 0.084 ;
    END
  END o[291]
  PIN o[292]
    DIRECTION OUTPUT ;
    USE SIGNAL ;
    PORT
      LAYER M5 ;
        RECT  54.864 0 54.888 0.084 ;
    END
  END o[292]
  PIN o[293]
    DIRECTION OUTPUT ;
    USE SIGNAL ;
    PORT
      LAYER M5 ;
        RECT  54.96 0 54.984 0.084 ;
    END
  END o[293]
  PIN o[294]
    DIRECTION OUTPUT ;
    USE SIGNAL ;
    PORT
      LAYER M5 ;
        RECT  55.056 0 55.08 0.084 ;
    END
  END o[294]
  PIN o[295]
    DIRECTION OUTPUT ;
    USE SIGNAL ;
    PORT
      LAYER M5 ;
        RECT  55.152 0 55.176 0.084 ;
    END
  END o[295]
  PIN o[296]
    DIRECTION OUTPUT ;
    USE SIGNAL ;
    PORT
      LAYER M5 ;
        RECT  55.248 0 55.272 0.084 ;
    END
  END o[296]
  PIN o[297]
    DIRECTION OUTPUT ;
    USE SIGNAL ;
    PORT
      LAYER M5 ;
        RECT  55.344 0 55.368 0.084 ;
    END
  END o[297]
  PIN o[298]
    DIRECTION OUTPUT ;
    USE SIGNAL ;
    PORT
      LAYER M5 ;
        RECT  55.44 0 55.464 0.084 ;
    END
  END o[298]
  PIN o[299]
    DIRECTION OUTPUT ;
    USE SIGNAL ;
    PORT
      LAYER M5 ;
        RECT  55.536 0 55.56 0.084 ;
    END
  END o[299]
  PIN o[29]
    DIRECTION OUTPUT ;
    USE SIGNAL ;
    PORT
      LAYER M5 ;
        RECT  38.064 0 38.088 0.084 ;
    END
  END o[29]
  PIN o[2]
    DIRECTION OUTPUT ;
    USE SIGNAL ;
    PORT
      LAYER M5 ;
        RECT  35.472 0 35.496 0.084 ;
    END
  END o[2]
  PIN o[300]
    DIRECTION OUTPUT ;
    USE SIGNAL ;
    PORT
      LAYER M5 ;
        RECT  55.632 0 55.656 0.084 ;
    END
  END o[300]
  PIN o[301]
    DIRECTION OUTPUT ;
    USE SIGNAL ;
    PORT
      LAYER M5 ;
        RECT  55.728 0 55.752 0.084 ;
    END
  END o[301]
  PIN o[302]
    DIRECTION OUTPUT ;
    USE SIGNAL ;
    PORT
      LAYER M5 ;
        RECT  55.824 0 55.848 0.084 ;
    END
  END o[302]
  PIN o[303]
    DIRECTION OUTPUT ;
    USE SIGNAL ;
    PORT
      LAYER M5 ;
        RECT  55.92 0 55.944 0.084 ;
    END
  END o[303]
  PIN o[304]
    DIRECTION OUTPUT ;
    USE SIGNAL ;
    PORT
      LAYER M5 ;
        RECT  56.016 0 56.04 0.084 ;
    END
  END o[304]
  PIN o[305]
    DIRECTION OUTPUT ;
    USE SIGNAL ;
    PORT
      LAYER M5 ;
        RECT  56.112 0 56.136 0.084 ;
    END
  END o[305]
  PIN o[306]
    DIRECTION OUTPUT ;
    USE SIGNAL ;
    PORT
      LAYER M5 ;
        RECT  56.208 0 56.232 0.084 ;
    END
  END o[306]
  PIN o[307]
    DIRECTION OUTPUT ;
    USE SIGNAL ;
    PORT
      LAYER M5 ;
        RECT  56.304 0 56.328 0.084 ;
    END
  END o[307]
  PIN o[308]
    DIRECTION OUTPUT ;
    USE SIGNAL ;
    PORT
      LAYER M5 ;
        RECT  56.4 0 56.424 0.084 ;
    END
  END o[308]
  PIN o[309]
    DIRECTION OUTPUT ;
    USE SIGNAL ;
    PORT
      LAYER M5 ;
        RECT  56.496 0 56.52 0.084 ;
    END
  END o[309]
  PIN o[30]
    DIRECTION OUTPUT ;
    USE SIGNAL ;
    PORT
      LAYER M5 ;
        RECT  38.16 0 38.184 0.084 ;
    END
  END o[30]
  PIN o[310]
    DIRECTION OUTPUT ;
    USE SIGNAL ;
    PORT
      LAYER M5 ;
        RECT  56.592 0 56.616 0.084 ;
    END
  END o[310]
  PIN o[311]
    DIRECTION OUTPUT ;
    USE SIGNAL ;
    PORT
      LAYER M5 ;
        RECT  56.688 0 56.712 0.084 ;
    END
  END o[311]
  PIN o[312]
    DIRECTION OUTPUT ;
    USE SIGNAL ;
    PORT
      LAYER M5 ;
        RECT  56.784 0 56.808 0.084 ;
    END
  END o[312]
  PIN o[313]
    DIRECTION OUTPUT ;
    USE SIGNAL ;
    PORT
      LAYER M5 ;
        RECT  56.88 0 56.904 0.084 ;
    END
  END o[313]
  PIN o[314]
    DIRECTION OUTPUT ;
    USE SIGNAL ;
    PORT
      LAYER M5 ;
        RECT  56.976 0 57 0.084 ;
    END
  END o[314]
  PIN o[315]
    DIRECTION OUTPUT ;
    USE SIGNAL ;
    PORT
      LAYER M5 ;
        RECT  57.072 0 57.096 0.084 ;
    END
  END o[315]
  PIN o[316]
    DIRECTION OUTPUT ;
    USE SIGNAL ;
    PORT
      LAYER M5 ;
        RECT  57.168 0 57.192 0.084 ;
    END
  END o[316]
  PIN o[317]
    DIRECTION OUTPUT ;
    USE SIGNAL ;
    PORT
      LAYER M5 ;
        RECT  57.264 0 57.288 0.084 ;
    END
  END o[317]
  PIN o[318]
    DIRECTION OUTPUT ;
    USE SIGNAL ;
    PORT
      LAYER M5 ;
        RECT  57.36 0 57.384 0.084 ;
    END
  END o[318]
  PIN o[319]
    DIRECTION OUTPUT ;
    USE SIGNAL ;
    PORT
      LAYER M5 ;
        RECT  57.456 0 57.48 0.084 ;
    END
  END o[319]
  PIN o[31]
    DIRECTION OUTPUT ;
    USE SIGNAL ;
    PORT
      LAYER M5 ;
        RECT  38.256 0 38.28 0.084 ;
    END
  END o[31]
  PIN o[320]
    DIRECTION OUTPUT ;
    USE SIGNAL ;
    PORT
      LAYER M5 ;
        RECT  51.408 0 51.432 0.084 ;
    END
  END o[320]
  PIN o[321]
    DIRECTION OUTPUT ;
    USE SIGNAL ;
    PORT
      LAYER M5 ;
        RECT  51.504 0 51.528 0.084 ;
    END
  END o[321]
  PIN o[322]
    DIRECTION OUTPUT ;
    USE SIGNAL ;
    PORT
      LAYER M5 ;
        RECT  51.6 0 51.624 0.084 ;
    END
  END o[322]
  PIN o[323]
    DIRECTION OUTPUT ;
    USE SIGNAL ;
    PORT
      LAYER M5 ;
        RECT  51.696 0 51.72 0.084 ;
    END
  END o[323]
  PIN o[324]
    DIRECTION OUTPUT ;
    USE SIGNAL ;
    PORT
      LAYER M5 ;
        RECT  51.792 0 51.816 0.084 ;
    END
  END o[324]
  PIN o[325]
    DIRECTION OUTPUT ;
    USE SIGNAL ;
    PORT
      LAYER M5 ;
        RECT  51.888 0 51.912 0.084 ;
    END
  END o[325]
  PIN o[326]
    DIRECTION OUTPUT ;
    USE SIGNAL ;
    PORT
      LAYER M5 ;
        RECT  51.984 0 52.008 0.084 ;
    END
  END o[326]
  PIN o[327]
    DIRECTION OUTPUT ;
    USE SIGNAL ;
    PORT
      LAYER M5 ;
        RECT  52.08 0 52.104 0.084 ;
    END
  END o[327]
  PIN o[328]
    DIRECTION OUTPUT ;
    USE SIGNAL ;
    PORT
      LAYER M5 ;
        RECT  52.176 0 52.2 0.084 ;
    END
  END o[328]
  PIN o[329]
    DIRECTION OUTPUT ;
    USE SIGNAL ;
    PORT
      LAYER M5 ;
        RECT  52.272 0 52.296 0.084 ;
    END
  END o[329]
  PIN o[32]
    DIRECTION OUTPUT ;
    USE SIGNAL ;
    PORT
      LAYER M5 ;
        RECT  22.992 0 23.016 0.084 ;
    END
  END o[32]
  PIN o[330]
    DIRECTION OUTPUT ;
    USE SIGNAL ;
    PORT
      LAYER M5 ;
        RECT  52.368 0 52.392 0.084 ;
    END
  END o[330]
  PIN o[331]
    DIRECTION OUTPUT ;
    USE SIGNAL ;
    PORT
      LAYER M5 ;
        RECT  52.464 0 52.488 0.084 ;
    END
  END o[331]
  PIN o[332]
    DIRECTION OUTPUT ;
    USE SIGNAL ;
    PORT
      LAYER M5 ;
        RECT  52.56 0 52.584 0.084 ;
    END
  END o[332]
  PIN o[333]
    DIRECTION OUTPUT ;
    USE SIGNAL ;
    PORT
      LAYER M5 ;
        RECT  52.656 0 52.68 0.084 ;
    END
  END o[333]
  PIN o[334]
    DIRECTION OUTPUT ;
    USE SIGNAL ;
    PORT
      LAYER M5 ;
        RECT  52.752 0 52.776 0.084 ;
    END
  END o[334]
  PIN o[335]
    DIRECTION OUTPUT ;
    USE SIGNAL ;
    PORT
      LAYER M5 ;
        RECT  52.848 0 52.872 0.084 ;
    END
  END o[335]
  PIN o[336]
    DIRECTION OUTPUT ;
    USE SIGNAL ;
    PORT
      LAYER M5 ;
        RECT  52.944 0 52.968 0.084 ;
    END
  END o[336]
  PIN o[337]
    DIRECTION OUTPUT ;
    USE SIGNAL ;
    PORT
      LAYER M5 ;
        RECT  53.04 0 53.064 0.084 ;
    END
  END o[337]
  PIN o[338]
    DIRECTION OUTPUT ;
    USE SIGNAL ;
    PORT
      LAYER M5 ;
        RECT  53.136 0 53.16 0.084 ;
    END
  END o[338]
  PIN o[339]
    DIRECTION OUTPUT ;
    USE SIGNAL ;
    PORT
      LAYER M5 ;
        RECT  53.232 0 53.256 0.084 ;
    END
  END o[339]
  PIN o[33]
    DIRECTION OUTPUT ;
    USE SIGNAL ;
    PORT
      LAYER M5 ;
        RECT  23.088 0 23.112 0.084 ;
    END
  END o[33]
  PIN o[340]
    DIRECTION OUTPUT ;
    USE SIGNAL ;
    PORT
      LAYER M5 ;
        RECT  53.328 0 53.352 0.084 ;
    END
  END o[340]
  PIN o[341]
    DIRECTION OUTPUT ;
    USE SIGNAL ;
    PORT
      LAYER M5 ;
        RECT  53.424 0 53.448 0.084 ;
    END
  END o[341]
  PIN o[342]
    DIRECTION OUTPUT ;
    USE SIGNAL ;
    PORT
      LAYER M5 ;
        RECT  53.52 0 53.544 0.084 ;
    END
  END o[342]
  PIN o[343]
    DIRECTION OUTPUT ;
    USE SIGNAL ;
    PORT
      LAYER M5 ;
        RECT  53.616 0 53.64 0.084 ;
    END
  END o[343]
  PIN o[344]
    DIRECTION OUTPUT ;
    USE SIGNAL ;
    PORT
      LAYER M5 ;
        RECT  53.712 0 53.736 0.084 ;
    END
  END o[344]
  PIN o[345]
    DIRECTION OUTPUT ;
    USE SIGNAL ;
    PORT
      LAYER M5 ;
        RECT  53.808 0 53.832 0.084 ;
    END
  END o[345]
  PIN o[346]
    DIRECTION OUTPUT ;
    USE SIGNAL ;
    PORT
      LAYER M5 ;
        RECT  53.904 0 53.928 0.084 ;
    END
  END o[346]
  PIN o[347]
    DIRECTION OUTPUT ;
    USE SIGNAL ;
    PORT
      LAYER M5 ;
        RECT  54 0 54.024 0.084 ;
    END
  END o[347]
  PIN o[348]
    DIRECTION OUTPUT ;
    USE SIGNAL ;
    PORT
      LAYER M5 ;
        RECT  54.096 0 54.12 0.084 ;
    END
  END o[348]
  PIN o[349]
    DIRECTION OUTPUT ;
    USE SIGNAL ;
    PORT
      LAYER M5 ;
        RECT  54.192 0 54.216 0.084 ;
    END
  END o[349]
  PIN o[34]
    DIRECTION OUTPUT ;
    USE SIGNAL ;
    PORT
      LAYER M5 ;
        RECT  23.184 0 23.208 0.084 ;
    END
  END o[34]
  PIN o[350]
    DIRECTION OUTPUT ;
    USE SIGNAL ;
    PORT
      LAYER M5 ;
        RECT  54.288 0 54.312 0.084 ;
    END
  END o[350]
  PIN o[351]
    DIRECTION OUTPUT ;
    USE SIGNAL ;
    PORT
      LAYER M5 ;
        RECT  54.384 0 54.408 0.084 ;
    END
  END o[351]
  PIN o[352]
    DIRECTION OUTPUT ;
    USE SIGNAL ;
    PORT
      LAYER M5 ;
        RECT  48.336 0 48.36 0.084 ;
    END
  END o[352]
  PIN o[353]
    DIRECTION OUTPUT ;
    USE SIGNAL ;
    PORT
      LAYER M5 ;
        RECT  48.432 0 48.456 0.084 ;
    END
  END o[353]
  PIN o[354]
    DIRECTION OUTPUT ;
    USE SIGNAL ;
    PORT
      LAYER M5 ;
        RECT  48.528 0 48.552 0.084 ;
    END
  END o[354]
  PIN o[355]
    DIRECTION OUTPUT ;
    USE SIGNAL ;
    PORT
      LAYER M5 ;
        RECT  48.624 0 48.648 0.084 ;
    END
  END o[355]
  PIN o[356]
    DIRECTION OUTPUT ;
    USE SIGNAL ;
    PORT
      LAYER M5 ;
        RECT  48.72 0 48.744 0.084 ;
    END
  END o[356]
  PIN o[357]
    DIRECTION OUTPUT ;
    USE SIGNAL ;
    PORT
      LAYER M5 ;
        RECT  48.816 0 48.84 0.084 ;
    END
  END o[357]
  PIN o[358]
    DIRECTION OUTPUT ;
    USE SIGNAL ;
    PORT
      LAYER M5 ;
        RECT  48.912 0 48.936 0.084 ;
    END
  END o[358]
  PIN o[359]
    DIRECTION OUTPUT ;
    USE SIGNAL ;
    PORT
      LAYER M5 ;
        RECT  49.008 0 49.032 0.084 ;
    END
  END o[359]
  PIN o[35]
    DIRECTION OUTPUT ;
    USE SIGNAL ;
    PORT
      LAYER M5 ;
        RECT  23.28 0 23.304 0.084 ;
    END
  END o[35]
  PIN o[360]
    DIRECTION OUTPUT ;
    USE SIGNAL ;
    PORT
      LAYER M5 ;
        RECT  49.104 0 49.128 0.084 ;
    END
  END o[360]
  PIN o[361]
    DIRECTION OUTPUT ;
    USE SIGNAL ;
    PORT
      LAYER M5 ;
        RECT  49.2 0 49.224 0.084 ;
    END
  END o[361]
  PIN o[362]
    DIRECTION OUTPUT ;
    USE SIGNAL ;
    PORT
      LAYER M5 ;
        RECT  49.296 0 49.32 0.084 ;
    END
  END o[362]
  PIN o[363]
    DIRECTION OUTPUT ;
    USE SIGNAL ;
    PORT
      LAYER M5 ;
        RECT  49.392 0 49.416 0.084 ;
    END
  END o[363]
  PIN o[364]
    DIRECTION OUTPUT ;
    USE SIGNAL ;
    PORT
      LAYER M5 ;
        RECT  49.488 0 49.512 0.084 ;
    END
  END o[364]
  PIN o[365]
    DIRECTION OUTPUT ;
    USE SIGNAL ;
    PORT
      LAYER M5 ;
        RECT  49.584 0 49.608 0.084 ;
    END
  END o[365]
  PIN o[366]
    DIRECTION OUTPUT ;
    USE SIGNAL ;
    PORT
      LAYER M5 ;
        RECT  49.68 0 49.704 0.084 ;
    END
  END o[366]
  PIN o[367]
    DIRECTION OUTPUT ;
    USE SIGNAL ;
    PORT
      LAYER M5 ;
        RECT  49.776 0 49.8 0.084 ;
    END
  END o[367]
  PIN o[368]
    DIRECTION OUTPUT ;
    USE SIGNAL ;
    PORT
      LAYER M5 ;
        RECT  49.872 0 49.896 0.084 ;
    END
  END o[368]
  PIN o[369]
    DIRECTION OUTPUT ;
    USE SIGNAL ;
    PORT
      LAYER M5 ;
        RECT  49.968 0 49.992 0.084 ;
    END
  END o[369]
  PIN o[36]
    DIRECTION OUTPUT ;
    USE SIGNAL ;
    PORT
      LAYER M5 ;
        RECT  23.376 0 23.4 0.084 ;
    END
  END o[36]
  PIN o[370]
    DIRECTION OUTPUT ;
    USE SIGNAL ;
    PORT
      LAYER M5 ;
        RECT  50.064 0 50.088 0.084 ;
    END
  END o[370]
  PIN o[371]
    DIRECTION OUTPUT ;
    USE SIGNAL ;
    PORT
      LAYER M5 ;
        RECT  50.16 0 50.184 0.084 ;
    END
  END o[371]
  PIN o[372]
    DIRECTION OUTPUT ;
    USE SIGNAL ;
    PORT
      LAYER M5 ;
        RECT  50.256 0 50.28 0.084 ;
    END
  END o[372]
  PIN o[373]
    DIRECTION OUTPUT ;
    USE SIGNAL ;
    PORT
      LAYER M5 ;
        RECT  50.352 0 50.376 0.084 ;
    END
  END o[373]
  PIN o[374]
    DIRECTION OUTPUT ;
    USE SIGNAL ;
    PORT
      LAYER M5 ;
        RECT  50.448 0 50.472 0.084 ;
    END
  END o[374]
  PIN o[375]
    DIRECTION OUTPUT ;
    USE SIGNAL ;
    PORT
      LAYER M5 ;
        RECT  50.544 0 50.568 0.084 ;
    END
  END o[375]
  PIN o[376]
    DIRECTION OUTPUT ;
    USE SIGNAL ;
    PORT
      LAYER M5 ;
        RECT  50.64 0 50.664 0.084 ;
    END
  END o[376]
  PIN o[377]
    DIRECTION OUTPUT ;
    USE SIGNAL ;
    PORT
      LAYER M5 ;
        RECT  50.736 0 50.76 0.084 ;
    END
  END o[377]
  PIN o[378]
    DIRECTION OUTPUT ;
    USE SIGNAL ;
    PORT
      LAYER M5 ;
        RECT  50.832 0 50.856 0.084 ;
    END
  END o[378]
  PIN o[379]
    DIRECTION OUTPUT ;
    USE SIGNAL ;
    PORT
      LAYER M5 ;
        RECT  50.928 0 50.952 0.084 ;
    END
  END o[379]
  PIN o[37]
    DIRECTION OUTPUT ;
    USE SIGNAL ;
    PORT
      LAYER M5 ;
        RECT  23.472 0 23.496 0.084 ;
    END
  END o[37]
  PIN o[380]
    DIRECTION OUTPUT ;
    USE SIGNAL ;
    PORT
      LAYER M5 ;
        RECT  51.024 0 51.048 0.084 ;
    END
  END o[380]
  PIN o[381]
    DIRECTION OUTPUT ;
    USE SIGNAL ;
    PORT
      LAYER M5 ;
        RECT  51.12 0 51.144 0.084 ;
    END
  END o[381]
  PIN o[382]
    DIRECTION OUTPUT ;
    USE SIGNAL ;
    PORT
      LAYER M5 ;
        RECT  51.216 0 51.24 0.084 ;
    END
  END o[382]
  PIN o[383]
    DIRECTION OUTPUT ;
    USE SIGNAL ;
    PORT
      LAYER M5 ;
        RECT  51.312 0 51.336 0.084 ;
    END
  END o[383]
  PIN o[384]
    DIRECTION OUTPUT ;
    USE SIGNAL ;
    PORT
      LAYER M5 ;
        RECT  3.792 0 3.816 0.084 ;
    END
  END o[384]
  PIN o[385]
    DIRECTION OUTPUT ;
    USE SIGNAL ;
    PORT
      LAYER M5 ;
        RECT  3.888 0 3.912 0.084 ;
    END
  END o[385]
  PIN o[386]
    DIRECTION OUTPUT ;
    USE SIGNAL ;
    PORT
      LAYER M5 ;
        RECT  3.984 0 4.008 0.084 ;
    END
  END o[386]
  PIN o[387]
    DIRECTION OUTPUT ;
    USE SIGNAL ;
    PORT
      LAYER M5 ;
        RECT  4.08 0 4.104 0.084 ;
    END
  END o[387]
  PIN o[388]
    DIRECTION OUTPUT ;
    USE SIGNAL ;
    PORT
      LAYER M5 ;
        RECT  4.176 0 4.2 0.084 ;
    END
  END o[388]
  PIN o[389]
    DIRECTION OUTPUT ;
    USE SIGNAL ;
    PORT
      LAYER M5 ;
        RECT  4.272 0 4.296 0.084 ;
    END
  END o[389]
  PIN o[38]
    DIRECTION OUTPUT ;
    USE SIGNAL ;
    PORT
      LAYER M5 ;
        RECT  23.568 0 23.592 0.084 ;
    END
  END o[38]
  PIN o[390]
    DIRECTION OUTPUT ;
    USE SIGNAL ;
    PORT
      LAYER M5 ;
        RECT  4.368 0 4.392 0.084 ;
    END
  END o[390]
  PIN o[391]
    DIRECTION OUTPUT ;
    USE SIGNAL ;
    PORT
      LAYER M5 ;
        RECT  4.464 0 4.488 0.084 ;
    END
  END o[391]
  PIN o[392]
    DIRECTION OUTPUT ;
    USE SIGNAL ;
    PORT
      LAYER M5 ;
        RECT  4.56 0 4.584 0.084 ;
    END
  END o[392]
  PIN o[393]
    DIRECTION OUTPUT ;
    USE SIGNAL ;
    PORT
      LAYER M5 ;
        RECT  4.656 0 4.68 0.084 ;
    END
  END o[393]
  PIN o[394]
    DIRECTION OUTPUT ;
    USE SIGNAL ;
    PORT
      LAYER M5 ;
        RECT  4.752 0 4.776 0.084 ;
    END
  END o[394]
  PIN o[395]
    DIRECTION OUTPUT ;
    USE SIGNAL ;
    PORT
      LAYER M5 ;
        RECT  4.848 0 4.872 0.084 ;
    END
  END o[395]
  PIN o[396]
    DIRECTION OUTPUT ;
    USE SIGNAL ;
    PORT
      LAYER M5 ;
        RECT  4.944 0 4.968 0.084 ;
    END
  END o[396]
  PIN o[397]
    DIRECTION OUTPUT ;
    USE SIGNAL ;
    PORT
      LAYER M5 ;
        RECT  5.04 0 5.064 0.084 ;
    END
  END o[397]
  PIN o[398]
    DIRECTION OUTPUT ;
    USE SIGNAL ;
    PORT
      LAYER M5 ;
        RECT  5.136 0 5.16 0.084 ;
    END
  END o[398]
  PIN o[399]
    DIRECTION OUTPUT ;
    USE SIGNAL ;
    PORT
      LAYER M5 ;
        RECT  5.232 0 5.256 0.084 ;
    END
  END o[399]
  PIN o[39]
    DIRECTION OUTPUT ;
    USE SIGNAL ;
    PORT
      LAYER M5 ;
        RECT  23.664 0 23.688 0.084 ;
    END
  END o[39]
  PIN o[3]
    DIRECTION OUTPUT ;
    USE SIGNAL ;
    PORT
      LAYER M5 ;
        RECT  35.568 0 35.592 0.084 ;
    END
  END o[3]
  PIN o[400]
    DIRECTION OUTPUT ;
    USE SIGNAL ;
    PORT
      LAYER M5 ;
        RECT  5.328 0 5.352 0.084 ;
    END
  END o[400]
  PIN o[401]
    DIRECTION OUTPUT ;
    USE SIGNAL ;
    PORT
      LAYER M5 ;
        RECT  5.424 0 5.448 0.084 ;
    END
  END o[401]
  PIN o[402]
    DIRECTION OUTPUT ;
    USE SIGNAL ;
    PORT
      LAYER M5 ;
        RECT  5.52 0 5.544 0.084 ;
    END
  END o[402]
  PIN o[403]
    DIRECTION OUTPUT ;
    USE SIGNAL ;
    PORT
      LAYER M5 ;
        RECT  5.616 0 5.64 0.084 ;
    END
  END o[403]
  PIN o[404]
    DIRECTION OUTPUT ;
    USE SIGNAL ;
    PORT
      LAYER M5 ;
        RECT  5.712 0 5.736 0.084 ;
    END
  END o[404]
  PIN o[405]
    DIRECTION OUTPUT ;
    USE SIGNAL ;
    PORT
      LAYER M5 ;
        RECT  5.808 0 5.832 0.084 ;
    END
  END o[405]
  PIN o[406]
    DIRECTION OUTPUT ;
    USE SIGNAL ;
    PORT
      LAYER M5 ;
        RECT  5.904 0 5.928 0.084 ;
    END
  END o[406]
  PIN o[407]
    DIRECTION OUTPUT ;
    USE SIGNAL ;
    PORT
      LAYER M5 ;
        RECT  6 0 6.024 0.084 ;
    END
  END o[407]
  PIN o[408]
    DIRECTION OUTPUT ;
    USE SIGNAL ;
    PORT
      LAYER M5 ;
        RECT  6.096 0 6.12 0.084 ;
    END
  END o[408]
  PIN o[409]
    DIRECTION OUTPUT ;
    USE SIGNAL ;
    PORT
      LAYER M5 ;
        RECT  6.192 0 6.216 0.084 ;
    END
  END o[409]
  PIN o[40]
    DIRECTION OUTPUT ;
    USE SIGNAL ;
    PORT
      LAYER M5 ;
        RECT  23.76 0 23.784 0.084 ;
    END
  END o[40]
  PIN o[410]
    DIRECTION OUTPUT ;
    USE SIGNAL ;
    PORT
      LAYER M5 ;
        RECT  6.288 0 6.312 0.084 ;
    END
  END o[410]
  PIN o[411]
    DIRECTION OUTPUT ;
    USE SIGNAL ;
    PORT
      LAYER M5 ;
        RECT  6.384 0 6.408 0.084 ;
    END
  END o[411]
  PIN o[412]
    DIRECTION OUTPUT ;
    USE SIGNAL ;
    PORT
      LAYER M5 ;
        RECT  6.48 0 6.504 0.084 ;
    END
  END o[412]
  PIN o[413]
    DIRECTION OUTPUT ;
    USE SIGNAL ;
    PORT
      LAYER M5 ;
        RECT  6.576 0 6.6 0.084 ;
    END
  END o[413]
  PIN o[414]
    DIRECTION OUTPUT ;
    USE SIGNAL ;
    PORT
      LAYER M5 ;
        RECT  6.672 0 6.696 0.084 ;
    END
  END o[414]
  PIN o[415]
    DIRECTION OUTPUT ;
    USE SIGNAL ;
    PORT
      LAYER M5 ;
        RECT  6.768 0 6.792 0.084 ;
    END
  END o[415]
  PIN o[416]
    DIRECTION OUTPUT ;
    USE SIGNAL ;
    PORT
      LAYER M5 ;
        RECT  0.72 0 0.744 0.084 ;
    END
  END o[416]
  PIN o[417]
    DIRECTION OUTPUT ;
    USE SIGNAL ;
    PORT
      LAYER M5 ;
        RECT  0.816 0 0.84 0.084 ;
    END
  END o[417]
  PIN o[418]
    DIRECTION OUTPUT ;
    USE SIGNAL ;
    PORT
      LAYER M5 ;
        RECT  0.912 0 0.936 0.084 ;
    END
  END o[418]
  PIN o[419]
    DIRECTION OUTPUT ;
    USE SIGNAL ;
    PORT
      LAYER M5 ;
        RECT  1.008 0 1.032 0.084 ;
    END
  END o[419]
  PIN o[41]
    DIRECTION OUTPUT ;
    USE SIGNAL ;
    PORT
      LAYER M5 ;
        RECT  23.856 0 23.88 0.084 ;
    END
  END o[41]
  PIN o[420]
    DIRECTION OUTPUT ;
    USE SIGNAL ;
    PORT
      LAYER M5 ;
        RECT  1.104 0 1.128 0.084 ;
    END
  END o[420]
  PIN o[421]
    DIRECTION OUTPUT ;
    USE SIGNAL ;
    PORT
      LAYER M5 ;
        RECT  1.2 0 1.224 0.084 ;
    END
  END o[421]
  PIN o[422]
    DIRECTION OUTPUT ;
    USE SIGNAL ;
    PORT
      LAYER M5 ;
        RECT  1.296 0 1.32 0.084 ;
    END
  END o[422]
  PIN o[423]
    DIRECTION OUTPUT ;
    USE SIGNAL ;
    PORT
      LAYER M5 ;
        RECT  1.392 0 1.416 0.084 ;
    END
  END o[423]
  PIN o[424]
    DIRECTION OUTPUT ;
    USE SIGNAL ;
    PORT
      LAYER M5 ;
        RECT  1.488 0 1.512 0.084 ;
    END
  END o[424]
  PIN o[425]
    DIRECTION OUTPUT ;
    USE SIGNAL ;
    PORT
      LAYER M5 ;
        RECT  1.584 0 1.608 0.084 ;
    END
  END o[425]
  PIN o[426]
    DIRECTION OUTPUT ;
    USE SIGNAL ;
    PORT
      LAYER M5 ;
        RECT  1.68 0 1.704 0.084 ;
    END
  END o[426]
  PIN o[427]
    DIRECTION OUTPUT ;
    USE SIGNAL ;
    PORT
      LAYER M5 ;
        RECT  1.776 0 1.8 0.084 ;
    END
  END o[427]
  PIN o[428]
    DIRECTION OUTPUT ;
    USE SIGNAL ;
    PORT
      LAYER M5 ;
        RECT  1.872 0 1.896 0.084 ;
    END
  END o[428]
  PIN o[429]
    DIRECTION OUTPUT ;
    USE SIGNAL ;
    PORT
      LAYER M5 ;
        RECT  1.968 0 1.992 0.084 ;
    END
  END o[429]
  PIN o[42]
    DIRECTION OUTPUT ;
    USE SIGNAL ;
    PORT
      LAYER M5 ;
        RECT  23.952 0 23.976 0.084 ;
    END
  END o[42]
  PIN o[430]
    DIRECTION OUTPUT ;
    USE SIGNAL ;
    PORT
      LAYER M5 ;
        RECT  2.064 0 2.088 0.084 ;
    END
  END o[430]
  PIN o[431]
    DIRECTION OUTPUT ;
    USE SIGNAL ;
    PORT
      LAYER M5 ;
        RECT  2.16 0 2.184 0.084 ;
    END
  END o[431]
  PIN o[432]
    DIRECTION OUTPUT ;
    USE SIGNAL ;
    PORT
      LAYER M5 ;
        RECT  2.256 0 2.28 0.084 ;
    END
  END o[432]
  PIN o[433]
    DIRECTION OUTPUT ;
    USE SIGNAL ;
    PORT
      LAYER M5 ;
        RECT  2.352 0 2.376 0.084 ;
    END
  END o[433]
  PIN o[434]
    DIRECTION OUTPUT ;
    USE SIGNAL ;
    PORT
      LAYER M5 ;
        RECT  2.448 0 2.472 0.084 ;
    END
  END o[434]
  PIN o[435]
    DIRECTION OUTPUT ;
    USE SIGNAL ;
    PORT
      LAYER M5 ;
        RECT  2.544 0 2.568 0.084 ;
    END
  END o[435]
  PIN o[436]
    DIRECTION OUTPUT ;
    USE SIGNAL ;
    PORT
      LAYER M5 ;
        RECT  2.64 0 2.664 0.084 ;
    END
  END o[436]
  PIN o[437]
    DIRECTION OUTPUT ;
    USE SIGNAL ;
    PORT
      LAYER M5 ;
        RECT  2.736 0 2.76 0.084 ;
    END
  END o[437]
  PIN o[438]
    DIRECTION OUTPUT ;
    USE SIGNAL ;
    PORT
      LAYER M5 ;
        RECT  2.832 0 2.856 0.084 ;
    END
  END o[438]
  PIN o[439]
    DIRECTION OUTPUT ;
    USE SIGNAL ;
    PORT
      LAYER M5 ;
        RECT  2.928 0 2.952 0.084 ;
    END
  END o[439]
  PIN o[43]
    DIRECTION OUTPUT ;
    USE SIGNAL ;
    PORT
      LAYER M5 ;
        RECT  24.048 0 24.072 0.084 ;
    END
  END o[43]
  PIN o[440]
    DIRECTION OUTPUT ;
    USE SIGNAL ;
    PORT
      LAYER M5 ;
        RECT  3.024 0 3.048 0.084 ;
    END
  END o[440]
  PIN o[441]
    DIRECTION OUTPUT ;
    USE SIGNAL ;
    PORT
      LAYER M5 ;
        RECT  3.12 0 3.144 0.084 ;
    END
  END o[441]
  PIN o[442]
    DIRECTION OUTPUT ;
    USE SIGNAL ;
    PORT
      LAYER M5 ;
        RECT  3.216 0 3.24 0.084 ;
    END
  END o[442]
  PIN o[443]
    DIRECTION OUTPUT ;
    USE SIGNAL ;
    PORT
      LAYER M5 ;
        RECT  3.312 0 3.336 0.084 ;
    END
  END o[443]
  PIN o[444]
    DIRECTION OUTPUT ;
    USE SIGNAL ;
    PORT
      LAYER M5 ;
        RECT  3.408 0 3.432 0.084 ;
    END
  END o[444]
  PIN o[445]
    DIRECTION OUTPUT ;
    USE SIGNAL ;
    PORT
      LAYER M5 ;
        RECT  3.504 0 3.528 0.084 ;
    END
  END o[445]
  PIN o[446]
    DIRECTION OUTPUT ;
    USE SIGNAL ;
    PORT
      LAYER M5 ;
        RECT  3.6 0 3.624 0.084 ;
    END
  END o[446]
  PIN o[447]
    DIRECTION OUTPUT ;
    USE SIGNAL ;
    PORT
      LAYER M5 ;
        RECT  3.696 0 3.72 0.084 ;
    END
  END o[447]
  PIN o[448]
    DIRECTION OUTPUT ;
    USE SIGNAL ;
    PORT
      LAYER M5 ;
        RECT  9.936 0 9.96 0.084 ;
    END
  END o[448]
  PIN o[449]
    DIRECTION OUTPUT ;
    USE SIGNAL ;
    PORT
      LAYER M5 ;
        RECT  10.032 0 10.056 0.084 ;
    END
  END o[449]
  PIN o[44]
    DIRECTION OUTPUT ;
    USE SIGNAL ;
    PORT
      LAYER M5 ;
        RECT  24.144 0 24.168 0.084 ;
    END
  END o[44]
  PIN o[450]
    DIRECTION OUTPUT ;
    USE SIGNAL ;
    PORT
      LAYER M5 ;
        RECT  10.128 0 10.152 0.084 ;
    END
  END o[450]
  PIN o[451]
    DIRECTION OUTPUT ;
    USE SIGNAL ;
    PORT
      LAYER M5 ;
        RECT  10.224 0 10.248 0.084 ;
    END
  END o[451]
  PIN o[452]
    DIRECTION OUTPUT ;
    USE SIGNAL ;
    PORT
      LAYER M5 ;
        RECT  10.32 0 10.344 0.084 ;
    END
  END o[452]
  PIN o[453]
    DIRECTION OUTPUT ;
    USE SIGNAL ;
    PORT
      LAYER M5 ;
        RECT  10.416 0 10.44 0.084 ;
    END
  END o[453]
  PIN o[454]
    DIRECTION OUTPUT ;
    USE SIGNAL ;
    PORT
      LAYER M5 ;
        RECT  10.512 0 10.536 0.084 ;
    END
  END o[454]
  PIN o[455]
    DIRECTION OUTPUT ;
    USE SIGNAL ;
    PORT
      LAYER M5 ;
        RECT  10.608 0 10.632 0.084 ;
    END
  END o[455]
  PIN o[456]
    DIRECTION OUTPUT ;
    USE SIGNAL ;
    PORT
      LAYER M5 ;
        RECT  10.704 0 10.728 0.084 ;
    END
  END o[456]
  PIN o[457]
    DIRECTION OUTPUT ;
    USE SIGNAL ;
    PORT
      LAYER M5 ;
        RECT  10.8 0 10.824 0.084 ;
    END
  END o[457]
  PIN o[458]
    DIRECTION OUTPUT ;
    USE SIGNAL ;
    PORT
      LAYER M5 ;
        RECT  10.896 0 10.92 0.084 ;
    END
  END o[458]
  PIN o[459]
    DIRECTION OUTPUT ;
    USE SIGNAL ;
    PORT
      LAYER M5 ;
        RECT  10.992 0 11.016 0.084 ;
    END
  END o[459]
  PIN o[45]
    DIRECTION OUTPUT ;
    USE SIGNAL ;
    PORT
      LAYER M5 ;
        RECT  24.24 0 24.264 0.084 ;
    END
  END o[45]
  PIN o[460]
    DIRECTION OUTPUT ;
    USE SIGNAL ;
    PORT
      LAYER M5 ;
        RECT  11.088 0 11.112 0.084 ;
    END
  END o[460]
  PIN o[461]
    DIRECTION OUTPUT ;
    USE SIGNAL ;
    PORT
      LAYER M5 ;
        RECT  11.184 0 11.208 0.084 ;
    END
  END o[461]
  PIN o[462]
    DIRECTION OUTPUT ;
    USE SIGNAL ;
    PORT
      LAYER M5 ;
        RECT  11.28 0 11.304 0.084 ;
    END
  END o[462]
  PIN o[463]
    DIRECTION OUTPUT ;
    USE SIGNAL ;
    PORT
      LAYER M5 ;
        RECT  11.376 0 11.4 0.084 ;
    END
  END o[463]
  PIN o[464]
    DIRECTION OUTPUT ;
    USE SIGNAL ;
    PORT
      LAYER M5 ;
        RECT  11.472 0 11.496 0.084 ;
    END
  END o[464]
  PIN o[465]
    DIRECTION OUTPUT ;
    USE SIGNAL ;
    PORT
      LAYER M5 ;
        RECT  11.568 0 11.592 0.084 ;
    END
  END o[465]
  PIN o[466]
    DIRECTION OUTPUT ;
    USE SIGNAL ;
    PORT
      LAYER M5 ;
        RECT  11.664 0 11.688 0.084 ;
    END
  END o[466]
  PIN o[467]
    DIRECTION OUTPUT ;
    USE SIGNAL ;
    PORT
      LAYER M5 ;
        RECT  11.76 0 11.784 0.084 ;
    END
  END o[467]
  PIN o[468]
    DIRECTION OUTPUT ;
    USE SIGNAL ;
    PORT
      LAYER M5 ;
        RECT  11.856 0 11.88 0.084 ;
    END
  END o[468]
  PIN o[469]
    DIRECTION OUTPUT ;
    USE SIGNAL ;
    PORT
      LAYER M5 ;
        RECT  11.952 0 11.976 0.084 ;
    END
  END o[469]
  PIN o[46]
    DIRECTION OUTPUT ;
    USE SIGNAL ;
    PORT
      LAYER M5 ;
        RECT  24.336 0 24.36 0.084 ;
    END
  END o[46]
  PIN o[470]
    DIRECTION OUTPUT ;
    USE SIGNAL ;
    PORT
      LAYER M5 ;
        RECT  12.048 0 12.072 0.084 ;
    END
  END o[470]
  PIN o[471]
    DIRECTION OUTPUT ;
    USE SIGNAL ;
    PORT
      LAYER M5 ;
        RECT  12.144 0 12.168 0.084 ;
    END
  END o[471]
  PIN o[472]
    DIRECTION OUTPUT ;
    USE SIGNAL ;
    PORT
      LAYER M5 ;
        RECT  12.24 0 12.264 0.084 ;
    END
  END o[472]
  PIN o[473]
    DIRECTION OUTPUT ;
    USE SIGNAL ;
    PORT
      LAYER M5 ;
        RECT  12.336 0 12.36 0.084 ;
    END
  END o[473]
  PIN o[474]
    DIRECTION OUTPUT ;
    USE SIGNAL ;
    PORT
      LAYER M5 ;
        RECT  12.432 0 12.456 0.084 ;
    END
  END o[474]
  PIN o[475]
    DIRECTION OUTPUT ;
    USE SIGNAL ;
    PORT
      LAYER M5 ;
        RECT  12.528 0 12.552 0.084 ;
    END
  END o[475]
  PIN o[476]
    DIRECTION OUTPUT ;
    USE SIGNAL ;
    PORT
      LAYER M5 ;
        RECT  12.624 0 12.648 0.084 ;
    END
  END o[476]
  PIN o[477]
    DIRECTION OUTPUT ;
    USE SIGNAL ;
    PORT
      LAYER M5 ;
        RECT  12.72 0 12.744 0.084 ;
    END
  END o[477]
  PIN o[478]
    DIRECTION OUTPUT ;
    USE SIGNAL ;
    PORT
      LAYER M5 ;
        RECT  12.816 0 12.84 0.084 ;
    END
  END o[478]
  PIN o[479]
    DIRECTION OUTPUT ;
    USE SIGNAL ;
    PORT
      LAYER M5 ;
        RECT  12.912 0 12.936 0.084 ;
    END
  END o[479]
  PIN o[47]
    DIRECTION OUTPUT ;
    USE SIGNAL ;
    PORT
      LAYER M5 ;
        RECT  24.432 0 24.456 0.084 ;
    END
  END o[47]
  PIN o[480]
    DIRECTION OUTPUT ;
    USE SIGNAL ;
    PORT
      LAYER M5 ;
        RECT  16.08 0 16.104 0.084 ;
    END
  END o[480]
  PIN o[481]
    DIRECTION OUTPUT ;
    USE SIGNAL ;
    PORT
      LAYER M5 ;
        RECT  16.176 0 16.2 0.084 ;
    END
  END o[481]
  PIN o[482]
    DIRECTION OUTPUT ;
    USE SIGNAL ;
    PORT
      LAYER M5 ;
        RECT  16.272 0 16.296 0.084 ;
    END
  END o[482]
  PIN o[483]
    DIRECTION OUTPUT ;
    USE SIGNAL ;
    PORT
      LAYER M5 ;
        RECT  16.368 0 16.392 0.084 ;
    END
  END o[483]
  PIN o[484]
    DIRECTION OUTPUT ;
    USE SIGNAL ;
    PORT
      LAYER M5 ;
        RECT  16.464 0 16.488 0.084 ;
    END
  END o[484]
  PIN o[485]
    DIRECTION OUTPUT ;
    USE SIGNAL ;
    PORT
      LAYER M5 ;
        RECT  16.56 0 16.584 0.084 ;
    END
  END o[485]
  PIN o[486]
    DIRECTION OUTPUT ;
    USE SIGNAL ;
    PORT
      LAYER M5 ;
        RECT  16.656 0 16.68 0.084 ;
    END
  END o[486]
  PIN o[487]
    DIRECTION OUTPUT ;
    USE SIGNAL ;
    PORT
      LAYER M5 ;
        RECT  16.752 0 16.776 0.084 ;
    END
  END o[487]
  PIN o[488]
    DIRECTION OUTPUT ;
    USE SIGNAL ;
    PORT
      LAYER M5 ;
        RECT  16.848 0 16.872 0.084 ;
    END
  END o[488]
  PIN o[489]
    DIRECTION OUTPUT ;
    USE SIGNAL ;
    PORT
      LAYER M5 ;
        RECT  16.944 0 16.968 0.084 ;
    END
  END o[489]
  PIN o[48]
    DIRECTION OUTPUT ;
    USE SIGNAL ;
    PORT
      LAYER M5 ;
        RECT  24.528 0 24.552 0.084 ;
    END
  END o[48]
  PIN o[490]
    DIRECTION OUTPUT ;
    USE SIGNAL ;
    PORT
      LAYER M5 ;
        RECT  17.04 0 17.064 0.084 ;
    END
  END o[490]
  PIN o[491]
    DIRECTION OUTPUT ;
    USE SIGNAL ;
    PORT
      LAYER M5 ;
        RECT  17.136 0 17.16 0.084 ;
    END
  END o[491]
  PIN o[492]
    DIRECTION OUTPUT ;
    USE SIGNAL ;
    PORT
      LAYER M5 ;
        RECT  17.232 0 17.256 0.084 ;
    END
  END o[492]
  PIN o[493]
    DIRECTION OUTPUT ;
    USE SIGNAL ;
    PORT
      LAYER M5 ;
        RECT  17.328 0 17.352 0.084 ;
    END
  END o[493]
  PIN o[494]
    DIRECTION OUTPUT ;
    USE SIGNAL ;
    PORT
      LAYER M5 ;
        RECT  17.424 0 17.448 0.084 ;
    END
  END o[494]
  PIN o[495]
    DIRECTION OUTPUT ;
    USE SIGNAL ;
    PORT
      LAYER M5 ;
        RECT  17.52 0 17.544 0.084 ;
    END
  END o[495]
  PIN o[496]
    DIRECTION OUTPUT ;
    USE SIGNAL ;
    PORT
      LAYER M5 ;
        RECT  17.616 0 17.64 0.084 ;
    END
  END o[496]
  PIN o[497]
    DIRECTION OUTPUT ;
    USE SIGNAL ;
    PORT
      LAYER M5 ;
        RECT  17.712 0 17.736 0.084 ;
    END
  END o[497]
  PIN o[498]
    DIRECTION OUTPUT ;
    USE SIGNAL ;
    PORT
      LAYER M5 ;
        RECT  17.808 0 17.832 0.084 ;
    END
  END o[498]
  PIN o[499]
    DIRECTION OUTPUT ;
    USE SIGNAL ;
    PORT
      LAYER M5 ;
        RECT  17.904 0 17.928 0.084 ;
    END
  END o[499]
  PIN o[49]
    DIRECTION OUTPUT ;
    USE SIGNAL ;
    PORT
      LAYER M5 ;
        RECT  24.624 0 24.648 0.084 ;
    END
  END o[49]
  PIN o[4]
    DIRECTION OUTPUT ;
    USE SIGNAL ;
    PORT
      LAYER M5 ;
        RECT  35.664 0 35.688 0.084 ;
    END
  END o[4]
  PIN o[500]
    DIRECTION OUTPUT ;
    USE SIGNAL ;
    PORT
      LAYER M5 ;
        RECT  18 0 18.024 0.084 ;
    END
  END o[500]
  PIN o[501]
    DIRECTION OUTPUT ;
    USE SIGNAL ;
    PORT
      LAYER M5 ;
        RECT  18.096 0 18.12 0.084 ;
    END
  END o[501]
  PIN o[502]
    DIRECTION OUTPUT ;
    USE SIGNAL ;
    PORT
      LAYER M5 ;
        RECT  18.192 0 18.216 0.084 ;
    END
  END o[502]
  PIN o[503]
    DIRECTION OUTPUT ;
    USE SIGNAL ;
    PORT
      LAYER M5 ;
        RECT  18.288 0 18.312 0.084 ;
    END
  END o[503]
  PIN o[504]
    DIRECTION OUTPUT ;
    USE SIGNAL ;
    PORT
      LAYER M5 ;
        RECT  18.384 0 18.408 0.084 ;
    END
  END o[504]
  PIN o[505]
    DIRECTION OUTPUT ;
    USE SIGNAL ;
    PORT
      LAYER M5 ;
        RECT  18.48 0 18.504 0.084 ;
    END
  END o[505]
  PIN o[506]
    DIRECTION OUTPUT ;
    USE SIGNAL ;
    PORT
      LAYER M5 ;
        RECT  18.576 0 18.6 0.084 ;
    END
  END o[506]
  PIN o[507]
    DIRECTION OUTPUT ;
    USE SIGNAL ;
    PORT
      LAYER M5 ;
        RECT  18.672 0 18.696 0.084 ;
    END
  END o[507]
  PIN o[508]
    DIRECTION OUTPUT ;
    USE SIGNAL ;
    PORT
      LAYER M5 ;
        RECT  18.768 0 18.792 0.084 ;
    END
  END o[508]
  PIN o[509]
    DIRECTION OUTPUT ;
    USE SIGNAL ;
    PORT
      LAYER M5 ;
        RECT  18.864 0 18.888 0.084 ;
    END
  END o[509]
  PIN o[50]
    DIRECTION OUTPUT ;
    USE SIGNAL ;
    PORT
      LAYER M5 ;
        RECT  24.72 0 24.744 0.084 ;
    END
  END o[50]
  PIN o[510]
    DIRECTION OUTPUT ;
    USE SIGNAL ;
    PORT
      LAYER M5 ;
        RECT  18.96 0 18.984 0.084 ;
    END
  END o[510]
  PIN o[511]
    DIRECTION OUTPUT ;
    USE SIGNAL ;
    PORT
      LAYER M5 ;
        RECT  19.056 0 19.08 0.084 ;
    END
  END o[511]
  PIN o[512]
    DIRECTION OUTPUT ;
    USE SIGNAL ;
    PORT
      LAYER M5 ;
        RECT  58.32 0 58.344 0.084 ;
    END
  END o[512]
  PIN o[513]
    DIRECTION OUTPUT ;
    USE SIGNAL ;
    PORT
      LAYER M5 ;
        RECT  58.416 0 58.44 0.084 ;
    END
  END o[513]
  PIN o[514]
    DIRECTION OUTPUT ;
    USE SIGNAL ;
    PORT
      LAYER M5 ;
        RECT  58.512 0 58.536 0.084 ;
    END
  END o[514]
  PIN o[515]
    DIRECTION OUTPUT ;
    USE SIGNAL ;
    PORT
      LAYER M5 ;
        RECT  58.608 0 58.632 0.084 ;
    END
  END o[515]
  PIN o[516]
    DIRECTION OUTPUT ;
    USE SIGNAL ;
    PORT
      LAYER M5 ;
        RECT  58.704 0 58.728 0.084 ;
    END
  END o[516]
  PIN o[517]
    DIRECTION OUTPUT ;
    USE SIGNAL ;
    PORT
      LAYER M5 ;
        RECT  58.8 0 58.824 0.084 ;
    END
  END o[517]
  PIN o[518]
    DIRECTION OUTPUT ;
    USE SIGNAL ;
    PORT
      LAYER M5 ;
        RECT  58.896 0 58.92 0.084 ;
    END
  END o[518]
  PIN o[519]
    DIRECTION OUTPUT ;
    USE SIGNAL ;
    PORT
      LAYER M5 ;
        RECT  58.992 0 59.016 0.084 ;
    END
  END o[519]
  PIN o[51]
    DIRECTION OUTPUT ;
    USE SIGNAL ;
    PORT
      LAYER M5 ;
        RECT  24.816 0 24.84 0.084 ;
    END
  END o[51]
  PIN o[520]
    DIRECTION OUTPUT ;
    USE SIGNAL ;
    PORT
      LAYER M5 ;
        RECT  59.088 0 59.112 0.084 ;
    END
  END o[520]
  PIN o[521]
    DIRECTION OUTPUT ;
    USE SIGNAL ;
    PORT
      LAYER M5 ;
        RECT  59.184 0 59.208 0.084 ;
    END
  END o[521]
  PIN o[522]
    DIRECTION OUTPUT ;
    USE SIGNAL ;
    PORT
      LAYER M5 ;
        RECT  59.28 0 59.304 0.084 ;
    END
  END o[522]
  PIN o[523]
    DIRECTION OUTPUT ;
    USE SIGNAL ;
    PORT
      LAYER M5 ;
        RECT  59.376 0 59.4 0.084 ;
    END
  END o[523]
  PIN o[524]
    DIRECTION OUTPUT ;
    USE SIGNAL ;
    PORT
      LAYER M5 ;
        RECT  59.472 0 59.496 0.084 ;
    END
  END o[524]
  PIN o[525]
    DIRECTION OUTPUT ;
    USE SIGNAL ;
    PORT
      LAYER M5 ;
        RECT  59.568 0 59.592 0.084 ;
    END
  END o[525]
  PIN o[526]
    DIRECTION OUTPUT ;
    USE SIGNAL ;
    PORT
      LAYER M5 ;
        RECT  59.664 0 59.688 0.084 ;
    END
  END o[526]
  PIN o[527]
    DIRECTION OUTPUT ;
    USE SIGNAL ;
    PORT
      LAYER M5 ;
        RECT  59.76 0 59.784 0.084 ;
    END
  END o[527]
  PIN o[528]
    DIRECTION OUTPUT ;
    USE SIGNAL ;
    PORT
      LAYER M5 ;
        RECT  59.856 0 59.88 0.084 ;
    END
  END o[528]
  PIN o[529]
    DIRECTION OUTPUT ;
    USE SIGNAL ;
    PORT
      LAYER M5 ;
        RECT  59.952 0 59.976 0.084 ;
    END
  END o[529]
  PIN o[52]
    DIRECTION OUTPUT ;
    USE SIGNAL ;
    PORT
      LAYER M5 ;
        RECT  24.912 0 24.936 0.084 ;
    END
  END o[52]
  PIN o[530]
    DIRECTION OUTPUT ;
    USE SIGNAL ;
    PORT
      LAYER M5 ;
        RECT  60.048 0 60.072 0.084 ;
    END
  END o[530]
  PIN o[531]
    DIRECTION OUTPUT ;
    USE SIGNAL ;
    PORT
      LAYER M5 ;
        RECT  60.144 0 60.168 0.084 ;
    END
  END o[531]
  PIN o[532]
    DIRECTION OUTPUT ;
    USE SIGNAL ;
    PORT
      LAYER M5 ;
        RECT  60.24 0 60.264 0.084 ;
    END
  END o[532]
  PIN o[533]
    DIRECTION OUTPUT ;
    USE SIGNAL ;
    PORT
      LAYER M5 ;
        RECT  60.336 0 60.36 0.084 ;
    END
  END o[533]
  PIN o[534]
    DIRECTION OUTPUT ;
    USE SIGNAL ;
    PORT
      LAYER M5 ;
        RECT  60.432 0 60.456 0.084 ;
    END
  END o[534]
  PIN o[535]
    DIRECTION OUTPUT ;
    USE SIGNAL ;
    PORT
      LAYER M5 ;
        RECT  60.528 0 60.552 0.084 ;
    END
  END o[535]
  PIN o[536]
    DIRECTION OUTPUT ;
    USE SIGNAL ;
    PORT
      LAYER M5 ;
        RECT  60.624 0 60.648 0.084 ;
    END
  END o[536]
  PIN o[537]
    DIRECTION OUTPUT ;
    USE SIGNAL ;
    PORT
      LAYER M5 ;
        RECT  60.72 0 60.744 0.084 ;
    END
  END o[537]
  PIN o[538]
    DIRECTION OUTPUT ;
    USE SIGNAL ;
    PORT
      LAYER M5 ;
        RECT  60.816 0 60.84 0.084 ;
    END
  END o[538]
  PIN o[539]
    DIRECTION OUTPUT ;
    USE SIGNAL ;
    PORT
      LAYER M5 ;
        RECT  60.912 0 60.936 0.084 ;
    END
  END o[539]
  PIN o[53]
    DIRECTION OUTPUT ;
    USE SIGNAL ;
    PORT
      LAYER M5 ;
        RECT  25.008 0 25.032 0.084 ;
    END
  END o[53]
  PIN o[540]
    DIRECTION OUTPUT ;
    USE SIGNAL ;
    PORT
      LAYER M5 ;
        RECT  61.008 0 61.032 0.084 ;
    END
  END o[540]
  PIN o[541]
    DIRECTION OUTPUT ;
    USE SIGNAL ;
    PORT
      LAYER M5 ;
        RECT  61.104 0 61.128 0.084 ;
    END
  END o[541]
  PIN o[542]
    DIRECTION OUTPUT ;
    USE SIGNAL ;
    PORT
      LAYER M5 ;
        RECT  61.2 0 61.224 0.084 ;
    END
  END o[542]
  PIN o[543]
    DIRECTION OUTPUT ;
    USE SIGNAL ;
    PORT
      LAYER M5 ;
        RECT  61.296 0 61.32 0.084 ;
    END
  END o[543]
  PIN o[544]
    DIRECTION OUTPUT ;
    USE SIGNAL ;
    PORT
      LAYER M5 ;
        RECT  13.008 0 13.032 0.084 ;
    END
  END o[544]
  PIN o[545]
    DIRECTION OUTPUT ;
    USE SIGNAL ;
    PORT
      LAYER M5 ;
        RECT  13.104 0 13.128 0.084 ;
    END
  END o[545]
  PIN o[546]
    DIRECTION OUTPUT ;
    USE SIGNAL ;
    PORT
      LAYER M5 ;
        RECT  13.2 0 13.224 0.084 ;
    END
  END o[546]
  PIN o[547]
    DIRECTION OUTPUT ;
    USE SIGNAL ;
    PORT
      LAYER M5 ;
        RECT  13.296 0 13.32 0.084 ;
    END
  END o[547]
  PIN o[548]
    DIRECTION OUTPUT ;
    USE SIGNAL ;
    PORT
      LAYER M5 ;
        RECT  13.392 0 13.416 0.084 ;
    END
  END o[548]
  PIN o[549]
    DIRECTION OUTPUT ;
    USE SIGNAL ;
    PORT
      LAYER M5 ;
        RECT  13.488 0 13.512 0.084 ;
    END
  END o[549]
  PIN o[54]
    DIRECTION OUTPUT ;
    USE SIGNAL ;
    PORT
      LAYER M5 ;
        RECT  25.104 0 25.128 0.084 ;
    END
  END o[54]
  PIN o[550]
    DIRECTION OUTPUT ;
    USE SIGNAL ;
    PORT
      LAYER M5 ;
        RECT  13.584 0 13.608 0.084 ;
    END
  END o[550]
  PIN o[551]
    DIRECTION OUTPUT ;
    USE SIGNAL ;
    PORT
      LAYER M5 ;
        RECT  13.68 0 13.704 0.084 ;
    END
  END o[551]
  PIN o[552]
    DIRECTION OUTPUT ;
    USE SIGNAL ;
    PORT
      LAYER M5 ;
        RECT  13.776 0 13.8 0.084 ;
    END
  END o[552]
  PIN o[553]
    DIRECTION OUTPUT ;
    USE SIGNAL ;
    PORT
      LAYER M5 ;
        RECT  13.872 0 13.896 0.084 ;
    END
  END o[553]
  PIN o[554]
    DIRECTION OUTPUT ;
    USE SIGNAL ;
    PORT
      LAYER M5 ;
        RECT  13.968 0 13.992 0.084 ;
    END
  END o[554]
  PIN o[555]
    DIRECTION OUTPUT ;
    USE SIGNAL ;
    PORT
      LAYER M5 ;
        RECT  14.064 0 14.088 0.084 ;
    END
  END o[555]
  PIN o[556]
    DIRECTION OUTPUT ;
    USE SIGNAL ;
    PORT
      LAYER M5 ;
        RECT  14.16 0 14.184 0.084 ;
    END
  END o[556]
  PIN o[557]
    DIRECTION OUTPUT ;
    USE SIGNAL ;
    PORT
      LAYER M5 ;
        RECT  14.256 0 14.28 0.084 ;
    END
  END o[557]
  PIN o[558]
    DIRECTION OUTPUT ;
    USE SIGNAL ;
    PORT
      LAYER M5 ;
        RECT  14.352 0 14.376 0.084 ;
    END
  END o[558]
  PIN o[559]
    DIRECTION OUTPUT ;
    USE SIGNAL ;
    PORT
      LAYER M5 ;
        RECT  14.448 0 14.472 0.084 ;
    END
  END o[559]
  PIN o[55]
    DIRECTION OUTPUT ;
    USE SIGNAL ;
    PORT
      LAYER M5 ;
        RECT  25.2 0 25.224 0.084 ;
    END
  END o[55]
  PIN o[560]
    DIRECTION OUTPUT ;
    USE SIGNAL ;
    PORT
      LAYER M5 ;
        RECT  14.544 0 14.568 0.084 ;
    END
  END o[560]
  PIN o[561]
    DIRECTION OUTPUT ;
    USE SIGNAL ;
    PORT
      LAYER M5 ;
        RECT  14.64 0 14.664 0.084 ;
    END
  END o[561]
  PIN o[562]
    DIRECTION OUTPUT ;
    USE SIGNAL ;
    PORT
      LAYER M5 ;
        RECT  14.736 0 14.76 0.084 ;
    END
  END o[562]
  PIN o[563]
    DIRECTION OUTPUT ;
    USE SIGNAL ;
    PORT
      LAYER M5 ;
        RECT  14.832 0 14.856 0.084 ;
    END
  END o[563]
  PIN o[564]
    DIRECTION OUTPUT ;
    USE SIGNAL ;
    PORT
      LAYER M5 ;
        RECT  14.928 0 14.952 0.084 ;
    END
  END o[564]
  PIN o[565]
    DIRECTION OUTPUT ;
    USE SIGNAL ;
    PORT
      LAYER M5 ;
        RECT  15.024 0 15.048 0.084 ;
    END
  END o[565]
  PIN o[566]
    DIRECTION OUTPUT ;
    USE SIGNAL ;
    PORT
      LAYER M5 ;
        RECT  15.12 0 15.144 0.084 ;
    END
  END o[566]
  PIN o[567]
    DIRECTION OUTPUT ;
    USE SIGNAL ;
    PORT
      LAYER M5 ;
        RECT  15.216 0 15.24 0.084 ;
    END
  END o[567]
  PIN o[568]
    DIRECTION OUTPUT ;
    USE SIGNAL ;
    PORT
      LAYER M5 ;
        RECT  15.312 0 15.336 0.084 ;
    END
  END o[568]
  PIN o[569]
    DIRECTION OUTPUT ;
    USE SIGNAL ;
    PORT
      LAYER M5 ;
        RECT  15.408 0 15.432 0.084 ;
    END
  END o[569]
  PIN o[56]
    DIRECTION OUTPUT ;
    USE SIGNAL ;
    PORT
      LAYER M5 ;
        RECT  25.296 0 25.32 0.084 ;
    END
  END o[56]
  PIN o[570]
    DIRECTION OUTPUT ;
    USE SIGNAL ;
    PORT
      LAYER M5 ;
        RECT  15.504 0 15.528 0.084 ;
    END
  END o[570]
  PIN o[571]
    DIRECTION OUTPUT ;
    USE SIGNAL ;
    PORT
      LAYER M5 ;
        RECT  15.6 0 15.624 0.084 ;
    END
  END o[571]
  PIN o[572]
    DIRECTION OUTPUT ;
    USE SIGNAL ;
    PORT
      LAYER M5 ;
        RECT  15.696 0 15.72 0.084 ;
    END
  END o[572]
  PIN o[573]
    DIRECTION OUTPUT ;
    USE SIGNAL ;
    PORT
      LAYER M5 ;
        RECT  15.792 0 15.816 0.084 ;
    END
  END o[573]
  PIN o[574]
    DIRECTION OUTPUT ;
    USE SIGNAL ;
    PORT
      LAYER M5 ;
        RECT  15.888 0 15.912 0.084 ;
    END
  END o[574]
  PIN o[575]
    DIRECTION OUTPUT ;
    USE SIGNAL ;
    PORT
      LAYER M5 ;
        RECT  15.984 0 16.008 0.084 ;
    END
  END o[575]
  PIN o[576]
    DIRECTION OUTPUT ;
    USE SIGNAL ;
    PORT
      LAYER M5 ;
        RECT  6.864 0 6.888 0.084 ;
    END
  END o[576]
  PIN o[577]
    DIRECTION OUTPUT ;
    USE SIGNAL ;
    PORT
      LAYER M5 ;
        RECT  6.96 0 6.984 0.084 ;
    END
  END o[577]
  PIN o[578]
    DIRECTION OUTPUT ;
    USE SIGNAL ;
    PORT
      LAYER M5 ;
        RECT  7.056 0 7.08 0.084 ;
    END
  END o[578]
  PIN o[579]
    DIRECTION OUTPUT ;
    USE SIGNAL ;
    PORT
      LAYER M5 ;
        RECT  7.152 0 7.176 0.084 ;
    END
  END o[579]
  PIN o[57]
    DIRECTION OUTPUT ;
    USE SIGNAL ;
    PORT
      LAYER M5 ;
        RECT  25.392 0 25.416 0.084 ;
    END
  END o[57]
  PIN o[580]
    DIRECTION OUTPUT ;
    USE SIGNAL ;
    PORT
      LAYER M5 ;
        RECT  7.248 0 7.272 0.084 ;
    END
  END o[580]
  PIN o[581]
    DIRECTION OUTPUT ;
    USE SIGNAL ;
    PORT
      LAYER M5 ;
        RECT  7.344 0 7.368 0.084 ;
    END
  END o[581]
  PIN o[582]
    DIRECTION OUTPUT ;
    USE SIGNAL ;
    PORT
      LAYER M5 ;
        RECT  7.44 0 7.464 0.084 ;
    END
  END o[582]
  PIN o[583]
    DIRECTION OUTPUT ;
    USE SIGNAL ;
    PORT
      LAYER M5 ;
        RECT  7.536 0 7.56 0.084 ;
    END
  END o[583]
  PIN o[584]
    DIRECTION OUTPUT ;
    USE SIGNAL ;
    PORT
      LAYER M5 ;
        RECT  7.632 0 7.656 0.084 ;
    END
  END o[584]
  PIN o[585]
    DIRECTION OUTPUT ;
    USE SIGNAL ;
    PORT
      LAYER M5 ;
        RECT  7.728 0 7.752 0.084 ;
    END
  END o[585]
  PIN o[586]
    DIRECTION OUTPUT ;
    USE SIGNAL ;
    PORT
      LAYER M5 ;
        RECT  7.824 0 7.848 0.084 ;
    END
  END o[586]
  PIN o[587]
    DIRECTION OUTPUT ;
    USE SIGNAL ;
    PORT
      LAYER M5 ;
        RECT  7.92 0 7.944 0.084 ;
    END
  END o[587]
  PIN o[588]
    DIRECTION OUTPUT ;
    USE SIGNAL ;
    PORT
      LAYER M5 ;
        RECT  8.016 0 8.04 0.084 ;
    END
  END o[588]
  PIN o[589]
    DIRECTION OUTPUT ;
    USE SIGNAL ;
    PORT
      LAYER M5 ;
        RECT  8.112 0 8.136 0.084 ;
    END
  END o[589]
  PIN o[58]
    DIRECTION OUTPUT ;
    USE SIGNAL ;
    PORT
      LAYER M5 ;
        RECT  25.488 0 25.512 0.084 ;
    END
  END o[58]
  PIN o[590]
    DIRECTION OUTPUT ;
    USE SIGNAL ;
    PORT
      LAYER M5 ;
        RECT  8.208 0 8.232 0.084 ;
    END
  END o[590]
  PIN o[591]
    DIRECTION OUTPUT ;
    USE SIGNAL ;
    PORT
      LAYER M5 ;
        RECT  8.304 0 8.328 0.084 ;
    END
  END o[591]
  PIN o[592]
    DIRECTION OUTPUT ;
    USE SIGNAL ;
    PORT
      LAYER M5 ;
        RECT  8.4 0 8.424 0.084 ;
    END
  END o[592]
  PIN o[593]
    DIRECTION OUTPUT ;
    USE SIGNAL ;
    PORT
      LAYER M5 ;
        RECT  8.496 0 8.52 0.084 ;
    END
  END o[593]
  PIN o[594]
    DIRECTION OUTPUT ;
    USE SIGNAL ;
    PORT
      LAYER M5 ;
        RECT  8.592 0 8.616 0.084 ;
    END
  END o[594]
  PIN o[595]
    DIRECTION OUTPUT ;
    USE SIGNAL ;
    PORT
      LAYER M5 ;
        RECT  8.688 0 8.712 0.084 ;
    END
  END o[595]
  PIN o[596]
    DIRECTION OUTPUT ;
    USE SIGNAL ;
    PORT
      LAYER M5 ;
        RECT  8.784 0 8.808 0.084 ;
    END
  END o[596]
  PIN o[597]
    DIRECTION OUTPUT ;
    USE SIGNAL ;
    PORT
      LAYER M5 ;
        RECT  8.88 0 8.904 0.084 ;
    END
  END o[597]
  PIN o[598]
    DIRECTION OUTPUT ;
    USE SIGNAL ;
    PORT
      LAYER M5 ;
        RECT  8.976 0 9 0.084 ;
    END
  END o[598]
  PIN o[599]
    DIRECTION OUTPUT ;
    USE SIGNAL ;
    PORT
      LAYER M5 ;
        RECT  9.072 0 9.096 0.084 ;
    END
  END o[599]
  PIN o[59]
    DIRECTION OUTPUT ;
    USE SIGNAL ;
    PORT
      LAYER M5 ;
        RECT  25.584 0 25.608 0.084 ;
    END
  END o[59]
  PIN o[5]
    DIRECTION OUTPUT ;
    USE SIGNAL ;
    PORT
      LAYER M5 ;
        RECT  35.76 0 35.784 0.084 ;
    END
  END o[5]
  PIN o[600]
    DIRECTION OUTPUT ;
    USE SIGNAL ;
    PORT
      LAYER M5 ;
        RECT  9.168 0 9.192 0.084 ;
    END
  END o[600]
  PIN o[601]
    DIRECTION OUTPUT ;
    USE SIGNAL ;
    PORT
      LAYER M5 ;
        RECT  9.264 0 9.288 0.084 ;
    END
  END o[601]
  PIN o[602]
    DIRECTION OUTPUT ;
    USE SIGNAL ;
    PORT
      LAYER M5 ;
        RECT  9.36 0 9.384 0.084 ;
    END
  END o[602]
  PIN o[603]
    DIRECTION OUTPUT ;
    USE SIGNAL ;
    PORT
      LAYER M5 ;
        RECT  9.456 0 9.48 0.084 ;
    END
  END o[603]
  PIN o[604]
    DIRECTION OUTPUT ;
    USE SIGNAL ;
    PORT
      LAYER M5 ;
        RECT  9.552 0 9.576 0.084 ;
    END
  END o[604]
  PIN o[605]
    DIRECTION OUTPUT ;
    USE SIGNAL ;
    PORT
      LAYER M5 ;
        RECT  9.648 0 9.672 0.084 ;
    END
  END o[605]
  PIN o[606]
    DIRECTION OUTPUT ;
    USE SIGNAL ;
    PORT
      LAYER M5 ;
        RECT  9.744 0 9.768 0.084 ;
    END
  END o[606]
  PIN o[607]
    DIRECTION OUTPUT ;
    USE SIGNAL ;
    PORT
      LAYER M5 ;
        RECT  9.84 0 9.864 0.084 ;
    END
  END o[607]
  PIN o[608]
    DIRECTION OUTPUT ;
    USE SIGNAL ;
    PORT
      LAYER M5 ;
        RECT  61.392 0 61.416 0.084 ;
    END
  END o[608]
  PIN o[609]
    DIRECTION OUTPUT ;
    USE SIGNAL ;
    PORT
      LAYER M5 ;
        RECT  61.488 0 61.512 0.084 ;
    END
  END o[609]
  PIN o[60]
    DIRECTION OUTPUT ;
    USE SIGNAL ;
    PORT
      LAYER M5 ;
        RECT  25.68 0 25.704 0.084 ;
    END
  END o[60]
  PIN o[610]
    DIRECTION OUTPUT ;
    USE SIGNAL ;
    PORT
      LAYER M5 ;
        RECT  61.584 0 61.608 0.084 ;
    END
  END o[610]
  PIN o[611]
    DIRECTION OUTPUT ;
    USE SIGNAL ;
    PORT
      LAYER M5 ;
        RECT  61.68 0 61.704 0.084 ;
    END
  END o[611]
  PIN o[612]
    DIRECTION OUTPUT ;
    USE SIGNAL ;
    PORT
      LAYER M5 ;
        RECT  61.776 0 61.8 0.084 ;
    END
  END o[612]
  PIN o[613]
    DIRECTION OUTPUT ;
    USE SIGNAL ;
    PORT
      LAYER M5 ;
        RECT  61.872 0 61.896 0.084 ;
    END
  END o[613]
  PIN o[614]
    DIRECTION OUTPUT ;
    USE SIGNAL ;
    PORT
      LAYER M5 ;
        RECT  61.968 0 61.992 0.084 ;
    END
  END o[614]
  PIN o[615]
    DIRECTION OUTPUT ;
    USE SIGNAL ;
    PORT
      LAYER M5 ;
        RECT  62.064 0 62.088 0.084 ;
    END
  END o[615]
  PIN o[616]
    DIRECTION OUTPUT ;
    USE SIGNAL ;
    PORT
      LAYER M5 ;
        RECT  62.16 0 62.184 0.084 ;
    END
  END o[616]
  PIN o[617]
    DIRECTION OUTPUT ;
    USE SIGNAL ;
    PORT
      LAYER M5 ;
        RECT  62.256 0 62.28 0.084 ;
    END
  END o[617]
  PIN o[618]
    DIRECTION OUTPUT ;
    USE SIGNAL ;
    PORT
      LAYER M5 ;
        RECT  62.352 0 62.376 0.084 ;
    END
  END o[618]
  PIN o[619]
    DIRECTION OUTPUT ;
    USE SIGNAL ;
    PORT
      LAYER M5 ;
        RECT  62.448 0 62.472 0.084 ;
    END
  END o[619]
  PIN o[61]
    DIRECTION OUTPUT ;
    USE SIGNAL ;
    PORT
      LAYER M5 ;
        RECT  25.776 0 25.8 0.084 ;
    END
  END o[61]
  PIN o[620]
    DIRECTION OUTPUT ;
    USE SIGNAL ;
    PORT
      LAYER M5 ;
        RECT  62.544 0 62.568 0.084 ;
    END
  END o[620]
  PIN o[621]
    DIRECTION OUTPUT ;
    USE SIGNAL ;
    PORT
      LAYER M5 ;
        RECT  62.64 0 62.664 0.084 ;
    END
  END o[621]
  PIN o[622]
    DIRECTION OUTPUT ;
    USE SIGNAL ;
    PORT
      LAYER M5 ;
        RECT  62.736 0 62.76 0.084 ;
    END
  END o[622]
  PIN o[623]
    DIRECTION OUTPUT ;
    USE SIGNAL ;
    PORT
      LAYER M5 ;
        RECT  62.832 0 62.856 0.084 ;
    END
  END o[623]
  PIN o[62]
    DIRECTION OUTPUT ;
    USE SIGNAL ;
    PORT
      LAYER M5 ;
        RECT  25.872 0 25.896 0.084 ;
    END
  END o[62]
  PIN o[63]
    DIRECTION OUTPUT ;
    USE SIGNAL ;
    PORT
      LAYER M5 ;
        RECT  25.968 0 25.992 0.084 ;
    END
  END o[63]
  PIN o[64]
    DIRECTION OUTPUT ;
    USE SIGNAL ;
    PORT
      LAYER M5 ;
        RECT  32.208 0 32.232 0.084 ;
    END
  END o[64]
  PIN o[65]
    DIRECTION OUTPUT ;
    USE SIGNAL ;
    PORT
      LAYER M5 ;
        RECT  32.304 0 32.328 0.084 ;
    END
  END o[65]
  PIN o[66]
    DIRECTION OUTPUT ;
    USE SIGNAL ;
    PORT
      LAYER M5 ;
        RECT  32.4 0 32.424 0.084 ;
    END
  END o[66]
  PIN o[67]
    DIRECTION OUTPUT ;
    USE SIGNAL ;
    PORT
      LAYER M5 ;
        RECT  32.496 0 32.52 0.084 ;
    END
  END o[67]
  PIN o[68]
    DIRECTION OUTPUT ;
    USE SIGNAL ;
    PORT
      LAYER M5 ;
        RECT  32.592 0 32.616 0.084 ;
    END
  END o[68]
  PIN o[69]
    DIRECTION OUTPUT ;
    USE SIGNAL ;
    PORT
      LAYER M5 ;
        RECT  32.688 0 32.712 0.084 ;
    END
  END o[69]
  PIN o[6]
    DIRECTION OUTPUT ;
    USE SIGNAL ;
    PORT
      LAYER M5 ;
        RECT  35.856 0 35.88 0.084 ;
    END
  END o[6]
  PIN o[70]
    DIRECTION OUTPUT ;
    USE SIGNAL ;
    PORT
      LAYER M5 ;
        RECT  32.784 0 32.808 0.084 ;
    END
  END o[70]
  PIN o[71]
    DIRECTION OUTPUT ;
    USE SIGNAL ;
    PORT
      LAYER M5 ;
        RECT  32.88 0 32.904 0.084 ;
    END
  END o[71]
  PIN o[72]
    DIRECTION OUTPUT ;
    USE SIGNAL ;
    PORT
      LAYER M5 ;
        RECT  32.976 0 33 0.084 ;
    END
  END o[72]
  PIN o[73]
    DIRECTION OUTPUT ;
    USE SIGNAL ;
    PORT
      LAYER M5 ;
        RECT  33.072 0 33.096 0.084 ;
    END
  END o[73]
  PIN o[74]
    DIRECTION OUTPUT ;
    USE SIGNAL ;
    PORT
      LAYER M5 ;
        RECT  33.168 0 33.192 0.084 ;
    END
  END o[74]
  PIN o[75]
    DIRECTION OUTPUT ;
    USE SIGNAL ;
    PORT
      LAYER M5 ;
        RECT  33.264 0 33.288 0.084 ;
    END
  END o[75]
  PIN o[76]
    DIRECTION OUTPUT ;
    USE SIGNAL ;
    PORT
      LAYER M5 ;
        RECT  33.36 0 33.384 0.084 ;
    END
  END o[76]
  PIN o[77]
    DIRECTION OUTPUT ;
    USE SIGNAL ;
    PORT
      LAYER M5 ;
        RECT  33.456 0 33.48 0.084 ;
    END
  END o[77]
  PIN o[78]
    DIRECTION OUTPUT ;
    USE SIGNAL ;
    PORT
      LAYER M5 ;
        RECT  33.552 0 33.576 0.084 ;
    END
  END o[78]
  PIN o[79]
    DIRECTION OUTPUT ;
    USE SIGNAL ;
    PORT
      LAYER M5 ;
        RECT  33.648 0 33.672 0.084 ;
    END
  END o[79]
  PIN o[7]
    DIRECTION OUTPUT ;
    USE SIGNAL ;
    PORT
      LAYER M5 ;
        RECT  35.952 0 35.976 0.084 ;
    END
  END o[7]
  PIN o[80]
    DIRECTION OUTPUT ;
    USE SIGNAL ;
    PORT
      LAYER M5 ;
        RECT  33.744 0 33.768 0.084 ;
    END
  END o[80]
  PIN o[81]
    DIRECTION OUTPUT ;
    USE SIGNAL ;
    PORT
      LAYER M5 ;
        RECT  33.84 0 33.864 0.084 ;
    END
  END o[81]
  PIN o[82]
    DIRECTION OUTPUT ;
    USE SIGNAL ;
    PORT
      LAYER M5 ;
        RECT  33.936 0 33.96 0.084 ;
    END
  END o[82]
  PIN o[83]
    DIRECTION OUTPUT ;
    USE SIGNAL ;
    PORT
      LAYER M5 ;
        RECT  34.032 0 34.056 0.084 ;
    END
  END o[83]
  PIN o[84]
    DIRECTION OUTPUT ;
    USE SIGNAL ;
    PORT
      LAYER M5 ;
        RECT  34.128 0 34.152 0.084 ;
    END
  END o[84]
  PIN o[85]
    DIRECTION OUTPUT ;
    USE SIGNAL ;
    PORT
      LAYER M5 ;
        RECT  34.224 0 34.248 0.084 ;
    END
  END o[85]
  PIN o[86]
    DIRECTION OUTPUT ;
    USE SIGNAL ;
    PORT
      LAYER M5 ;
        RECT  34.32 0 34.344 0.084 ;
    END
  END o[86]
  PIN o[87]
    DIRECTION OUTPUT ;
    USE SIGNAL ;
    PORT
      LAYER M5 ;
        RECT  34.416 0 34.44 0.084 ;
    END
  END o[87]
  PIN o[88]
    DIRECTION OUTPUT ;
    USE SIGNAL ;
    PORT
      LAYER M5 ;
        RECT  34.512 0 34.536 0.084 ;
    END
  END o[88]
  PIN o[89]
    DIRECTION OUTPUT ;
    USE SIGNAL ;
    PORT
      LAYER M5 ;
        RECT  34.608 0 34.632 0.084 ;
    END
  END o[89]
  PIN o[8]
    DIRECTION OUTPUT ;
    USE SIGNAL ;
    PORT
      LAYER M5 ;
        RECT  36.048 0 36.072 0.084 ;
    END
  END o[8]
  PIN o[90]
    DIRECTION OUTPUT ;
    USE SIGNAL ;
    PORT
      LAYER M5 ;
        RECT  34.704 0 34.728 0.084 ;
    END
  END o[90]
  PIN o[91]
    DIRECTION OUTPUT ;
    USE SIGNAL ;
    PORT
      LAYER M5 ;
        RECT  34.8 0 34.824 0.084 ;
    END
  END o[91]
  PIN o[92]
    DIRECTION OUTPUT ;
    USE SIGNAL ;
    PORT
      LAYER M5 ;
        RECT  34.896 0 34.92 0.084 ;
    END
  END o[92]
  PIN o[93]
    DIRECTION OUTPUT ;
    USE SIGNAL ;
    PORT
      LAYER M5 ;
        RECT  34.992 0 35.016 0.084 ;
    END
  END o[93]
  PIN o[94]
    DIRECTION OUTPUT ;
    USE SIGNAL ;
    PORT
      LAYER M5 ;
        RECT  35.088 0 35.112 0.084 ;
    END
  END o[94]
  PIN o[95]
    DIRECTION OUTPUT ;
    USE SIGNAL ;
    PORT
      LAYER M5 ;
        RECT  35.184 0 35.208 0.084 ;
    END
  END o[95]
  PIN o[96]
    DIRECTION OUTPUT ;
    USE SIGNAL ;
    PORT
      LAYER M5 ;
        RECT  19.92 0 19.944 0.084 ;
    END
  END o[96]
  PIN o[97]
    DIRECTION OUTPUT ;
    USE SIGNAL ;
    PORT
      LAYER M5 ;
        RECT  20.016 0 20.04 0.084 ;
    END
  END o[97]
  PIN o[98]
    DIRECTION OUTPUT ;
    USE SIGNAL ;
    PORT
      LAYER M5 ;
        RECT  20.112 0 20.136 0.084 ;
    END
  END o[98]
  PIN o[99]
    DIRECTION OUTPUT ;
    USE SIGNAL ;
    PORT
      LAYER M5 ;
        RECT  20.208 0 20.232 0.084 ;
    END
  END o[99]
  PIN o[9]
    DIRECTION OUTPUT ;
    USE SIGNAL ;
    PORT
      LAYER M5 ;
        RECT  36.144 0 36.168 0.084 ;
    END
  END o[9]
  PIN rfi
    DIRECTION INPUT ;
    USE SIGNAL ;
    PORT
      LAYER M5 ;
        RECT  3.312 23.676 3.336 23.76 ;
    END
  END rfi
  PIN rfo
    DIRECTION OUTPUT ;
    USE SIGNAL ;
    PORT
      LAYER M5 ;
        RECT  62.928 0 62.952 0.084 ;
    END
  END rfo
  PIN rs
    DIRECTION INPUT ;
    USE SIGNAL ;
    PORT
      LAYER M4 ;
        RECT  0 11.856 0.084 11.88 ;
    END
  END rs
  PIN rso
    DIRECTION OUTPUT ;
    USE SIGNAL ;
    PORT
      LAYER M5 ;
        RECT  63.024 0 63.048 0.084 ;
    END
  END rso
  PIN VDD
    DIRECTION INOUT ;
    USE POWER ;
    PORT
      LAYER M5 ;
        RECT  61.992 2.151 62.112 21.609 ;
        RECT  59.292 2.151 59.412 21.609 ;
        RECT  56.592 2.151 56.712 21.609 ;
        RECT  53.892 2.151 54.012 21.609 ;
        RECT  51.192 2.151 51.312 21.609 ;
        RECT  48.492 2.151 48.612 21.609 ;
        RECT  45.792 2.151 45.912 21.609 ;
        RECT  43.092 2.151 43.212 21.609 ;
        RECT  40.392 2.151 40.512 21.609 ;
        RECT  37.692 2.151 37.812 21.609 ;
        RECT  34.992 2.151 35.112 21.609 ;
        RECT  32.292 2.151 32.412 21.609 ;
        RECT  29.592 2.151 29.712 21.609 ;
        RECT  26.892 2.151 27.012 21.609 ;
        RECT  24.192 2.151 24.312 21.609 ;
        RECT  21.492 2.151 21.612 21.609 ;
        RECT  18.792 2.151 18.912 21.609 ;
        RECT  16.092 2.151 16.212 21.609 ;
        RECT  13.392 2.151 13.512 21.609 ;
        RECT  10.692 2.151 10.812 21.609 ;
        RECT  7.992 2.151 8.112 21.609 ;
        RECT  5.292 2.151 5.412 21.609 ;
        RECT  2.592 2.151 2.712 21.609 ;
    END
  END VDD
  PIN VSS
    DIRECTION INOUT ;
    USE GROUND ;
    PORT
      LAYER M5 ;
        RECT  61.8 2.137 61.92 21.623 ;
        RECT  59.1 2.137 59.22 21.623 ;
        RECT  56.4 2.137 56.52 21.623 ;
        RECT  53.7 2.137 53.82 21.623 ;
        RECT  51 2.137 51.12 21.623 ;
        RECT  48.3 2.137 48.42 21.623 ;
        RECT  45.6 2.137 45.72 21.623 ;
        RECT  42.9 2.137 43.02 21.623 ;
        RECT  40.2 2.137 40.32 21.623 ;
        RECT  37.5 2.137 37.62 21.623 ;
        RECT  34.8 2.137 34.92 21.623 ;
        RECT  32.1 2.137 32.22 21.623 ;
        RECT  29.4 2.137 29.52 21.623 ;
        RECT  26.7 2.137 26.82 21.623 ;
        RECT  24 2.137 24.12 21.623 ;
        RECT  21.3 2.137 21.42 21.623 ;
        RECT  18.6 2.137 18.72 21.623 ;
        RECT  15.9 2.137 16.02 21.623 ;
        RECT  13.2 2.137 13.32 21.623 ;
        RECT  10.5 2.137 10.62 21.623 ;
        RECT  7.8 2.137 7.92 21.623 ;
        RECT  5.1 2.137 5.22 21.623 ;
        RECT  2.4 2.137 2.52 21.623 ;
    END
  END VSS
  OBS
    LAYER RVTN ;
     RECT  2.16 2.16 62.64 2.295 ;
     RECT  2.16 2.565 62.64 2.835 ;
     RECT  2.16 3.105 62.64 3.375 ;
     RECT  2.16 3.645 62.64 3.915 ;
     RECT  2.16 4.185 62.64 4.455 ;
     RECT  2.16 4.725 62.64 4.995 ;
     RECT  2.16 5.265 62.64 5.535 ;
     RECT  2.16 5.805 62.64 6.075 ;
     RECT  2.16 6.345 62.64 6.615 ;
     RECT  2.16 6.885 62.64 7.155 ;
     RECT  2.16 7.425 62.64 7.695 ;
     RECT  2.16 7.965 62.64 8.235 ;
     RECT  2.16 8.505 62.64 8.775 ;
     RECT  2.16 9.045 62.64 9.315 ;
     RECT  2.16 9.585 62.64 9.855 ;
     RECT  2.16 10.125 62.64 10.395 ;
     RECT  2.16 10.665 62.64 10.935 ;
     RECT  2.16 11.205 62.64 11.475 ;
     RECT  2.16 11.745 62.64 12.015 ;
     RECT  2.16 12.285 62.64 12.555 ;
     RECT  2.16 12.825 62.64 13.095 ;
     RECT  2.16 13.365 62.64 13.635 ;
     RECT  2.16 13.905 62.64 14.175 ;
     RECT  2.16 14.445 62.64 14.715 ;
     RECT  2.16 14.985 62.64 15.255 ;
     RECT  2.16 15.525 62.64 15.795 ;
     RECT  2.16 16.065 62.64 16.335 ;
     RECT  2.16 16.605 62.64 16.875 ;
     RECT  2.16 17.145 62.64 17.415 ;
     RECT  2.16 17.685 62.64 17.955 ;
     RECT  2.16 18.225 62.64 18.495 ;
     RECT  2.16 18.765 62.64 19.035 ;
     RECT  2.16 19.305 62.64 19.575 ;
     RECT  2.16 19.845 62.64 20.115 ;
     RECT  2.16 20.385 62.64 20.655 ;
     RECT  2.16 20.925 62.64 21.195 ;
     RECT  2.16 21.465 62.64 21.6 ;
    LAYER RVTP ;
     RECT  2.16 2.295 62.64 2.565 ;
     RECT  2.16 2.835 62.64 3.105 ;
     RECT  2.16 3.375 62.64 3.645 ;
     RECT  2.16 3.915 62.64 4.185 ;
     RECT  2.16 4.455 62.64 4.725 ;
     RECT  2.16 4.995 62.64 5.265 ;
     RECT  2.16 5.535 62.64 5.805 ;
     RECT  2.16 6.075 62.64 6.345 ;
     RECT  2.16 6.615 62.64 6.885 ;
     RECT  2.16 7.155 62.64 7.425 ;
     RECT  2.16 7.695 62.64 7.965 ;
     RECT  2.16 8.235 62.64 8.505 ;
     RECT  2.16 8.775 62.64 9.045 ;
     RECT  2.16 9.315 62.64 9.585 ;
     RECT  2.16 9.855 62.64 10.125 ;
     RECT  2.16 10.395 62.64 10.665 ;
     RECT  2.16 10.935 62.64 11.205 ;
     RECT  2.16 11.475 62.64 11.745 ;
     RECT  2.16 12.015 62.64 12.285 ;
     RECT  2.16 12.555 62.64 12.825 ;
     RECT  2.16 13.095 62.64 13.365 ;
     RECT  2.16 13.635 62.64 13.905 ;
     RECT  2.16 14.175 62.64 14.445 ;
     RECT  2.16 14.715 62.64 14.985 ;
     RECT  2.16 15.255 62.64 15.525 ;
     RECT  2.16 15.795 62.64 16.065 ;
     RECT  2.16 16.335 62.64 16.605 ;
     RECT  2.16 16.875 62.64 17.145 ;
     RECT  2.16 17.415 62.64 17.685 ;
     RECT  2.16 17.955 62.64 18.225 ;
     RECT  2.16 18.495 62.64 18.765 ;
     RECT  2.16 19.035 62.64 19.305 ;
     RECT  2.16 19.575 62.64 19.845 ;
     RECT  2.16 20.115 62.64 20.385 ;
     RECT  2.16 20.655 62.64 20.925 ;
     RECT  2.16 21.195 62.64 21.465 ;
    LAYER M1 ;
     RECT  2.16 2.151 62.64 21.609 ;
    LAYER M2 ;
     RECT  1.831 2.736 1.867 2.754 ;
     RECT  0.931 3.546 1.867 3.564 ;
     RECT  1.867 2.736 1.903 3.564 ;
     RECT  1.219 7.938 1.903 7.956 ;
     RECT  1.939 13.14 2.011 13.158 ;
     RECT  1.903 2.574 2.047 3.564 ;
     RECT  2.011 13.14 2.047 13.194 ;
     RECT  1.831 10.746 2.083 10.764 ;
     RECT  1.615 6.156 2.155 6.174 ;
     RECT  2.047 2.106 2.16 3.564 ;
     RECT  2.155 5.166 2.16 5.184 ;
     RECT  2.155 6.156 2.16 6.912 ;
     RECT  1.903 7.938 2.16 8.028 ;
     RECT  1.867 9.126 2.16 9.144 ;
     RECT  2.083 10.746 2.16 11.304 ;
     RECT  2.047 13.104 2.16 13.194 ;
     RECT  2.16 2.106 2.299 21.609 ;
     RECT  2.299 2.034 2.659 21.609 ;
     RECT  2.659 1.962 3.479 21.609 ;
     RECT  3.479 2.07 4.495 21.609 ;
     RECT  4.495 2.034 5.431 21.609 ;
     RECT  5.431 1.152 5.531 1.17 ;
     RECT  5.431 2.034 5.783 21.654 ;
     RECT  5.783 2.106 9.067 21.654 ;
     RECT  9.067 2.034 9.599 21.654 ;
     RECT  9.599 2.106 10.903 21.654 ;
     RECT  10.903 2.106 11.723 21.834 ;
     RECT  12.271 1.152 12.371 1.17 ;
     RECT  11.723 2.151 13.351 21.834 ;
     RECT  9.967 22.86 13.603 22.878 ;
     RECT  13.351 2.106 14.107 21.834 ;
     RECT  13.603 22.824 14.107 22.878 ;
     RECT  14.107 2.106 14.611 22.878 ;
     RECT  14.611 2.034 15.619 22.878 ;
     RECT  15.475 1.152 15.647 1.17 ;
     RECT  15.619 2.034 15.683 23.04 ;
     RECT  15.683 2.106 17.995 23.04 ;
     RECT  17.995 2.106 18.175 23.076 ;
     RECT  18.175 2.07 18.599 23.076 ;
     RECT  18.599 2.106 19.507 23.076 ;
     RECT  19.507 2.106 20.011 23.112 ;
     RECT  20.011 2.07 20.587 23.112 ;
     RECT  20.587 1.962 22.667 23.112 ;
     RECT  22.667 2.106 23.495 23.112 ;
     RECT  23.495 2.151 24.511 23.112 ;
     RECT  24.511 2.106 24.755 23.112 ;
     RECT  24.755 2.151 26.887 23.112 ;
     RECT  25.699 1.152 27.275 1.17 ;
     RECT  26.887 2.106 28.931 23.112 ;
     RECT  28.931 2.151 30.055 23.112 ;
     RECT  30.055 2.106 31.531 23.112 ;
     RECT  31.495 1.152 31.631 1.17 ;
     RECT  31.531 2.034 32.747 23.112 ;
     RECT  32.647 1.224 32.755 1.242 ;
     RECT  32.755 1.152 32.783 1.242 ;
     RECT  32.783 1.152 33.035 1.17 ;
     RECT  32.747 2.106 33.071 23.112 ;
     RECT  33.071 2.151 33.907 23.112 ;
     RECT  33.907 2.106 36.275 23.112 ;
     RECT  37.219 1.152 37.319 1.17 ;
     RECT  36.275 2.151 37.651 23.112 ;
     RECT  37.651 2.106 38.039 23.112 ;
     RECT  38.039 2.151 40.675 23.112 ;
     RECT  40.675 2.106 40.999 23.112 ;
     RECT  40.999 2.034 42.107 23.112 ;
     RECT  43.411 1.152 43.511 1.17 ;
     RECT  44.599 1.152 44.699 1.17 ;
     RECT  42.107 2.151 45.427 23.112 ;
     RECT  45.427 2.106 45.463 23.112 ;
     RECT  45.463 2.034 46.355 23.112 ;
     RECT  46.355 2.034 46.715 23.004 ;
     RECT  46.715 2.151 47.551 22.914 ;
     RECT  49.675 1.152 49.775 1.17 ;
     RECT  47.551 2.106 50.107 22.914 ;
     RECT  50.107 2.034 52.187 22.914 ;
     RECT  52.187 2.151 52.403 22.914 ;
     RECT  52.519 1.152 52.619 1.17 ;
     RECT  52.403 2.151 53.527 21.834 ;
     RECT  53.527 2.106 53.627 21.834 ;
     RECT  53.627 2.106 54.059 21.798 ;
     RECT  54.059 2.151 54.779 21.798 ;
     RECT  52.403 22.896 55.031 22.914 ;
     RECT  54.779 2.151 55.535 21.726 ;
     RECT  55.291 1.152 55.643 1.17 ;
     RECT  55.535 2.151 55.867 21.69 ;
     RECT  55.867 2.106 56.083 21.69 ;
     RECT  56.083 2.07 56.399 21.69 ;
     RECT  56.399 2.106 56.579 21.69 ;
     RECT  56.579 2.106 57.047 21.654 ;
     RECT  57.047 2.151 57.659 21.654 ;
     RECT  57.659 2.151 58.747 21.609 ;
     RECT  58.747 1.152 58.919 1.17 ;
     RECT  58.747 2.151 59.315 21.654 ;
     RECT  59.315 2.151 59.935 21.609 ;
     RECT  59.935 2.106 60.835 21.609 ;
     RECT  60.835 1.881 62.447 21.609 ;
     RECT  62.447 1.962 62.64 21.609 ;
     RECT  62.64 5.202 62.663 7.686 ;
     RECT  62.663 5.202 62.699 5.724 ;
     RECT  62.699 5.202 62.735 5.562 ;
     RECT  62.64 16.884 62.771 19.368 ;
     RECT  62.64 1.962 62.807 4.284 ;
     RECT  62.64 11.106 62.807 13.554 ;
     RECT  62.771 16.884 62.807 17.946 ;
     RECT  62.64 20.628 62.807 20.646 ;
     RECT  62.807 3.348 62.843 4.284 ;
     RECT  62.807 12.996 62.843 13.554 ;
     RECT  62.771 18.738 62.843 19.368 ;
     RECT  62.843 4.266 62.879 4.284 ;
     RECT  62.843 12.996 62.879 13.284 ;
     RECT  62.807 16.884 62.879 17.784 ;
     RECT  62.807 1.962 62.915 2.286 ;
     RECT  62.807 11.106 62.915 11.934 ;
     RECT  62.843 3.348 62.951 3.402 ;
     RECT  62.64 10.098 62.951 10.116 ;
     RECT  62.663 6.516 63.023 7.686 ;
     RECT  63.023 7.668 63.059 7.686 ;
     RECT  63.023 6.516 63.095 6.534 ;
     RECT  62.735 5.202 63.131 5.22 ;
     RECT  62.915 2.034 63.167 2.286 ;
     RECT  62.915 11.646 63.167 11.934 ;
     RECT  62.843 18.774 63.275 19.368 ;
     RECT  62.951 3.384 63.311 3.402 ;
     RECT  62.879 13.266 63.311 13.284 ;
     RECT  62.879 16.884 63.311 17.748 ;
     RECT  63.167 2.034 63.347 2.052 ;
     RECT  63.167 11.646 63.347 11.664 ;
     RECT  63.311 16.884 63.347 16.902 ;
     RECT  63.275 19.35 63.887 19.368 ;
     RECT  63.311 17.658 63.923 17.676 ;
    LAYER M3 ;
     RECT  13.86 0.091 14.166 0.139 ;
     RECT  30.924 0.091 30.942 0.139 ;
     RECT  40.716 0.091 40.734 0.139 ;
     RECT  42.048 0.091 42.066 0.139 ;
     RECT  49.284 0.091 49.302 0.139 ;
     RECT  63 0.091 63.018 0.139 ;
     RECT  1.044 0.043 1.062 0.173 ;
     RECT  8.748 0.091 8.766 0.187 ;
     RECT  29.916 0.091 29.934 0.187 ;
     RECT  40.716 0.139 40.878 0.187 ;
     RECT  49.212 0.139 49.302 0.187 ;
     RECT  35.568 0.091 35.982 0.221 ;
     RECT  37.44 0.091 38.07 0.221 ;
     RECT  46.152 0.091 46.17 0.221 ;
     RECT  53.244 0.091 53.802 0.221 ;
     RECT  8.244 0.187 8.766 0.269 ;
     RECT  30.924 0.139 31.086 0.269 ;
     RECT  40.716 0.187 40.95 0.269 ;
     RECT  42.048 0.139 42.138 0.269 ;
     RECT  50.22 0.091 51.426 0.269 ;
     RECT  2.736 0.187 2.754 0.317 ;
     RECT  5.436 0.091 5.634 0.317 ;
     RECT  29.916 0.187 30.114 0.317 ;
     RECT  31.068 0.269 31.086 0.317 ;
     RECT  40.86 0.269 40.95 0.317 ;
     RECT  13.788 0.139 14.166 0.365 ;
     RECT  40.932 0.317 40.95 0.365 ;
     RECT  49.104 0.187 49.302 0.413 ;
     RECT  50.22 0.269 50.382 0.413 ;
     RECT  8.244 0.269 8.514 0.461 ;
     RECT  14.004 0.365 14.022 0.461 ;
     RECT  4.176 0.043 4.194 0.523 ;
     RECT  42.048 0.269 42.066 0.523 ;
     RECT  50.22 0.413 50.274 0.523 ;
     RECT  52.272 0.091 52.29 0.523 ;
     RECT  53.244 0.221 53.262 0.523 ;
     RECT  8.244 0.461 8.442 0.557 ;
     RECT  3.708 0.523 4.194 0.571 ;
     RECT  16.308 0.091 16.326 0.571 ;
     RECT  27.108 0.187 27.126 0.571 ;
     RECT  37.44 0.221 37.458 0.571 ;
     RECT  41.688 0.523 42.066 0.571 ;
     RECT  61.632 0.523 61.65 0.619 ;
     RECT  63 0.139 63.126 0.619 ;
     RECT  8.424 0.557 8.442 0.653 ;
     RECT  32.652 0.523 32.67 1.099 ;
     RECT  44.676 0.571 44.694 1.099 ;
     RECT  3.456 0.571 4.194 1.147 ;
     RECT  5.436 0.317 5.454 1.147 ;
     RECT  12.348 0.571 12.366 1.147 ;
     RECT  15.624 0.571 16.326 1.147 ;
     RECT  24.408 0.427 24.426 1.147 ;
     RECT  25.704 0.091 25.722 1.147 ;
     RECT  26.46 0.571 27.126 1.147 ;
     RECT  31.5 1.099 31.518 1.147 ;
     RECT  32.652 1.099 32.778 1.147 ;
     RECT  43.488 0.523 43.506 1.147 ;
     RECT  44.676 1.099 44.73 1.147 ;
     RECT  52.272 0.523 53.262 1.147 ;
     RECT  55.296 0.523 55.314 1.147 ;
     RECT  56.16 0.571 56.178 1.147 ;
     RECT  58.896 1.099 58.914 1.147 ;
     RECT  24.408 1.147 27.27 1.175 ;
     RECT  46.404 0.379 46.422 1.243 ;
     RECT  15.48 1.147 16.362 1.675 ;
     RECT  24.408 1.175 25.146 1.675 ;
     RECT  32.436 1.147 33.03 1.675 ;
     RECT  43.416 1.147 43.506 1.675 ;
     RECT  5.436 1.147 5.526 1.723 ;
     RECT  12.276 1.147 12.366 1.723 ;
     RECT  13.608 1.147 13.626 1.723 ;
     RECT  15.48 1.675 16.938 1.723 ;
     RECT  18.54 0.523 18.558 1.723 ;
     RECT  20.124 0.571 20.142 1.723 ;
     RECT  21.06 0.571 21.078 1.723 ;
     RECT  21.996 1.147 22.014 1.723 ;
     RECT  28.8 0.091 28.818 1.723 ;
     RECT  30.096 0.317 30.114 1.723 ;
     RECT  31.284 1.147 31.626 1.723 ;
     RECT  32.436 1.675 33.102 1.723 ;
     RECT  33.948 1.243 34.146 1.723 ;
     RECT  35.568 0.221 35.586 1.723 ;
     RECT  37.224 0.571 37.458 1.723 ;
     RECT  39.42 0.091 39.438 1.723 ;
     RECT  41.112 0.571 42.066 1.723 ;
     RECT  43.056 1.675 43.506 1.723 ;
     RECT  44.604 1.147 44.73 1.723 ;
     RECT  46.404 1.243 46.674 1.723 ;
     RECT  47.7 1.147 47.718 1.723 ;
     RECT  49.68 0.523 50.274 1.723 ;
     RECT  51.408 0.269 51.426 1.723 ;
     RECT  55.296 1.147 56.178 1.723 ;
     RECT  56.952 0.235 56.97 1.723 ;
     RECT  58.752 1.147 58.914 1.723 ;
     RECT  5.436 1.723 5.85 1.771 ;
     RECT  6.66 1.723 6.678 1.771 ;
     RECT  8.604 1.723 8.622 1.771 ;
     RECT  10.908 1.723 10.926 1.771 ;
     RECT  12.276 1.723 13.626 1.771 ;
     RECT  15.48 1.723 18.558 1.771 ;
     RECT  23.04 1.723 23.058 1.771 ;
     RECT  27.252 1.175 27.27 1.771 ;
     RECT  28.692 1.723 28.818 1.771 ;
     RECT  30.096 1.723 30.438 1.771 ;
     RECT  59.832 1.723 59.85 1.771 ;
     RECT  60.768 0.571 60.786 1.771 ;
     RECT  61.524 0.619 63.126 1.771 ;
     RECT  3.456 1.147 4.302 1.819 ;
     RECT  5.436 1.771 6.678 1.819 ;
     RECT  10.116 1.771 13.626 1.819 ;
     RECT  15.084 1.771 19.242 1.819 ;
     RECT  22.968 1.771 23.058 1.819 ;
     RECT  30.024 1.771 30.438 1.819 ;
     RECT  31.284 1.723 34.146 1.819 ;
     RECT  41.112 1.723 44.73 1.819 ;
     RECT  45.864 1.723 51.426 1.819 ;
     RECT  52.272 1.147 53.37 1.819 ;
     RECT  54.468 1.723 56.178 1.819 ;
     RECT  56.952 1.723 57.33 1.819 ;
     RECT  58.608 1.723 59.022 1.819 ;
     RECT  3.456 1.819 6.678 1.867 ;
     RECT  23.976 1.675 25.146 1.867 ;
     RECT  35.172 1.723 38.178 1.867 ;
     RECT  39.132 1.723 39.69 1.867 ;
     RECT  10.044 1.819 13.626 1.915 ;
     RECT  30.024 1.819 34.146 1.915 ;
     RECT  20.052 1.723 20.214 1.957 ;
     RECT  21.06 1.723 22.014 1.957 ;
     RECT  22.968 1.819 23.094 1.957 ;
     RECT  23.94 1.867 25.146 1.963 ;
     RECT  26.064 1.175 26.478 1.963 ;
     RECT  52.272 1.819 53.658 1.963 ;
     RECT  54.468 1.819 59.022 1.963 ;
     RECT  3.456 1.867 7.002 2.011 ;
     RECT  27.252 1.771 28.818 2.011 ;
     RECT  30.024 1.915 34.182 2.011 ;
     RECT  35.172 1.867 39.69 2.011 ;
     RECT  2.664 1.957 2.682 2.029 ;
     RECT  3.456 2.011 7.65 2.029 ;
     RECT  8.388 1.771 9.162 2.029 ;
     RECT  10.008 1.915 13.626 2.029 ;
     RECT  14.688 1.819 19.242 2.029 ;
     RECT  41.112 1.819 51.426 2.029 ;
     RECT  52.272 1.963 59.022 2.029 ;
     RECT  59.832 1.771 63.126 2.029 ;
     RECT  41.004 2.029 51.426 2.059 ;
     RECT  52.164 2.029 59.022 2.059 ;
     RECT  20.052 1.957 23.094 2.065 ;
     RECT  2.304 2.029 7.65 2.101 ;
     RECT  8.388 2.029 13.626 2.101 ;
     RECT  14.616 2.029 19.242 2.101 ;
     RECT  20.016 2.065 23.094 2.101 ;
     RECT  23.94 1.963 26.478 2.101 ;
     RECT  27.252 2.011 34.182 2.101 ;
     RECT  35.172 2.011 40.014 2.101 ;
     RECT  40.824 2.059 59.022 2.101 ;
     RECT  2.052 2.101 59.022 2.143 ;
     RECT  59.832 2.029 63.342 2.143 ;
     RECT  2.052 2.143 63.342 2.569 ;
     RECT  1.908 2.569 63.342 2.731 ;
     RECT  0.936 2.923 0.954 3.569 ;
     RECT  1.836 2.731 63.342 5.131 ;
     RECT  1.224 5.131 63.342 7.961 ;
     RECT  1.836 7.961 63.342 10.769 ;
     RECT  1.944 10.769 63.342 11.669 ;
     RECT  0.108 11.851 0.126 11.981 ;
     RECT  1.152 11.659 1.17 11.981 ;
     RECT  1.944 11.669 63.306 12.479 ;
     RECT  1.944 12.479 62.097 13.127 ;
     RECT  1.944 13.127 10.797 13.163 ;
     RECT  2.016 13.163 10.797 13.199 ;
     RECT  62.82 12.479 63.306 13.289 ;
     RECT  2.415 13.199 10.797 13.469 ;
     RECT  62.82 13.289 62.838 13.559 ;
     RECT  11.7 13.127 62.097 14.107 ;
     RECT  3.42 13.469 10.797 14.203 ;
     RECT  11.628 14.107 62.097 14.203 ;
     RECT  2.415 13.469 2.697 14.485 ;
     RECT  3.42 14.203 62.097 14.485 ;
     RECT  2.415 14.485 62.097 15.791 ;
     RECT  61.524 15.791 62.097 16.951 ;
     RECT  63.324 16.879 63.342 16.951 ;
     RECT  61.524 16.951 62.154 17.077 ;
     RECT  61.524 17.077 62.442 17.113 ;
     RECT  63.288 16.951 63.342 17.113 ;
     RECT  61.524 17.113 63.342 17.581 ;
     RECT  2.415 15.791 60.75 17.617 ;
     RECT  61.488 17.581 63.342 17.617 ;
     RECT  2.415 17.617 63.342 17.653 ;
     RECT  2.415 17.653 63.918 19.471 ;
     RECT  2.34 19.471 63.918 19.615 ;
     RECT  2.304 19.615 63.918 19.741 ;
     RECT  2.268 19.741 63.918 20.579 ;
     RECT  2.34 20.579 63.918 20.849 ;
     RECT  2.376 20.849 63.918 21.119 ;
     RECT  2.415 21.119 63.918 21.149 ;
     RECT  2.415 21.149 62.766 21.197 ;
     RECT  2.415 21.197 62.73 21.389 ;
     RECT  28.62 21.389 57.654 21.437 ;
     RECT  31.032 21.437 57.654 21.461 ;
     RECT  58.5 21.389 62.73 21.461 ;
     RECT  9.936 21.389 11.178 21.533 ;
     RECT  11.952 21.389 22.23 21.533 ;
     RECT  31.032 21.461 38.322 21.533 ;
     RECT  12.384 21.533 22.23 21.569 ;
     RECT  31.104 21.533 38.322 21.569 ;
     RECT  58.716 21.461 62.73 21.569 ;
     RECT  2.415 21.389 9.162 21.581 ;
     RECT  2.415 21.581 6.678 21.617 ;
     RECT  2.736 21.617 6.678 21.629 ;
     RECT  39.276 21.461 57.654 21.629 ;
     RECT  9.972 21.533 11.178 21.659 ;
     RECT  39.348 21.629 57.654 21.659 ;
     RECT  58.752 21.569 59.454 21.659 ;
     RECT  2.736 21.629 6.246 21.677 ;
     RECT  7.704 21.581 9.126 21.677 ;
     RECT  12.384 21.569 22.05 21.677 ;
     RECT  31.104 21.569 38.286 21.677 ;
     RECT  39.348 21.659 57.582 21.677 ;
     RECT  58.788 21.659 59.454 21.677 ;
     RECT  56.34 21.677 57.582 21.695 ;
     RECT  7.704 21.677 8.154 21.725 ;
     RECT  39.348 21.677 41.13 21.725 ;
     RECT  59.436 21.677 59.454 21.725 ;
     RECT  60.408 21.569 62.73 21.725 ;
     RECT  53.604 21.677 55.53 21.731 ;
     RECT  5.256 21.677 6.174 21.773 ;
     RECT  7.704 21.725 7.974 21.773 ;
     RECT  9.972 21.659 11.106 21.773 ;
     RECT  15.192 21.677 19.53 21.773 ;
     RECT  31.104 21.677 38.034 21.773 ;
     RECT  39.348 21.725 40.194 21.773 ;
     RECT  48.276 21.677 49.698 21.773 ;
     RECT  51.156 21.677 52.614 21.773 ;
     RECT  56.34 21.695 56.358 21.773 ;
     RECT  61.956 21.725 62.73 21.773 ;
     RECT  7.704 21.773 7.722 21.821 ;
     RECT  16.524 21.773 19.53 21.821 ;
     RECT  22.968 21.389 27.702 21.821 ;
     RECT  41.112 21.725 41.13 21.821 ;
     RECT  12.384 21.677 14.346 21.839 ;
     RECT  35.28 21.773 38.034 21.839 ;
     RECT  53.604 21.731 55.458 21.839 ;
     RECT  9.972 21.773 10.998 21.869 ;
     RECT  12.384 21.839 14.238 21.869 ;
     RECT  19.368 21.821 19.53 21.869 ;
     RECT  28.62 21.437 30.114 21.869 ;
     RECT  31.104 21.773 34.218 21.869 ;
     RECT  36.396 21.839 38.034 21.869 ;
     RECT  42.012 21.677 43.974 21.869 ;
     RECT  31.104 21.869 33.822 21.884 ;
     RECT  35.28 21.839 35.442 21.884 ;
     RECT  36.54 21.869 38.034 21.884 ;
     RECT  20.34 21.677 22.05 21.929 ;
     RECT  22.968 21.821 26.586 21.965 ;
     RECT  31.32 21.884 33.822 21.965 ;
     RECT  36.756 21.884 38.034 21.965 ;
     RECT  22.968 21.965 25.146 22.013 ;
     RECT  32.724 21.965 33.822 22.013 ;
     RECT  22.968 22.013 25.074 22.037 ;
     RECT  36.828 21.965 37.746 22.037 ;
     RECT  51.444 21.773 52.614 22.061 ;
     RECT  9.036 21.677 9.054 22.109 ;
     RECT  20.34 21.929 21.654 22.154 ;
     RECT  36.828 22.037 37.134 22.154 ;
     RECT  12.384 21.869 12.402 22.157 ;
     RECT  31.32 21.965 31.95 22.157 ;
     RECT  31.392 22.157 31.95 22.199 ;
     RECT  32.724 22.013 33.21 22.205 ;
     RECT  54.18 21.839 55.458 22.205 ;
     RECT  26.208 21.965 26.586 22.253 ;
     RECT  28.62 21.869 30.006 22.253 ;
     RECT  60.408 21.725 61.074 22.253 ;
     RECT  27.684 21.821 27.702 22.271 ;
     RECT  31.68 22.199 31.95 22.271 ;
     RECT  2.736 21.677 3.582 22.301 ;
     RECT  62.46 21.773 62.73 22.301 ;
     RECT  32.724 22.205 32.742 22.307 ;
     RECT  23.724 22.037 25.074 22.343 ;
     RECT  51.444 22.061 52.398 22.343 ;
     RECT  20.808 22.154 21.654 22.349 ;
     RECT  51.444 22.343 52.002 22.349 ;
     RECT  57.24 21.695 57.582 22.349 ;
     RECT  15.192 21.773 15.642 22.379 ;
     RECT  42.012 21.869 43.362 22.397 ;
     RECT  42.012 22.397 42.426 22.424 ;
     RECT  15.516 22.379 15.642 22.469 ;
     RECT  37.044 22.154 37.134 22.469 ;
     RECT  42.156 22.424 42.426 22.469 ;
     RECT  16.524 21.821 18.558 22.493 ;
     RECT  17.676 22.493 18.558 22.541 ;
     RECT  22.968 22.037 22.986 22.541 ;
     RECT  39.348 21.773 39.798 22.541 ;
     RECT  26.568 22.253 26.586 22.577 ;
     RECT  39.348 22.541 39.366 22.577 ;
     RECT  21.096 22.349 21.654 22.589 ;
     RECT  37.116 22.469 37.134 22.613 ;
     RECT  28.62 22.253 29.934 22.637 ;
     RECT  31.68 22.271 31.878 22.637 ;
     RECT  13.608 21.869 14.238 22.649 ;
     RECT  42.156 22.469 42.174 22.649 ;
     RECT  2.736 22.301 3.294 22.733 ;
     RECT  57.24 22.349 57.258 22.747 ;
     RECT  2.736 22.733 3.078 22.781 ;
     RECT  19.476 21.869 19.53 22.781 ;
     RECT  21.636 22.589 21.654 22.781 ;
     RECT  24.48 22.343 25.074 22.781 ;
     RECT  35.28 21.884 35.406 22.781 ;
     RECT  4.428 21.677 4.446 22.829 ;
     RECT  16.524 22.493 16.83 22.829 ;
     RECT  29.304 22.637 29.934 22.829 ;
     RECT  51.444 22.349 51.966 22.829 ;
     RECT  54.18 22.205 55.026 22.829 ;
     RECT  60.408 22.253 60.426 22.829 ;
     RECT  13.608 22.649 13.986 22.847 ;
     RECT  48.996 21.773 49.698 22.847 ;
     RECT  16.524 22.829 16.722 22.877 ;
     RECT  9.972 21.869 9.99 22.883 ;
     RECT  44.856 21.677 46.71 22.883 ;
     RECT  23.724 22.343 23.742 22.919 ;
     RECT  54.432 22.829 55.026 22.919 ;
     RECT  25.092 22.795 25.11 22.925 ;
     RECT  29.916 22.829 29.934 22.925 ;
     RECT  16.704 22.877 16.722 22.964 ;
     RECT  44.856 22.883 45.198 22.964 ;
     RECT  18 22.541 18.558 23.009 ;
     RECT  46.332 22.883 46.71 23.009 ;
     RECT  15.624 22.469 15.642 23.045 ;
     RECT  43.344 22.397 43.362 23.045 ;
     RECT  18 23.009 18.018 23.081 ;
     RECT  45.18 22.964 45.198 23.081 ;
     RECT  19.512 22.781 19.53 23.117 ;
     RECT  46.332 23.009 46.35 23.117 ;
     RECT  8.208 23.275 8.226 23.323 ;
     RECT  56.916 22.747 57.258 23.371 ;
     RECT  48.996 22.847 49.014 23.419 ;
     RECT  59.724 23.323 60.354 23.453 ;
     RECT  5.904 21.773 6.174 23.501 ;
     RECT  10.98 21.869 10.998 23.501 ;
     RECT  34.236 23.419 34.254 23.515 ;
     RECT  35.388 22.781 35.406 23.515 ;
     RECT  48.816 23.419 49.014 23.515 ;
     RECT  8.208 23.323 8.442 23.549 ;
     RECT  33.876 23.515 34.254 23.549 ;
     RECT  50.076 23.371 50.094 23.549 ;
     RECT  8.28 23.549 8.442 23.597 ;
     RECT  31.68 22.637 31.842 23.597 ;
     RECT  35.388 23.515 35.91 23.597 ;
     RECT  59.796 23.453 60.354 23.597 ;
     RECT  62.46 22.301 62.55 23.597 ;
     RECT  3.06 22.781 3.078 23.645 ;
     RECT  6.156 23.501 6.174 23.645 ;
     RECT  8.28 23.597 8.298 23.645 ;
     RECT  13.968 22.847 13.986 23.645 ;
     RECT  20.304 23.419 20.322 23.645 ;
     RECT  21.852 23.515 21.87 23.645 ;
     RECT  28.476 23.515 28.494 23.645 ;
     RECT  31.824 23.597 31.842 23.645 ;
     RECT  32.58 23.419 32.598 23.645 ;
     RECT  33.876 23.549 33.894 23.645 ;
     RECT  35.46 23.597 35.91 23.645 ;
     RECT  40.968 23.515 41.166 23.645 ;
     RECT  48.168 23.515 49.014 23.645 ;
     RECT  51.444 22.829 51.462 23.645 ;
     RECT  54.432 22.919 54.45 23.645 ;
     RECT  56.808 23.371 57.258 23.645 ;
     RECT  58.716 23.515 58.734 23.645 ;
     RECT  59.796 23.597 59.814 23.645 ;
     RECT  61.452 23.515 61.47 23.645 ;
     RECT  62.532 23.597 62.55 23.645 ;
     RECT  63.9 21.149 63.918 23.645 ;
    LAYER M4 ;
     RECT  0.06 11.76 0.097 11.88 ;
     RECT  0.709 2.88 0.805 2.904 ;
     RECT  0.805 2.832 0.881 2.904 ;
     RECT  0.989 0.144 1.033 0.168 ;
     RECT  1.033 0.048 1.073 0.168 ;
     RECT  0.097 11.76 1.141 11.976 ;
     RECT  1.093 4.56 1.169 4.584 ;
     RECT  1.141 11.664 1.181 11.976 ;
     RECT  1.169 4.56 1.285 5.16 ;
     RECT  0.881 2.832 1.381 2.952 ;
     RECT  1.381 2.832 1.861 3.144 ;
     RECT  1.285 4.128 1.861 5.16 ;
     RECT  1.765 20.16 1.861 20.184 ;
     RECT  1.861 20.16 1.957 20.472 ;
     RECT  1.957 20.064 2.053 20.472 ;
     RECT  1.765 6.384 2.149 6.408 ;
     RECT  1.861 2.832 2.197 5.16 ;
     RECT  2.197 2.016 2.245 5.16 ;
     RECT  2.149 6.384 2.245 6.6 ;
     RECT  2.053 19.968 2.245 20.472 ;
     RECT  1.073 0.048 2.293 0.072 ;
     RECT  2.245 19.872 2.293 20.472 ;
     RECT  2.252 9.12 2.329 9.144 ;
     RECT  2.113 10.32 2.329 10.344 ;
     RECT  2.245 2.016 2.341 6.6 ;
     RECT  2.293 23.472 2.341 23.496 ;
     RECT  2.341 1.44 2.408 6.6 ;
     RECT  1.477 7.92 2.408 7.944 ;
     RECT  2.329 9.12 2.408 10.344 ;
     RECT  1.181 11.664 2.408 11.784 ;
     RECT  2.293 19.344 2.408 20.472 ;
     RECT  2.293 0.048 2.533 0.168 ;
     RECT  2.533 0.048 2.629 0.456 ;
     RECT  2.408 1.44 2.629 21.612 ;
     RECT  2.629 0.048 2.704 21.72 ;
     RECT  2.704 19.92 2.725 21.72 ;
     RECT  2.341 23.376 2.725 23.496 ;
     RECT  2.725 22.752 2.818 23.496 ;
     RECT  2.704 0.048 2.867 1.56 ;
     RECT  2.725 19.92 2.881 21.768 ;
     RECT  2.867 0.048 2.963 1.368 ;
     RECT  2.881 20.016 2.981 21.768 ;
     RECT  2.818 22.752 3.089 23.64 ;
     RECT  2.981 20.112 3.265 21.768 ;
     RECT  3.089 22.752 3.265 22.776 ;
     RECT  3.265 20.112 3.443 22.776 ;
     RECT  2.704 2.832 3.845 13.704 ;
     RECT  2.963 0.048 3.973 1.176 ;
     RECT  3.845 2.832 3.985 13.656 ;
     RECT  3.973 0.048 4.165 1.272 ;
     RECT  3.985 2.592 4.165 13.656 ;
     RECT  4.165 0.048 4.205 13.656 ;
     RECT  4.205 0.624 4.313 13.656 ;
     RECT  3.443 20.112 4.417 22.728 ;
     RECT  4.313 0.624 4.451 0.648 ;
     RECT  3.925 15.984 4.46 16.008 ;
     RECT  4.417 20.112 4.595 22.824 ;
     RECT  4.595 20.112 4.741 22.296 ;
     RECT  4.741 19.92 4.949 22.296 ;
     RECT  4.313 1.728 5.108 13.656 ;
     RECT  4.46 15.984 5.108 16.44 ;
     RECT  4.949 19.824 5.108 22.296 ;
     RECT  5.317 0.384 5.381 0.408 ;
     RECT  5.108 1.728 5.404 22.296 ;
     RECT  5.381 0.096 5.461 0.408 ;
     RECT  5.404 1.728 5.461 13.608 ;
     RECT  4.837 23.328 5.509 23.592 ;
     RECT  5.509 23.328 5.555 23.64 ;
     RECT  5.461 0.096 5.651 13.608 ;
     RECT  5.651 0.096 5.689 0.168 ;
     RECT  5.651 1.152 5.699 13.608 ;
     RECT  5.404 19.92 5.933 22.296 ;
     RECT  5.555 23.472 5.933 23.64 ;
     RECT  5.933 23.568 6.035 23.64 ;
     RECT  5.404 14.832 6.049 17.112 ;
     RECT  6.049 14.832 6.157 16.584 ;
     RECT  6.157 14.832 6.185 16.008 ;
     RECT  6.035 23.616 6.185 23.64 ;
     RECT  6.185 14.832 6.293 15.432 ;
     RECT  6.293 14.832 6.401 14.856 ;
     RECT  5.699 1.728 6.613 13.608 ;
     RECT  5.933 19.968 6.725 22.296 ;
     RECT  5.689 0.144 6.949 0.168 ;
     RECT  7.621 16.848 7.693 16.872 ;
     RECT  6.613 1.728 7.808 14.52 ;
     RECT  7.693 16.848 7.808 16.92 ;
     RECT  6.721 18 7.808 18.024 ;
     RECT  7.729 19.008 7.808 19.032 ;
     RECT  6.725 20.016 7.808 22.296 ;
     RECT  6.949 0.144 8.005 0.264 ;
     RECT  8.005 0.144 8.101 0.312 ;
     RECT  7.808 1.728 8.104 22.296 ;
     RECT  8.101 23.424 8.197 23.448 ;
     RECT  8.104 19.008 8.201 22.296 ;
     RECT  8.101 0.144 8.233 0.504 ;
     RECT  8.197 23.28 8.242 23.544 ;
     RECT  8.242 23.28 8.339 23.64 ;
     RECT  8.339 23.328 8.353 23.64 ;
     RECT  8.233 0.144 8.413 0.552 ;
     RECT  8.353 23.328 8.486 23.592 ;
     RECT  8.486 23.328 8.497 23.352 ;
     RECT  8.413 0.144 8.531 0.648 ;
     RECT  8.531 0.144 8.582 0.36 ;
     RECT  8.104 1.728 8.633 13.656 ;
     RECT  8.582 0.144 8.722 0.312 ;
     RECT  8.722 0.096 8.738 0.312 ;
     RECT  8.738 0.096 8.821 0.264 ;
     RECT  8.201 19.104 9.421 22.296 ;
     RECT  8.821 0.144 9.683 0.264 ;
     RECT  8.633 1.776 9.925 13.656 ;
     RECT  9.683 0.144 10.019 0.168 ;
     RECT  10.261 23.328 10.309 23.352 ;
     RECT  10.309 23.328 10.357 23.544 ;
     RECT  9.925 1.728 10.508 13.656 ;
     RECT  8.104 16.848 10.508 18.024 ;
     RECT  9.421 19.056 10.508 22.296 ;
     RECT  10.357 23.28 10.595 23.544 ;
     RECT  10.508 1.728 10.804 22.296 ;
     RECT  10.595 23.328 10.835 23.496 ;
     RECT  10.835 23.472 11.009 23.496 ;
     RECT  10.804 16.848 11.797 18.024 ;
     RECT  11.701 0.144 11.891 0.168 ;
     RECT  11.797 16.272 12.013 18.024 ;
     RECT  10.804 1.728 12.049 14.52 ;
     RECT  12.013 15.792 12.049 18.024 ;
     RECT  12.037 23.568 12.133 23.592 ;
     RECT  12.133 0.576 12.377 0.6 ;
     RECT  12.049 1.728 12.517 18.024 ;
     RECT  12.133 23.472 12.517 23.592 ;
     RECT  10.804 19.056 13.093 22.296 ;
     RECT  12.517 23.424 13.093 23.592 ;
     RECT  12.517 1.152 13.208 18.024 ;
     RECT  13.093 19.008 13.208 22.296 ;
     RECT  13.208 1.152 13.381 22.296 ;
     RECT  13.381 0.336 13.429 22.296 ;
     RECT  13.429 0.192 13.628 22.296 ;
     RECT  13.093 23.424 13.628 23.64 ;
     RECT  13.628 0.192 13.667 23.64 ;
     RECT  13.667 1.728 13.715 23.64 ;
     RECT  13.667 0.192 13.765 0.456 ;
     RECT  13.765 0.144 13.81 0.456 ;
     RECT  13.715 23.568 13.997 23.64 ;
     RECT  13.81 0.096 14.099 0.456 ;
     RECT  14.099 0.096 14.177 0.36 ;
     RECT  14.177 0.096 14.221 0.264 ;
     RECT  14.221 0.24 14.243 0.264 ;
     RECT  13.997 23.568 14.723 23.592 ;
     RECT  13.715 1.728 15.397 22.392 ;
     RECT  15.397 0.576 15.541 0.6 ;
     RECT  15.397 1.728 15.541 23.544 ;
     RECT  15.541 0.576 15.637 23.544 ;
     RECT  15.637 0.144 16.069 23.544 ;
     RECT  16.069 0.096 16.337 23.592 ;
     RECT  16.337 0.144 16.355 23.592 ;
     RECT  16.355 0.192 16.451 23.544 ;
     RECT  16.451 0.192 16.499 23.496 ;
     RECT  16.499 0.192 16.547 0.216 ;
     RECT  16.499 1.68 16.547 23.496 ;
     RECT  16.547 1.68 17.075 22.872 ;
     RECT  17.075 1.728 18.229 22.872 ;
     RECT  18.229 1.152 18.325 22.872 ;
     RECT  18.325 1.152 18.529 23.592 ;
     RECT  18.529 0.528 18.707 23.592 ;
     RECT  18.707 1.152 18.803 23.592 ;
     RECT  18.803 1.728 19.043 23.592 ;
     RECT  18.853 0.096 19.187 0.168 ;
     RECT  19.187 0.144 19.283 0.168 ;
     RECT  19.043 1.728 20.197 22.872 ;
     RECT  20.197 1.728 20.333 23.64 ;
     RECT  20.005 0.576 21.089 0.6 ;
     RECT  20.333 1.728 21.637 23.592 ;
     RECT  21.637 1.152 21.826 23.592 ;
     RECT  21.826 1.152 21.971 23.64 ;
     RECT  21.971 1.152 22.019 23.544 ;
     RECT  22.019 1.152 22.025 23.496 ;
     RECT  22.025 1.2 22.115 23.496 ;
     RECT  22.115 1.2 22.211 22.872 ;
     RECT  22.211 1.728 23.921 22.872 ;
     RECT  23.921 1.68 23.941 22.872 ;
     RECT  23.941 1.68 24.133 23.352 ;
     RECT  24.037 0.24 24.229 0.264 ;
     RECT  24.133 1.68 24.277 23.4 ;
     RECT  24.229 0.24 24.419 0.552 ;
     RECT  24.419 0.336 24.515 0.552 ;
     RECT  24.277 1.68 24.517 23.496 ;
     RECT  24.517 1.152 24.803 23.592 ;
     RECT  24.803 1.152 25.091 23.496 ;
     RECT  25.649 0.096 25.717 0.12 ;
     RECT  25.091 1.152 25.717 22.92 ;
     RECT  25.717 0.096 25.733 22.92 ;
     RECT  25.733 0.144 26.243 22.92 ;
     RECT  26.243 0.144 26.489 0.6 ;
     RECT  26.489 0.144 26.675 0.456 ;
     RECT  26.675 0.192 27.347 0.456 ;
     RECT  26.243 1.728 27.541 22.92 ;
     RECT  27.541 1.152 28.357 22.92 ;
     RECT  28.357 1.152 28.505 23.64 ;
     RECT  28.117 0.144 28.549 0.168 ;
     RECT  28.505 1.152 28.549 23.592 ;
     RECT  28.549 0.096 28.691 23.592 ;
     RECT  28.691 0.096 28.829 0.408 ;
     RECT  28.691 1.728 28.835 23.592 ;
     RECT  28.835 1.728 29.459 23.496 ;
     RECT  28.829 0.144 29.797 0.408 ;
     RECT  29.797 0.144 29.845 0.456 ;
     RECT  29.459 1.728 29.845 22.92 ;
     RECT  29.845 0.144 29.89 22.92 ;
     RECT  29.89 0.096 30.757 22.92 ;
     RECT  30.757 0.096 30.997 23.592 ;
     RECT  30.997 0.144 31.141 23.592 ;
     RECT  31.141 0.144 32.243 23.64 ;
     RECT  32.243 0.528 32.609 23.64 ;
     RECT  32.609 0.528 32.62 23.448 ;
     RECT  32.62 0.528 33.107 22.872 ;
     RECT  33.301 0.144 33.491 0.168 ;
     RECT  33.107 1.152 33.637 22.872 ;
     RECT  33.637 1.152 33.821 23.592 ;
     RECT  33.821 1.152 33.905 23.64 ;
     RECT  33.905 1.152 34.019 23.592 ;
     RECT  34.019 1.152 34.789 23.544 ;
     RECT  34.789 0.336 35.029 23.544 ;
     RECT  35.029 0.336 35.077 23.592 ;
     RECT  35.077 0.096 35.416 23.592 ;
     RECT  35.416 0.096 35.942 23.64 ;
     RECT  35.942 0.096 35.993 23.592 ;
     RECT  35.993 0.192 36.419 23.592 ;
     RECT  36.419 1.728 36.892 23.592 ;
     RECT  36.419 0.192 37.093 0.6 ;
     RECT  36.892 1.776 37.861 23.592 ;
     RECT  37.093 0.096 37.909 0.6 ;
     RECT  37.861 1.728 37.909 23.592 ;
     RECT  37.909 0.096 38.125 23.592 ;
     RECT  38.125 0.144 38.147 1.896 ;
     RECT  38.125 2.88 38.147 23.592 ;
     RECT  38.147 1.344 38.195 1.896 ;
     RECT  38.147 2.88 38.195 22.872 ;
     RECT  38.147 0.144 38.243 0.264 ;
     RECT  38.243 0.24 38.387 0.264 ;
     RECT  38.195 3.072 39.157 22.872 ;
     RECT  38.195 1.728 39.445 1.896 ;
     RECT  39.157 2.88 39.445 22.872 ;
     RECT  39.365 0.096 39.449 0.12 ;
     RECT  39.445 1.728 39.701 22.872 ;
     RECT  39.637 0.144 39.877 0.168 ;
     RECT  39.701 1.824 39.925 22.872 ;
     RECT  39.925 1.824 40.021 23.544 ;
     RECT  39.877 0.144 40.69 0.6 ;
     RECT  40.021 1.824 40.741 23.592 ;
     RECT  40.69 0.096 40.789 0.6 ;
     RECT  40.741 1.728 40.837 23.592 ;
     RECT  40.789 0.144 40.922 0.6 ;
     RECT  40.922 0.192 41.005 0.6 ;
     RECT  41.005 0.528 41.125 0.6 ;
     RECT  40.837 1.728 41.177 23.64 ;
     RECT  41.125 0.528 41.573 0.648 ;
     RECT  41.573 0.528 41.843 0.552 ;
     RECT  42.037 0.096 42.227 0.264 ;
     RECT  41.177 1.728 42.757 23.592 ;
     RECT  43.045 0.576 43.141 0.6 ;
     RECT  42.757 1.68 43.141 23.592 ;
     RECT  43.141 0.576 43.331 23.592 ;
     RECT  43.331 0.576 43.427 22.872 ;
     RECT  43.427 0.576 43.477 22.824 ;
     RECT  43.477 0.528 44.149 22.824 ;
     RECT  44.149 0.144 44.675 22.824 ;
     RECT  44.675 0.144 44.741 22.488 ;
     RECT  44.741 1.152 44.915 22.488 ;
     RECT  44.915 1.152 45.173 22.44 ;
     RECT  44.741 0.144 45.733 0.168 ;
     RECT  45.173 1.152 45.733 22.344 ;
     RECT  45.733 0.144 46.114 22.344 ;
     RECT  46.114 0.096 46.259 22.344 ;
     RECT  46.259 0.192 46.307 22.344 ;
     RECT  46.307 0.384 46.433 22.344 ;
     RECT  46.433 1.248 47.557 22.344 ;
     RECT  47.077 23.568 47.989 23.592 ;
     RECT  47.989 23.472 48.13 23.592 ;
     RECT  47.557 1.152 48.227 22.344 ;
     RECT  47.893 0.144 48.517 0.168 ;
     RECT  48.13 23.472 48.517 23.64 ;
     RECT  48.517 23.328 48.755 23.64 ;
     RECT  48.755 23.424 48.845 23.64 ;
     RECT  48.845 23.52 48.851 23.64 ;
     RECT  48.851 23.616 49.089 23.64 ;
     RECT  48.517 0.144 49.234 0.6 ;
     RECT  49.234 0.096 49.621 0.6 ;
     RECT  48.227 1.728 49.621 22.344 ;
     RECT  50.021 23.52 50.06 23.544 ;
     RECT  49.621 0.096 50.099 22.344 ;
     RECT  50.06 23.376 50.147 23.544 ;
     RECT  50.099 0.096 50.285 0.6 ;
     RECT  50.285 0.096 50.483 0.408 ;
     RECT  50.147 23.472 50.773 23.544 ;
     RECT  50.773 23.472 50.917 23.592 ;
     RECT  50.483 0.096 51.059 0.36 ;
     RECT  50.099 1.728 51.301 22.344 ;
     RECT  50.917 23.472 51.301 23.64 ;
     RECT  51.301 1.728 51.473 23.64 ;
     RECT  51.059 0.096 51.491 0.264 ;
     RECT  51.473 1.728 51.779 23.112 ;
     RECT  51.779 1.728 52.019 22.824 ;
     RECT  51.491 0.096 52.453 0.216 ;
     RECT  52.453 0.096 52.625 0.552 ;
     RECT  52.019 1.728 53.297 22.344 ;
     RECT  52.625 0.096 53.605 0.168 ;
     RECT  53.297 1.152 53.605 22.344 ;
     RECT  53.557 23.52 53.893 23.544 ;
     RECT  53.893 23.424 54.085 23.544 ;
     RECT  53.605 0.096 54.131 22.344 ;
     RECT  54.131 0.192 54.169 22.344 ;
     RECT  54.085 23.424 54.169 23.64 ;
     RECT  54.169 0.192 54.179 23.64 ;
     RECT  54.179 1.152 54.461 23.64 ;
     RECT  54.461 1.152 54.467 23.592 ;
     RECT  54.467 1.152 54.659 23.496 ;
     RECT  54.659 1.152 54.899 22.824 ;
     RECT  54.899 1.152 55.285 22.344 ;
     RECT  55.285 0.528 55.763 22.344 ;
     RECT  55.763 0.528 56.245 0.6 ;
     RECT  56.485 23.328 56.581 23.352 ;
     RECT  56.581 23.328 56.677 23.496 ;
     RECT  56.245 0.144 56.725 0.6 ;
     RECT  55.763 1.728 56.725 22.344 ;
     RECT  56.677 23.328 56.753 23.544 ;
     RECT  56.725 0.144 56.905 22.344 ;
     RECT  56.753 23.328 56.905 23.64 ;
     RECT  56.905 0.144 56.963 23.64 ;
     RECT  56.963 0.24 56.989 23.64 ;
     RECT  56.989 0.24 57.011 22.344 ;
     RECT  56.989 23.52 57.011 23.64 ;
     RECT  57.011 0.24 57.025 0.264 ;
     RECT  57.011 23.568 57.269 23.64 ;
     RECT  57.011 1.728 57.305 22.344 ;
     RECT  57.305 1.728 57.341 4.008 ;
     RECT  57.341 1.776 57.593 4.008 ;
     RECT  57.305 5.04 57.593 22.344 ;
     RECT  57.593 5.04 57.629 21.528 ;
     RECT  57.629 5.088 57.853 21.528 ;
     RECT  57.593 1.776 58.309 1.848 ;
     RECT  57.269 23.568 58.501 23.592 ;
     RECT  57.593 2.832 58.597 4.008 ;
     RECT  57.853 5.088 58.597 13.944 ;
     RECT  58.501 23.328 58.597 23.592 ;
     RECT  58.597 23.328 58.643 23.64 ;
     RECT  57.853 15.408 58.777 21.528 ;
     RECT  58.309 1.728 58.796 1.848 ;
     RECT  58.597 2.832 58.796 13.944 ;
     RECT  58.741 0.144 58.885 0.168 ;
     RECT  58.796 1.728 58.885 13.944 ;
     RECT  58.885 0.144 59.108 13.944 ;
     RECT  58.777 15.408 59.108 21.672 ;
     RECT  59.108 0.144 59.269 21.672 ;
     RECT  59.269 0.144 59.315 21.72 ;
     RECT  59.315 1.728 59.365 21.72 ;
     RECT  59.365 1.728 59.404 21.768 ;
     RECT  59.404 17.136 59.555 21.768 ;
     RECT  59.555 17.136 59.651 21.624 ;
     RECT  58.643 23.376 59.698 23.64 ;
     RECT  59.698 23.328 59.846 23.64 ;
     RECT  59.651 17.424 60.077 21.624 ;
     RECT  59.404 1.728 60.221 13.656 ;
     RECT  59.315 0.144 60.371 0.648 ;
     RECT  59.846 23.328 60.397 23.592 ;
     RECT  60.397 22.8 60.563 23.592 ;
     RECT  60.077 17.904 61.045 21.624 ;
     RECT  60.221 1.728 61.237 5.4 ;
     RECT  60.221 6.576 61.237 13.656 ;
     RECT  60.563 23.52 61.426 23.592 ;
     RECT  61.045 17.904 61.573 22.248 ;
     RECT  61.426 23.52 61.573 23.64 ;
     RECT  60.371 0.576 61.621 0.648 ;
     RECT  61.237 1.728 61.808 13.656 ;
     RECT  61.573 17.664 61.808 22.248 ;
     RECT  61.808 1.728 61.811 22.248 ;
     RECT  61.621 0.528 61.861 0.648 ;
     RECT  61.573 23.376 61.907 23.64 ;
     RECT  61.811 2.148 61.912 22.248 ;
     RECT  61.912 2.256 62.104 22.248 ;
     RECT  62.104 2.256 62.201 6.888 ;
     RECT  62.201 2.256 62.237 2.52 ;
     RECT  62.104 8.544 62.245 8.568 ;
     RECT  62.201 3.936 62.339 6.888 ;
     RECT  61.861 0.096 62.341 0.648 ;
     RECT  62.104 17.472 62.345 22.248 ;
     RECT  62.104 10.368 62.435 10.392 ;
     RECT  62.339 6.672 62.453 6.888 ;
     RECT  62.339 3.936 62.476 5.208 ;
     RECT  62.453 6.672 62.483 6.696 ;
     RECT  61.907 23.52 62.483 23.64 ;
     RECT  62.483 23.568 62.489 23.64 ;
     RECT  62.476 4.512 62.531 5.208 ;
     RECT  62.489 23.616 62.561 23.64 ;
     RECT  62.531 5.136 62.579 5.208 ;
     RECT  62.345 18.768 62.579 19.56 ;
     RECT  62.345 20.544 62.674 22.248 ;
     RECT  62.341 0.096 62.675 1.128 ;
     RECT  62.674 20.544 62.771 22.296 ;
     RECT  62.771 21.12 62.867 22.296 ;
     RECT  62.237 2.256 62.953 2.328 ;
     RECT  62.579 5.136 62.963 5.16 ;
     RECT  62.345 17.472 62.963 17.688 ;
     RECT  62.675 0.096 63.029 0.6 ;
     RECT  62.953 1.68 63.059 2.328 ;
     RECT  62.867 21.12 63.059 21.672 ;
     RECT  63.029 0.144 63.065 0.6 ;
     RECT  63.059 2.304 63.101 2.328 ;
     RECT  63.065 0.144 63.137 0.168 ;
     RECT  63.059 21.12 63.155 21.192 ;
     RECT  63.26 17.136 63.347 17.256 ;
     RECT  63.347 17.232 63.443 17.256 ;
     RECT  62.579 19.344 63.635 19.56 ;
     RECT  63.155 21.12 63.827 21.144 ;
     RECT  63.845 23.616 63.929 23.64 ;
     RECT  63.635 19.344 64.019 19.368 ;
    LAYER M5 ;
     RECT  0.72 0.016 63.048 1.715 ;
     RECT  0.72 1.715 62.952 1.859 ;
     RECT  0.72 1.859 57.48 2.821 ;
     RECT  58.512 1.859 62.952 2.821 ;
     RECT  0.72 2.821 62.952 2.915 ;
     RECT  0.912 2.915 62.952 2.963 ;
     RECT  1.104 2.963 62.952 4.595 ;
     RECT  1.2 4.595 62.952 5.171 ;
     RECT  1.488 5.171 62.568 5.219 ;
     RECT  1.488 5.219 62.52 7.955 ;
     RECT  2.304 7.955 62.52 8.579 ;
     RECT  2.304 8.579 49.32 8.867 ;
     RECT  2.304 8.867 47.064 9.155 ;
     RECT  2.4 9.155 47.064 9.203 ;
     RECT  2.4 9.203 14.52 9.299 ;
     RECT  15.6 9.203 47.064 9.731 ;
     RECT  15.6 9.731 41.16 9.779 ;
     RECT  2.4 9.299 13.8 9.827 ;
     RECT  15.9 9.779 41.16 10.019 ;
     RECT  50.592 8.579 62.52 10.021 ;
     RECT  48.3 8.867 49.32 10.069 ;
     RECT  50.496 10.021 62.52 10.069 ;
     RECT  42.528 9.731 47.064 10.117 ;
     RECT  48.3 10.069 62.52 10.211 ;
     RECT  42.528 10.117 47.256 10.259 ;
     RECT  13.104 9.827 13.8 10.261 ;
     RECT  13.104 10.261 14.712 10.307 ;
     RECT  48.3 10.211 49.56 10.405 ;
     RECT  48.048 10.405 49.56 10.547 ;
     RECT  14.688 10.307 14.712 10.835 ;
     RECT  42.528 10.259 47.064 10.885 ;
     RECT  42.432 10.885 47.064 10.931 ;
     RECT  17.232 10.019 41.16 11.123 ;
     RECT  2.4 9.827 11.736 11.171 ;
     RECT  13.104 10.307 13.512 11.219 ;
     RECT  48.3 10.547 49.56 11.605 ;
     RECT  50.592 10.211 62.52 11.605 ;
     RECT  15.9 10.019 16.212 11.653 ;
     RECT  15.36 11.653 16.212 11.939 ;
     RECT  2.4 11.171 8.52 12.035 ;
     RECT  10.176 11.171 11.736 12.035 ;
     RECT  48.3 11.605 62.52 12.035 ;
     RECT  53.232 12.035 62.52 12.131 ;
     RECT  2.4 12.035 8.112 12.563 ;
     RECT  42.432 10.931 45.912 13.669 ;
     RECT  46.944 10.931 47.064 13.669 ;
     RECT  50.736 12.035 51.864 13.715 ;
     RECT  5.1 12.563 8.112 14.291 ;
     RECT  50.832 13.715 51.864 14.965 ;
     RECT  50.832 14.965 52.248 15.301 ;
     RECT  53.328 12.131 62.52 15.301 ;
     RECT  2.4 12.563 3.96 16.019 ;
     RECT  5.1 14.291 6.648 16.405 ;
     RECT  42.432 13.669 47.064 16.547 ;
     RECT  50.832 15.301 62.52 17.125 ;
     RECT  17.232 11.123 17.256 17.221 ;
     RECT  18.288 11.123 41.16 17.221 ;
     RECT  50.832 17.125 63.336 17.221 ;
     RECT  17.232 17.221 41.16 17.267 ;
     RECT  13.2 11.219 13.512 19.285 ;
     RECT  17.376 17.267 41.16 19.285 ;
     RECT  42.432 16.547 45.912 19.285 ;
     RECT  2.4 16.019 3.144 19.333 ;
     RECT  13.104 19.285 13.512 19.333 ;
     RECT  50.832 17.221 63.432 19.333 ;
     RECT  10.5 12.035 11.736 19.621 ;
     RECT  12.816 19.333 13.512 19.621 ;
     RECT  15.9 11.939 16.212 19.621 ;
     RECT  17.376 19.285 45.912 19.621 ;
     RECT  48.3 12.035 49.56 19.621 ;
     RECT  50.832 19.333 64.008 19.621 ;
     RECT  46.944 16.547 47.064 19.813 ;
     RECT  48.3 19.621 64.008 19.813 ;
     RECT  2.304 19.333 3.144 19.861 ;
     RECT  10.5 19.621 13.512 19.909 ;
     RECT  14.64 19.813 14.664 19.909 ;
     RECT  15.9 19.621 45.912 19.909 ;
     RECT  2.256 19.861 3.144 19.957 ;
     RECT  4.512 16.405 6.648 20.003 ;
     RECT  2.064 19.957 3.144 20.053 ;
     RECT  1.968 20.053 3.144 20.149 ;
     RECT  4.512 20.003 6.264 20.149 ;
     RECT  7.8 14.291 8.112 20.149 ;
     RECT  9.552 19.909 14.712 20.149 ;
     RECT  15.792 19.909 45.912 20.149 ;
     RECT  46.944 19.813 64.008 20.149 ;
     RECT  1.776 20.149 3.144 21.109 ;
     RECT  4.272 20.149 6.264 21.109 ;
     RECT  7.8 20.149 64.008 21.109 ;
     RECT  7.536 21.109 64.008 21.253 ;
     RECT  1.776 21.109 6.264 21.493 ;
     RECT  7.344 21.253 64.008 21.493 ;
     RECT  1.776 21.493 64.008 23.696 ;
  END
END hbfd_rly_624_NS_rrfc
END LIBRARY
